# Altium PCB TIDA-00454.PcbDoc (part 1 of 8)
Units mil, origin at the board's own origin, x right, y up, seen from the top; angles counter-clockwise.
Board outline 6159 x 2859 mil, 2 copper layers (Top Layer, Bottom Layer), stack 62 mil thick; 328 components, 224 nets, 884 pads, 184 vias.

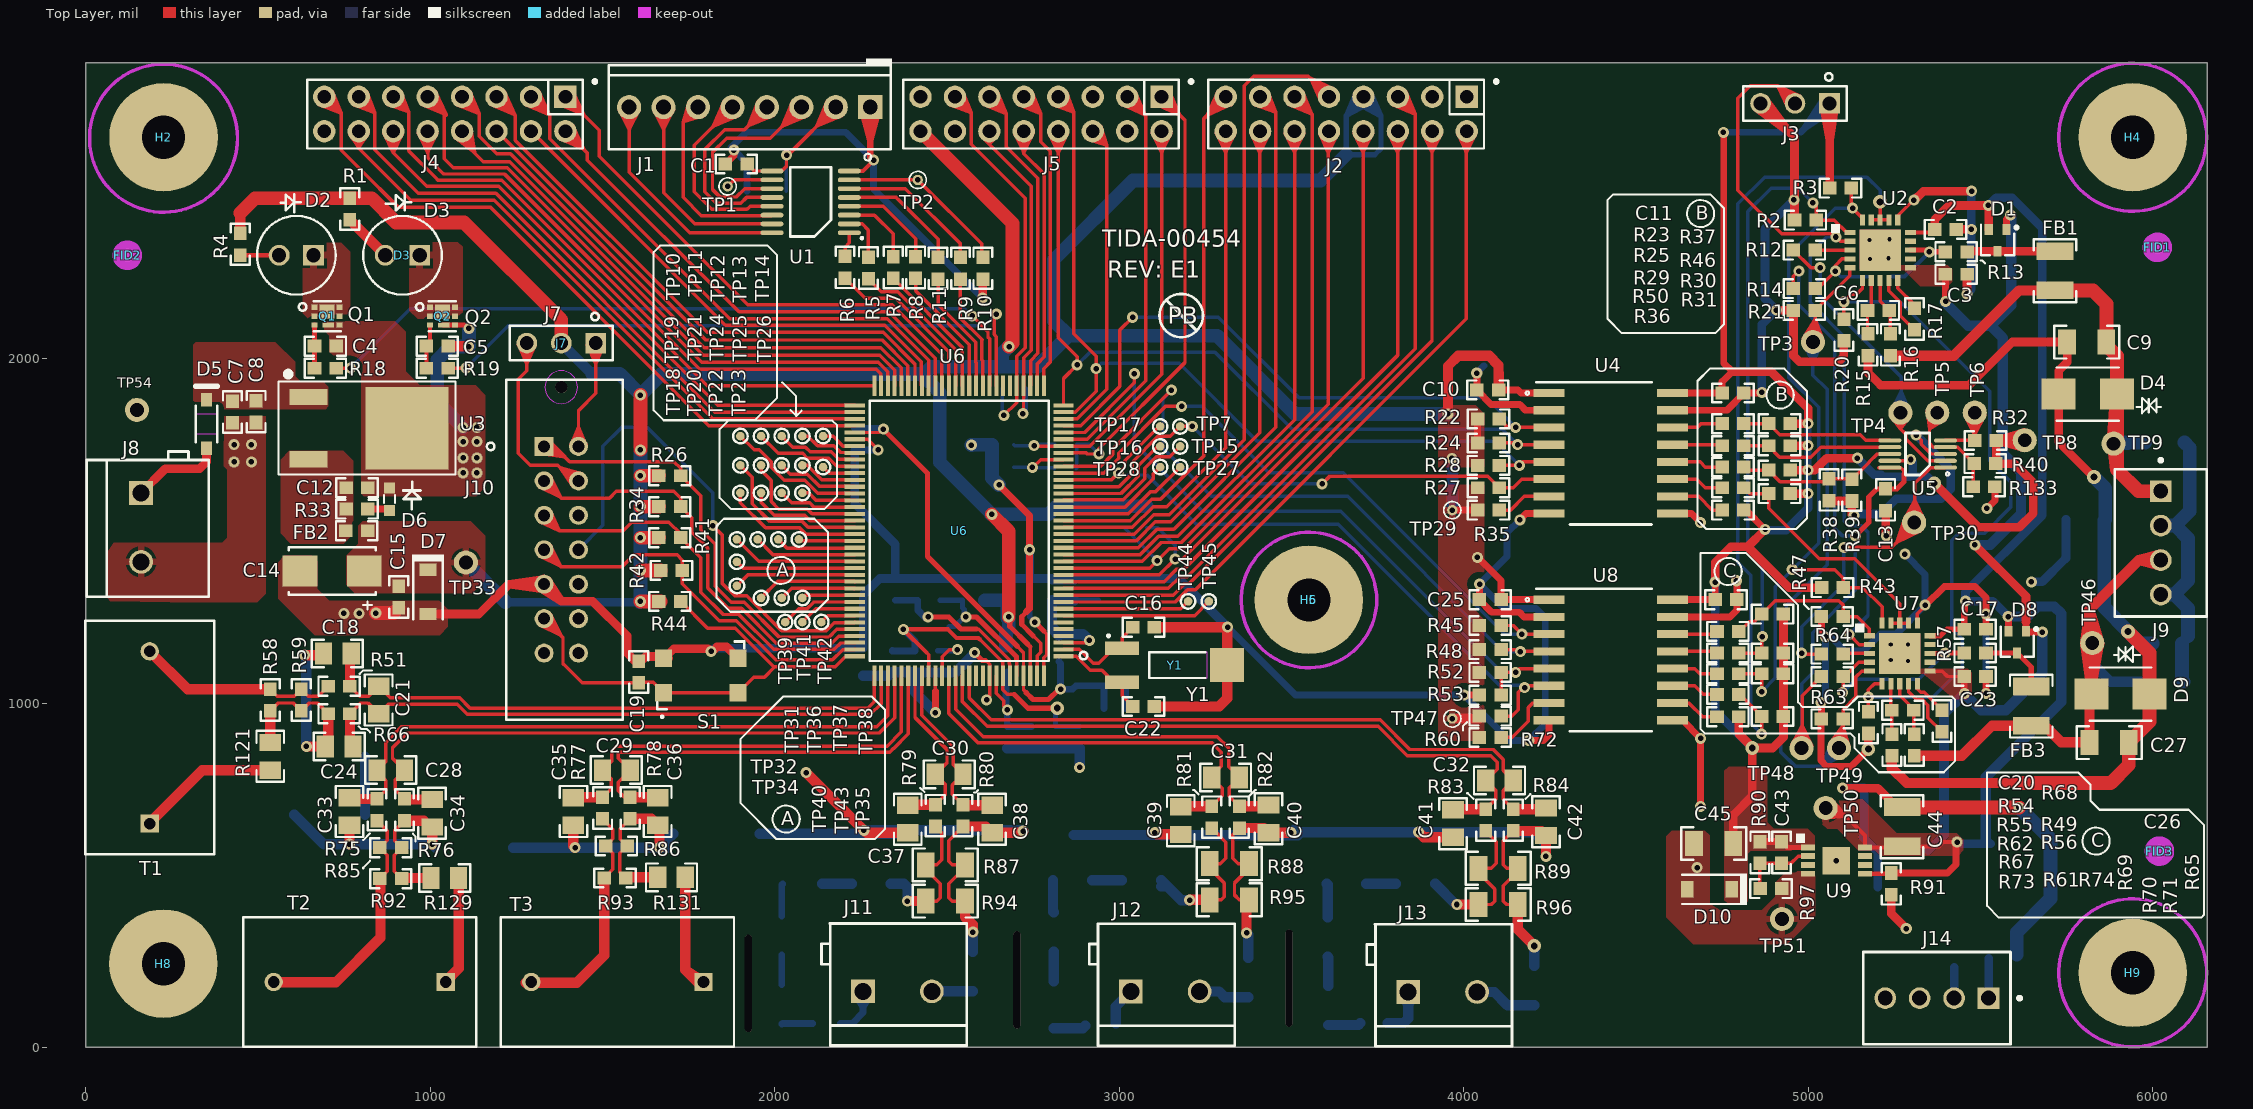
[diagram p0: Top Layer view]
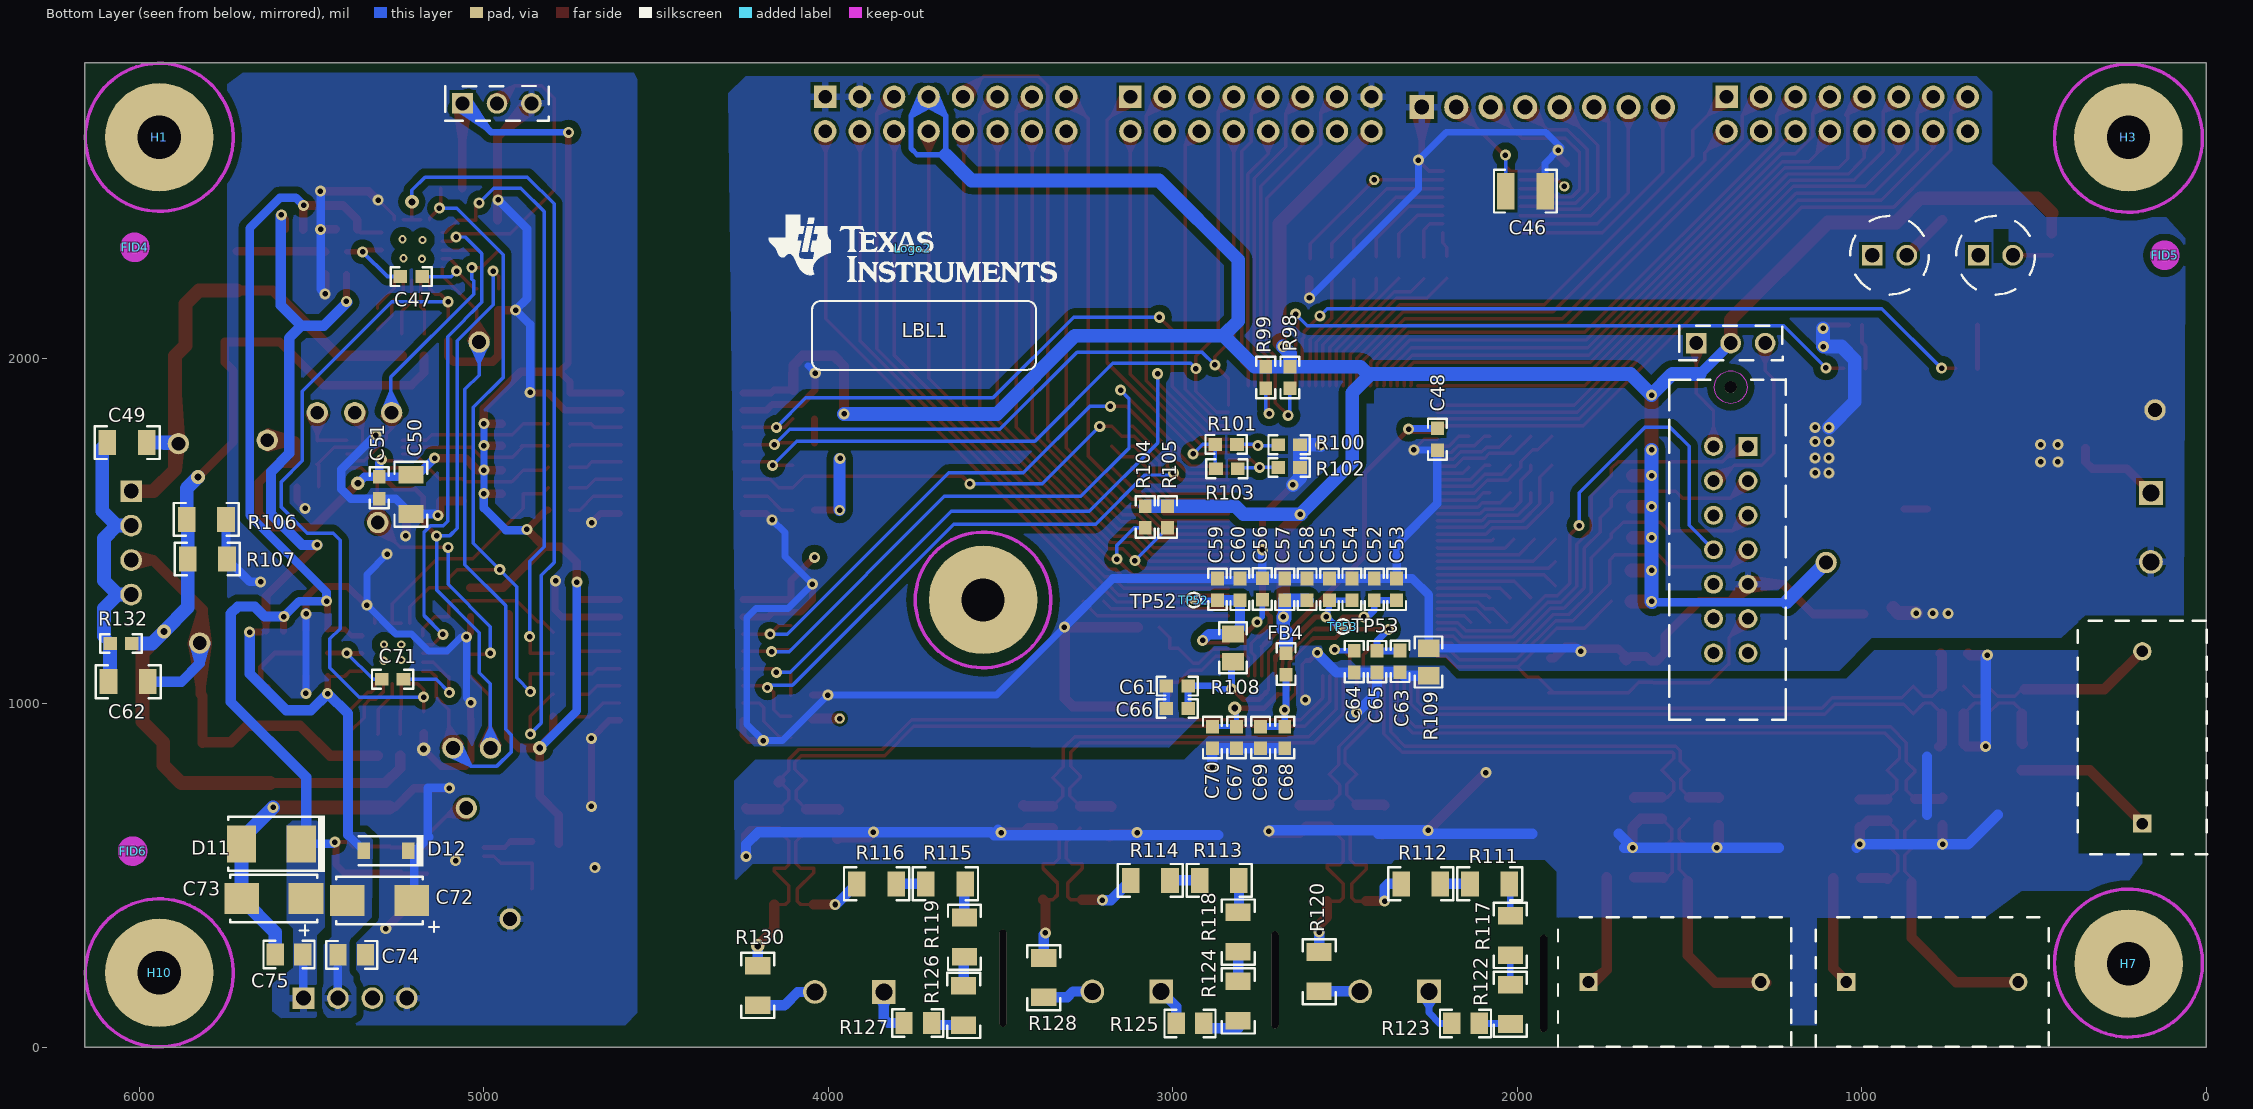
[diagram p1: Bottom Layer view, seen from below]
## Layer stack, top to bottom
Top Solder: solder mask 0.4, Solder Resist, Dk 3.5
Top Layer: signal copper 1.4
Dielectric1: core 59.2, FR-4, Dk 4.8
Bottom Layer: signal copper 1.4
Bottom Solder: solder mask 0.4, Solder Resist, Dk 3.5

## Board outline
0,0 0,2859 6159,2859 6159,0

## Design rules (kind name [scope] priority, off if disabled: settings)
AcuteAngle [All] p1: minimum=4.50000000000000E+0001 checktracksonly=FALSE
AssemblyTestPointUsage [All] p1: valid=2
Clearance Clearance_u4 [(InPadClass('All Pads'))] p1: gap=7.8
Clearance Clearance_1 [IsVia vs IsPad] p2: gap=5
Clearance "Clearance_VIA TO VIA" [IsVia vs IsVia] p3: gap=8
Clearance "Clearance_Via to SMD" [IsVia vs IsPad] p4: gap=8
Clearance Clearance_BoardEdge_MountingHoles [OnCopper and InComponentClass('Mounting Holes') vs IsKeepOut] p5: gap=33
Clearance Clearance_Poly [InPolygon] p6: gap=20
Clearance [All] p7: gap=8
Clearance "Clearance_Poly to Poly" [InPolygon vs InPolygon] p8: gap=20
ComponentClearance ComponentClearance_Logo [InComponentClass('Logo')] p1: gap=50 collisioncheckmode=3 verticalgap=10 showdistances=FALSE
ComponentClearance ComponentClearance_ScrewToNut [(HasFootprint('NY PMS 440 0025 PH')) vs (HasFootprint('Keystone_1902C'))] p2: gap=5 collisioncheckmode=3 verticalgap=10 showdistances=FALSE
ComponentClearance ComponentClearance_MountingHoles [InComponentClass('Mounting Holes')] p3: gap=250 collisioncheckmode=3 verticalgap=100000 showdistances=FALSE
ComponentClearance ComponentClearance_SmallPassives [HasFootprint('0201*') or HasFootprint('0402*') or HasFootprint('0508') or HasFootprint('0603*') or HasFootprint('0612') or HasFootprint('0805*') or HasFootprint('0815*') or HasFootprint('0830*') or HasFootprint('1206*') or HasFootprint('1210*') or HasFootprint('1808*') or HasFootprint('1812*') or HasFootprint('1825*') or HasFootprint('2010*') or HasFootprint('2220*') or HasFootprint('2225*') or HasFootprint('2512*') or HasFootprint('2728*') or HasFootprint('3518*') vs HasFootprint('0201*') or HasFootprint('0402*') or HasFootprint('0508') or HasFootprint('0603*') or HasFootprint('0612') or HasFootprint('0805*') or HasFootprint('0815*') or HasFootprint('0830*') or HasFootprint('1206*') or HasFootprint('1210*') or HasFootprint('1808*') or HasFootprint('1812*') or HasFootprint('1825*') or HasFootprint('2010*') or HasFootprint('2220*') or HasFootprint('2225*') or HasFootprint('2512*') or HasFootprint('2728*') or HasFootprint('3518*')] p4: gap=20 collisioncheckmode=3 verticalgap=10 showdistances=FALSE
ComponentClearance ComponentClearance_THtoSMT [IsThruComponent vs IsSMTComponent] p5: gap=100 collisioncheckmode=3 verticalgap=30 showdistances=FALSE
ComponentClearance ComponentClearance_THtoTH [IsThruComponent vs IsThruComponent] p6: gap=118.11 collisioncheckmode=3 verticalgap=30 showdistances=FALSE
ComponentClearance [All] p7: gap=40 collisioncheckmode=3 verticalgap=10 showdistances=FALSE
DiffPairsRouting [All] p1: maxlimit=100 minlimit=10 mostfreqgap=10 toplayer_minwidth=15 toplayer_maxwidth=15 toplayer_prefwidth=15 bottomlayer_minwidth=15 bottomlayer_maxwidth=15 bottomlayer_prefwidth=15 maxuncoupledlength=1000
FabricationTestPointUsage TestPointUsage [All] p1: valid=2 allowmultiple=FALSE
FabricationTestpoint Testpoint [All] p1: side=3 testpointundercomponent=TRUE minsize=40 maxsize=100 preferedsize=60 minholesize=0 maxholesize=40 preferedholesize=32 testpointgrid=1 allowsidetop=TRUE allowsidebottom=TRUE usegrid=TRUE gridtolerance=0.01
FanoutControl Fanout_LCC [IsLCC] p1: bgadir=Out bgaviamode=Centered fanoutstyle=Auto fanoutdirection=Alternating viagrid=1 // Fanout_LCC (Default Rule)
FanoutControl Fanout_BGA [IsBGA] p2: bgadir=Out bgaviamode=Centered fanoutstyle=Auto fanoutdirection=Alternating viagrid=1 // Fanout_BGA (Default Rule)
FanoutControl Fanout_Default [All] p4: bgadir=Out bgaviamode=Centered fanoutstyle=Auto fanoutdirection=Alternating viagrid=1 // Fanout_Default (Default Rule)
FanoutControl Fanout_Small [(CompPinCount < 5)] p5: bgadir=Out bgaviamode=Centered fanoutstyle=Auto fanoutdirection=OutThenIn viagrid=1 // Fanout_Small (Default Rule)
HoleSize [All] p1: absolutevalues=TRUE maxlimit=300 minlimit=7.8 maxpercent=80.000 minpercent=20.000
MatchedLengths [InNetClass('length')] p1: tolerance=50 checknetsindiffpair=TRUE checkdiffpairvsdiffpair=TRUE checkothers=TRUE
MinimumAnnularRing MinimumAnnularRing_ThermalPadVias [IsVia and InAnyComponent] p1: minimumring=5
MinimumAnnularRing [All] p2: minimumring=5
MinimumSolderMaskSliver MinimumSolderMaskSliver_Logo [InComponentClass('Logo') vs InComponentClass('Logo')] p1: minsoldermaskwidth=0.7
MinimumSolderMaskSliver [All] p2: minsoldermaskwidth=3.94
PlaneClearance [All] p1: clearance=16
PlaneConnect [All] p1: planeconnectstyle=Direct reliefexpansion=10 reliefentries=4 reliefconductorwidth=10 reliefairgap=10
PolygonConnect PolygonConnect_TH_PAD [IsThruPin] p1: connectstyle=Relief reliefconductorwidth=20 reliefentries=4 polygonreliefangle="90 Angle" airgapwidth=10
PolygonConnect PolygonConnect_isVia [IsVia] p2: connectstyle=Direct reliefconductorwidth=10 reliefentries=4 polygonreliefangle="90 Angle" airgapwidth=10
PolygonConnect PolygonConnect_SMTPAD [IsSMTPin] p3: connectstyle=Direct reliefconductorwidth=20 reliefentries=4 polygonreliefangle="90 Angle" airgapwidth=10
RoutingVias RoutingVias_PWR [InNetClass('PWR')] p1: holewidth=16 width=30 viastyle="Through Hole" minholewidth=16 minwidth=30 maxholewidth=20 maxwidth=40
RoutingVias [All] p2: holewidth=12 width=24 viastyle="Through Hole" minholewidth=12 minwidth=24 maxholewidth=20 maxwidth=40
RoutingVias ThermalPadVias [InNet('GND_SIGNAL')] p3: holewidth=7.87 width=19.68 viastyle="Through Hole" minholewidth=7.87 minwidth=19.68 maxholewidth=12.99 maxwidth=23.62
SMDToCorner [All] p1: distance=30000
SilkToSilkClearance [All] p1: silktosilkclearance=5
SilkToSolderMaskClearance SilkscreenOverComponentPads [IsPad] p1: minsilkscreentomaskgap=5 clearancetoexposedcopper=TRUE
SolderMaskExpansion [All] p1: expansion=2.5
UnpouredPolygon [All] p1: allowunpoured=FALSE
ViasUnderSMD [InComponent('U1')] p1: allowed=TRUE
Width Width_PWR [InNetClass('PWR')] p1: maxlimit=100 minlimit=8 preferedwidth=20 minimp=50.000000 maximp=50.000000 favimp=50.000000
Width [All] p2: maxlimit=100 minlimit=10 preferedwidth=10 checkconnectedcopper=TRUE
14 further rules are at their usual default settings.

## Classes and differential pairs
component class "Pg7.Digital Isolators": C10 C11 C20 C25 R22 R23 R24 R25 R27 R28 R29 R30 R31 R35 R36 R37 R38 R45 R46 R48 R49 R50 R52 R53 R54 R55 R56 R60 R61 R62 R67 R68 R72 R73 TP29 TP47 U4 U8
component class Pg3.MSP430F67791A+LED: C4 C5 C16 C22 C66 D2 D3 Q1 Q2 R1 R4 R18 R19 R98 R99 R100 R101 R102 R103 R104 R105 R108 TP7 TP10 TP11 TP12 TP13 TP14 TP15 TP16 TP17 TP18 TP19 TP20 TP21 TP22 TP23 TP24 TP25 TP26 TP27 TP28 TP31 TP32 TP34 TP35 TP36 TP37 TP38 TP39 TP40 TP41 TP42 TP43 TP44 TP45 U6 Y1
component class "Pg6.Isolated and Non Isolated Power Supply": C7 C8 C12 C14 C15 C43 C44 C45 C72 C73 C74 C75 D5 D6 D7 D10 D11 D12 D19 FB2 J8 J14 R33 R90 R91 R97 R106 R107 TP8 TP33 TP50 TP51 TP54 U3 U9
component class "Pg10.HARDWARE - MISCELLANEOUS.": !PCB1 FID1 FID2 FID3 FID4 FID5 FID6 H1 H2 H3 H4 H5 H6 H7 H8 H9 H10 ZZ1 ZZ2 ZZ3 ZZ4
component class "Mounting Holes": H2 H4 H6 H8 H9
component class FiducialMark: FID1 FID2 FID3 FID4 FID5 FID6
component class AssemblyNote: ZZ1 ZZ2 ZZ3 ZZ4
component class "Pg5.Analog Front End - Current and Voltage": C18 C21 C24 C28 C29 C30 C31 C32 C33 C34 C35 C36 C37 C38 C39 C40 C41 C42 J11 J12 J13 R51 R58 R59 R66 R75 R76 R77 R78 R79 R80 R81 R82 R83 R84 R85 R86 R87 R88 R89 R92 R93 R94 R95 R96 R111 R112 R113 R114 R115 R116 R117 R118 R119 R120 R121 R122 R123 R124 R125 R126 R127 R128 R129 R130 R131 T1 T2 T3
component class "Pg4. Relay Drivers+JTAG Interface +Decoupling Capacitors": C1 C19 C46 C48 C52 C53 C54 C55 C56 C57 C58 C59 C60 C61 C63 C64 C65 C67 C68 C69 C70 FB4 J1 J7 J10 R5 R6 R7 R8 R9 R10 R11 R26 R34 R41 R42 R44 R109 S1 TP1 TP2 TP52 TP53 U1
component class "Pg8. Analog Outputs": C2 C3 C6 C9 C13 C17 C23 C26 C27 C47 C49 C50 C51 C62 C71 D1 D4 D8 D9 FB1 FB3 J3 J9 R2 R3 R12 R13 R14 R15 R16 R17 R20 R21 R32 R39 R40 R43 R47 R57 R63 R64 R65 R69 R70 R71 R74 R132 R133 TP3 TP4 TP5 TP6 TP9 TP30 TP46 TP48 TP49 U2 U5 U7
component class "Pg9 Expansion Interface": J2 J4 J5

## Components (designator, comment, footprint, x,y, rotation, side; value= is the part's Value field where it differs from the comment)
C1 "06035C104KAT2A" 0603 1888,2565 r180 top (schematic designator C67)
C2 "GRM188R71H104KA93D" 0603 5399,2375 r0 top (schematic designator C79)
C3 "GRM188R71H104KA93D" 0603 5430,2245 r0 top (schematic designator C80)
C4 "06033C104JAT2A" 0603 695,2036 r0 top (schematic designator C35)
C5 "06033C104JAT2A" 0603 1020,2036 r0 top (schematic designator C37)
C6 "C0603C103J5RACTU" 0603 5204,2140 r180 top (schematic designator C81)
C7 "C1608X7R1C105K" 0603 425,1845 r270 top (schematic designator C28)
C8 "C0603C104K5RACTU" 0603 493.89,1846 r270 top (schematic designator C29)
C9 "202R18W102KV4E" 1206 5809,2048 r180 top (schematic designator C87)
C10 "C0603C104K5RACTU" 0603 4070,1909 r0 top (schematic designator C68)
C11 "C0603C104K5RACTU" 0603 4782,1900 r0 top (schematic designator C69)
C12 "C1608X7R1C105K" 0603 787,1625 r0 top (schematic designator C30)
C13 "C0603C223K4RACTU" 0603 5225,1590 r270 top (schematic designator C78)
C14 "293D475X9035C2TE3" 6032-28 715,1383 r180 top (schematic designator C31)
C15 "C0603C104K5RACTU" 0603 908,1308 r270 top (schematic designator C32)
C16 "06035A120JAT2A" 0603 3070.51,1220 r0 top (schematic designator C53)
C17 "GRM188R71H104KA93D" 0603 5485,1214 r0 top (schematic designator C71)
C18 "GRM21A5C2E470JW01D" 0805_HV 730,1143.8 r180 top (schematic designator C1)
C19 "06033C104JAT2A" 0603 1605,1090 r270 top (schematic designator C34)
C20 "C0603C104K5RACTU" 0603 4762,1300 r0 top (schematic designator C22)
C21 "08055C153KAT2A" 0805_HV 850,1008.8 r270 top (schematic designator C2)
C22 "06035A120JAT2A" 0603 3070.51,990 r0 top (schematic designator C52)
C23 "GRM188R71H104KA93D" 0603 5485,1077 r0 top (schematic designator C72)
C24 "GRM21A5C2E470JW01D" 0805_HV 735,873.8 r0 top (schematic designator C3)
C25 "C0603C104K5RACTU" 0603 4077,1300 r0 top (schematic designator C24)
C26 "C0603C103J5RACTU" 0603 5275,979 r180 top (schematic designator C73)
C27 "202R18W102KV4E" 1206 5874,885 r0 top (schematic designator C76)
C28 "08055C153KAT2A" 0805_HV 885,805 r0 top (schematic designator C8)
C29 "08055C153KAT2A" 0805_HV 1540,805 r0 top (schematic designator C14)
C30 "08055C153KAT2A" 0805_HV 2506,793 r0 top (schematic designator C5)
C31 "08055C153KAT2A" 0805_HV 3308.62,783.5 r0 top (schematic designator C11)
C32 "08055C153KAT2A" 0805_HV 4104,775 r0 top (schematic designator C17)
C33 "GRM21A5C2E470JW01D" 0805_HV 765,685 r270 top (schematic designator C7)
C34 "GRM21A5C2E470JW01D" 0805_HV 1005,680 r90 top (schematic designator C9)
C35 "GRM21A5C2E470JW01D" 0805_HV 1415,685 r270 top (schematic designator C13)
C36 "GRM21A5C2E470JW01D" 0805_HV 1660,685 r90 top (schematic designator C15)
C37 "GRM21A5C2E470JW01D" 0805_HV 2386,663 r270 top (schematic designator C4)
C38 "GRM21A5C2E470JW01D" 0805_HV 2631,663 r90 top (schematic designator C6)
C39 "GRM21A5C2E470JW01D" 0805_HV 3178.62,658.5 r270 top (schematic designator C10)
C40 "GRM21A5C2E470JW01D" 0805_HV 3433.62,663.5 r90 top (schematic designator C12)
C41 "GRM21A5C2E470JW01D" 0805_HV 3969,650 r270 top (schematic designator C16)
C42 "GRM21A5C2E470JW01D" 0805_HV 4239,655 r90 top (schematic designator C18)
C43 "C0603C103J5RACTU" 0603 4923,566 r90 top (schematic designator C59)
C44 "GRM32ER71H106KA12L" 1210 5273,641 r90 top (schematic designator C58)
C45 "GRM31CR71C106KAC7L" 1206 4726,592 r0 top (schematic designator C70)
C46 "GRM32ER71H106KA12L" 1210 1976,2486 r180 bottom (schematic designator C21)
C47 "C1608X7R1H473K" 0603 5211,2238 r180 bottom (schematic designator C77)
C48 "06033C104JAT2A" 0603 2231.85,1765.75 r270 bottom
C49 "202R18W102KV4E" 1206 6036,1756 r0 bottom (schematic designator C62)
C50 "C3216X7R1C475K" 1206 5212,1606 r270 bottom (schematic designator C74)
C51 "GRM188R71H104KA93D" 0603 5304,1625 r270 bottom (schematic designator C75)
C52 "06033C104JAT2A" 0603 2415,1330 r90 bottom (schematic designator C46)
C53 "CRCW06030000Z0EA" 0603 2350,1330 r90 bottom (schematic designator C45)
C54 "CRCW06030000Z0EA" 0603 2480,1330 r90 bottom (schematic designator C43)
C55 "06033C104JAT2A" 0603 2545,1330 r90 bottom (schematic designator C44)
C56 "GRM188R71E474KA12J" 0603 2740,1331 r90 bottom (schematic designator C60)
C57 "06033C104JAT2A" 0603 2675,1330 r90 bottom (schematic designator C50)
C58 "0603ZD475KAT2A" 0603 2610,1330 r90 bottom (schematic designator C49)
C59 "06033C104JAT2A" 0603 2870,1330 r90 bottom (schematic designator C42)
C60 "GRM188R71E474KA12J" 0603 2805,1330 r90 bottom (schematic designator C41)
C61 "0603ZD475KAT2A" 0603 2987,1049 r0 bottom (schematic designator C47)
C62 "202R18W102KV4E" 1206 6033,1062 r0 bottom (schematic designator C63)
C63 "0603ZD475KAT2A" 0603 2340,1121 r270 bottom (schematic designator C38)
C64 "06033C104JAT2A" 0603 2473,1120 r270 bottom (schematic designator C40)
C65 "06033C104JAT2A" 0603 2407,1120 r270 bottom (schematic designator C39)
C66 "06033C104JAT2A" 0603 2987,984 r180 bottom (schematic designator C56)
C67 "06033C104JAT2A" 0603 2815,900 r270 bottom (schematic designator C61)
C68 "06033C104JAT2A" 0603 2675,900 r270 bottom (schematic designator C37)
C69 "0603ZD475KAT2A" 0603 2745,900 r270 bottom (schematic designator C36)
C70 "0603ZD475KAT2A" 0603 2885,900 r270 bottom (schematic designator C54)
C71 "C1608X7R1H473K" 0603 5265,1068.9 r180 bottom (schematic designator C26)
C72 "293D106X9025C2TE3" 6032-28 5303,427 r0 bottom (schematic designator C64)
C73 "TPSC106K025R0300" 6032-28 5610,432 r0 bottom (schematic designator C65)
C74 "GRM21BR61C226ME44" 0805_HV 5384,269 r0 bottom (schematic designator C55)
C75 "GRM21BR61C226ME44" 0805_HV 5566,270 r0 bottom (schematic designator C20)
D1 "DESD1P0RFW-7" SOT-323 5550,2343 r270 top (schematic designator D13)
D2 "TLHR6405" LED_5MM 611,2300 r0 top (schematic designator D7)
D3 "TLHR6405" LED_5MM 919,2300 r0 top (schematic designator D4)
D4 "SMBJ18CA" DIO_SMB_BIAAAA 5812,1897 r180 top (schematic designator D15)
D5 "B0520LW-7-F" DIO_SOD-123 350,1810 r270 top (schematic designator D1)
D6 "LED_LG L29K-G2J1-24-Z" LED0603AA 881,1592 r270 top (schematic designator D2)
D7 "MMSZ5228B-7-F" sod-123 993,1323 r270 top (schematic designator D3)
D8 "DESD1P0RFW-7" SOT-323 5607,1177 r270 top (schematic designator D14)
D9 "SMBJ18CA" DIO_SMB_BIAAAA 5907,1026 r0 top (schematic designator D16)
D10 "MMSZ4690-V" SOD-123 4714,459 r180 top (schematic designator D8)
D11 "SMBJ5929BE3/TR13" SMB 5617,591 r0 bottom (schematic designator D19)
D12 "MMSZ4702" SOD-123 5284,571 r0 bottom (schematic designator D18)
FB1 "MH3261-501Y" 1210 5717,2255 r270 top (schematic designator FB7)
FB2 "1000 OHM" 0603 786,1500 r0 top (schematic designator FB9)
FB3 "MH3261-501Y" 1210 5648,991 r270 top (schematic designator FB8)
FB4 "1000 OHM" 0603 2671,1113 r270 bottom
FID1 "Fiducial" Fiducial10-20#1 6014,2323 r90 top (schematic designator FID3)
FID2 "Fiducial" Fiducial10-20#1 120,2300 r90 top (schematic designator FID1)
FID3 "Fiducial" Fiducial10-20#1 6020,570 r90 top (schematic designator FID2)
FID4 "Fiducial" Fiducial10-20#2 6014,2323 r90 bottom
FID5 "Fiducial" Fiducial10-20#2 120,2300 r90 bottom (schematic designator FID1)
FID6 "Fiducial" Fiducial10-20#2 6020,570 r90 bottom
H1 "1902C" Keystone_1902C#1 5942.48,2642.48 r180 bottom (schematic designator H6)
H2 "NY PMS 440 0025 PH" "NY PMS 440 0025 PH"#1 225,2634.41 r0 top locked (schematic designator H3)
H3 "1902C" Keystone_1902C#1 225.15,2642.48 r180 bottom (schematic designator H5)
H4 "NY PMS 440 0025 PH" "NY PMS 440 0025 PH"#2 6039.83,2673.41 r0 top locked
H5 "1902C" Keystone_1902C#2 3550.83,1299.21 r0 top (schematic designator H10)
H6 "NY PMS 440 0025 PH" "NY PMS 440 0025 PH"#3 3550,1306 r0 top (schematic designator H10)
H7 "1902C" Keystone_1902C#1 225,243.54 r180 bottom (schematic designator H8)
H8 "NY PMS 440 0025 PH" "NY PMS 440 0025 PH"#4 225,243.54 r0 top (schematic designator H1)
H9 "NY PMS 440 0025 PH" "NY PMS 440 0025 PH"#5 5998.83,243.54 r0 top locked (schematic designator H2)
H10 "1902C" Keystone_1902C#1 5942.48,216.54 r180 bottom (schematic designator H7)
J1 "1725711" CONN_1725711 1927,2730 r180 top (schematic designator J7)
J2 "67997-416HLF" TSW-108-07-G-D 3659,2710 r180 top (schematic designator J14)
J3 "68001-403HLF" HDR1X3 4962,2741 r270 top (schematic designator J18)
J4 "67997-416HLF" TSW-108-07-G-D 1042,2710 r180 top (schematic designator J16)
J5 "67997-416HLF" TSW-108-07-G-D 2773,2710 r180 top (schematic designator J9)
J7 "68001-403HLF" HDR1X3 1380,2045 r270 top (schematic designator J11)
J8 "ED120/2DS" CONN_ED120-2DS 160,1510 r180 top (schematic designator J10)
J9 "282834-4" TEC_282834-4 6024,1465 r270 top (schematic designator J17)
J10 "N2514-6002-RB" 3M_N2514-6002-RB 1380,1445 r270 top locked (schematic designator J8)
J11 "ED120/2DS" CONN_ED120-2DS 2356,163 r270 top locked (schematic designator J2)
J12 "ED120/2DS" CONN_ED120-2DS 3133.62,162.48 r270 top (schematic designator J4)
J13 "ED120/2DS" CONN_ED120-2DS 3939,161 r270 top (schematic designator J5)
J14 "282834-4" TEC_282834-4 5374,143 r180 top (schematic designator J13)
LBL1 "Size: 0.65\" x 0.20 \"" Label_650x200 3722,2067.48 r180 bottom
Logo2 "Texas Instruments" TI_Stacked_Overlay_Small 3755,2320 r180 bottom
Q1 "CSD17571Q2" SON_CSD17571Q2 700,2123 r270 top (schematic designator Q2)
Q2 "CSD17571Q2" SON_CSD17571Q2 1035,2123 r270 top (schematic designator Q1)
R1 "CRCW0603330RJNEA" 0603 766,2434 r90 top (schematic designator R64)
R2 "CRCW0603100KFKEA" 0603 4992,2402 r180 top (schematic designator R123)
R3 "CRCW0603100KFKEA" 0603 5094,2495 r180 top (schematic designator R120)
R4 "CRCW0603330RJNEA" 0603 448,2332 r90 top (schematic designator R71)
R5 "CRCW06031K00FKEA" 0603 2271.76,2263.19 r90 top (schematic designator R80)
R6 "CRCW06031K00FKEA" 0603 2204,2265 r90 top (schematic designator R48)
R7 "CRCW06031K00FKEA" 0603 2343.76,2264.19 r90 top (schematic designator R81)
R8 "CRCW06031K00FKEA" 0603 2408.76,2264.19 r90 top (schematic designator R58)
R9 "CRCW06031K00FKEA" 0603 2539.02,2262.18 r90 top (schematic designator R57)
R10 "CRCW06031K00FKEA" 0603 2604.02,2262.18 r90 top (schematic designator R56)
R11 "CRCW06031K00FKEA" 0603 2474.02,2262.18 r90 top (schematic designator R49)
R12 "RT0603BRD071K02L" 0603 4989,2315 r0 top (schematic designator R125)
R13 "CRCW060315R0FKEA" 0603 5430,2310 r0 top (schematic designator R126)
R14 "RT0603BRD071K02L" 0603 4989,2203 r0 top (schematic designator R127)
R15 "CRCW06032K00FKEA" 0603 5174,2040 r90 top (schematic designator R131)
R16 "CRCW06032K00FKEA" 0603 5239,2040 r90 top (schematic designator R132)
R17 "RG1608P-8251-B-T5" 0603 5309,2115 r90 top (schematic designator R129)
R18 "CRCW0603300RJNEA" 0603 695,1972 r180 top (schematic designator R12)
R19 "CRCW0603300RJNEA" 0603 1020,1972 r180 top (schematic designator R70)
R20 "CRCW0603750RFKEA" 0603 5104,2083 r270 top (schematic designator R130)
R21 "CRCW0603750RFKEA" 0603 4989,2140 r0 top (schematic designator R128)
R22 "CRCW060310K0FKEA" 0603 4072,1825 r180 top (schematic designator R54)
R23 "RC0603JR-070RL" 0603 4782,1811 r0 top (schematic designator R43)
R24 "CRCW060310K0FKEA" 0603 4072,1755 r180 top (schematic designator R62)
R25 "RC0603JR-070RL" 0603 4782,1747 r0 top (schematic designator R39)
R26 "CRCW060310K0JNEA" 0603 1695,1660 r0 top (schematic designator R67)
R27 "CRCW060310K0FKEA" 0603 4072,1625 r180 top (schematic designator R53)
R28 "CRCW060310K0FKEA" 0603 4072,1690 r180 top (schematic designator R51)
R29 "RC0603JR-070RL" 0603 4782,1685 r0 top (schematic designator R40)
R30 "CRCW060310K0FKEA" 0603 4917,1676 r0 top (schematic designator R60)
R31 "CRCW060310K0FKEA" 0603 4917,1608 r0 top (schematic designator R59)
R32 "CRCW060310K0FKEA" 0603 5515,1762 r0 top (schematic designator R116)
R33 "CRCW0603300RJNEA" 0603 787,1563 r180 top (schematic designator R63)
R34 "CRCW060310K0JNEA" 0603 1695,1570 r0 top (schematic designator R66)
R35 "RC0603JR-070RL" 0603 4072,1560 r0 top (schematic designator R91)
R36 "RC0603JR-070RL" 0603 4782,1560 r0 top (schematic designator R92)
R37 "CRCW060310K0FKEA" 0603 4917,1811 r0 top (schematic designator R42)
R38 "CRCW060310K0FKEA" 0603 5061,1619 r90 top (schematic designator R41)
R39 "CRCW0603100KFKEA" 0603 5127,1618 r90 top (schematic designator R121)
R40 "CRCW060310K0FKEA" 0603 5514,1695 r0 top (schematic designator R117)
R41 "CRCW060310K0JNEA" 0603 1695,1480 r0 top (schematic designator R68)
R42 "CRCW060310K0JNEA" 0603 1700,1385 r0 top (schematic designator R65)
R43 "CRCW0603100KFKEA" 0603 5071,1335 r180 top (schematic designator R104)
R44 "CRCW060347K0JNEA" 0603 1695,1295 r180 top (schematic designator R69)
R45 "CRCW060310K0FKEA" 0603 4077,1225 r180 top (schematic designator R96)
R46 "CRCW060310K0FKEA" 0603 4917,1747 r0 top (schematic designator R44)
R47 "CRCW0603100KFKEA" 0603 5070,1251 r180 top (schematic designator R109)
R48 "CRCW060310K0FKEA" 0603 4077,1155 r180 top (schematic designator R95)
R49 "CRCW060310K0FKEA" 0603 4897,1145 r0 top (schematic designator R50)
R50 "RC0603JR-070RL" 0603 4782,1625 r0 top (schematic designator R47)
R51 "CRCW06031K00JNEA" 0603 735,1048.8 r180 top (schematic designator R1)
R52 "CRCW060310K0FKEA" 0603 4077,1089 r180 top (schematic designator R94)
R53 "CRCW060310K0FKEA" 0603 4077,1023 r0 top (schematic designator R3)
R54 "RC0603JR-070RL" 0603 4767,1208 r0 top
R55 "RC0603JR-070RL" 0603 4767,1145 r0 top (schematic designator R98)
R56 "CRCW060310K0FKEA" 0603 4897,1085 r0 top (schematic designator R100)
R57 "CRCW060315R0FKEA" 0603 5485,1145 r0 top (schematic designator R111)
R58 "CRCW0603100RFKEA" 0603 535,1008.8 r90 top (schematic designator R2)
R59 "CRCW0603100RFKEA" 0603 625,1008.8 r90 top (schematic designator R3)
R60 "CRCW060310K0FKEA" 0603 4077,962 r180 top (schematic designator R93)
R61 "CRCW060310K0FKEA" 0603 4897,961 r0 top (schematic designator R37)
R62 "RC0603JR-070RL" 0603 4767,1085 r0 top (schematic designator R99)
R63 "RT0603BRD071K02L" 0603 5070,1077 r0 top (schematic designator R112)
R64 "RT0603BRD071K02L" 0603 5070,1142 r0 top (schematic designator R110)
R65 "RG1608P-8251-B-T5" 0603 5389,948 r90 top (schematic designator R114)
R66 "CRCW06031K00JNEA" 0603 735,968.8 r180 top (schematic designator R9)
R67 "RC0603JR-070RL" 0603 4767,1025 r0 top (schematic designator R100)
R68 "CRCW060310K0FKEA" 0603 4897,1258 r0 top (schematic designator R45)
R69 "CRCW0603750RFKEA" 0603 5175,943 r270 top (schematic designator R115)
R70 "CRCW06032K00FKEA" 0603 5243.3,878 r90 top (schematic designator R118)
R71 "CRCW06032K00FKEA" 0603 5308.3,878 r90 top (schematic designator R119)
R72 "RC0603JR-070RL" 0603 4077,900 r0 top (schematic designator R101)
R73 "RC0603JR-070RL" 0603 4767,960 r0 top (schematic designator R102)
R74 "CRCW0603750RFKEA" 0603 5070,954 r0 top (schematic designator R113)
R75 "CRCW06031K00JNEA" 0603 845,690 r270 top (schematic designator R13)
R76 "CRCW06031K00JNEA" 0603 925,690 r270 top (schematic designator R22)
R77 "CRCW06031K00JNEA" 0603 1500,695 r270 top (schematic designator R25)
R78 "CRCW06031K00JNEA" 0603 1580,695 r270 top (schematic designator R35)
R79 "CRCW06031K00JNEA" 0603 2466,673 r270 top (schematic designator R8)
R80 "CRCW06031K00JNEA" 0603 2546,673 r270 top (schematic designator R12)
R81 "CRCW06031K00JNEA" 0603 3268.62,668.5 r270 top (schematic designator R20)
R82 "CRCW06031K00JNEA" 0603 3348.62,668.5 r270 top (schematic designator R24)
R83 "CRCW06031K00JNEA" 0603 4064,660 r270 top (schematic designator R31)
R84 "CRCW06031K00JNEA" 0603 4144,660 r270 top (schematic designator R36)
R85 "CRCW0603100RFKEA" 0603 885,580 r180 top (schematic designator R15)
R86 "CRCW0603100RFKEA" 0603 1540,585 r180 top (schematic designator R32)
R87 "RC1206FR-072K4L" 1206 2495,530 r0 top (schematic designator R11)
R88 "RC1206FR-072K4L" 1206 3319.62,533.5 r0 top (schematic designator R23)
R89 "RC1206FR-072K4L" 1206 4100,520 r0 top (schematic designator R34)
R90 "CRCW060311K0FKEA" 0603 4860,566 r90 top (schematic designator R105)
R91 "CRCW0603100KFKEA" 0603 5241.5,475 r90 top (schematic designator R108)
R92 "CRCW0603100RFKEA" 0603 885,490 r180 top (schematic designator R14)
R93 "CRCW0603100RFKEA" 0603 1535.7,492 r180 top (schematic designator R26)
R94 "RC1206FR-072K4L" 1206 2495,425 r0 top (schematic designator R10)
R95 "RC1206FR-072K4L" 1206 3319.62,428.5 r0 top (schematic designator R21)
R96 "RC1206FR-072K4L" 1206 4100,415 r0 top (schematic designator R33)
R97 "RC0603FR-073KL" 0603 4892,461 r0 top (schematic designator R107)
R98 "CRCW06032K20JNEA" 0603 2660,1945 r90 bottom (schematic designator R78)
R99 "CRCW06032K20JNEA" 0603 2730,1945 r90 bottom (schematic designator R79)
R100 "CRCW0603560KFKEA" 0603 2662,1750 r180 bottom (schematic designator R83)
R101 "CRCW0603560KFKEA" 0603 2845,1751 r0 bottom (schematic designator R85)
R102 "CRCW06030000Z0EA" 0603 2662,1684 r0 bottom (schematic designator R84)
R103 "CRCW0603560KFKEA" 0603 2843,1680 r180 bottom (schematic designator R82)
R104 "CRCW06032K20JNEA" 0603 3080,1540 r90 bottom (schematic designator R77)
R105 "CRCW06032K20JNEA" 0603 3015,1540 r90 bottom (schematic designator R76)
R106 "RC1206JR-070RL" 1206 5806,1533 r180 bottom (schematic designator R41)
R107 "RC1206JR-070RL" 1206 5803,1418 r180 bottom (schematic designator R46)
R108 "CRCW08050000Z0EA" 0805_HV 2825,1160 r90 bottom (schematic designator R75)
R109 "CRCW08050000Z0EA" 0805_HV 2257,1119 r90 bottom (schematic designator R72)
R111 "ERJ-8ENF3323V" 1206 2080,475 r0 bottom (schematic designator R6)
R112 "ERJ-8ENF3323V" 1206 2280,475 r0 bottom (schematic designator R7)
R113 "ERJ-8ENF3323V" 1206 2865,485 r0 bottom (schematic designator R18)
R114 "ERJ-8ENF3323V" 1206 3065,485 r0 bottom (schematic designator R19)
R115 "ERJ-8ENF3323V" 1206 3660,475 r0 bottom (schematic designator R29)
R116 "ERJ-8ENF3323V" 1206 3860,475 r0 bottom (schematic designator R30)
R117 "ERJ-8ENF3323V" 1206 2020,325 r90 bottom (schematic designator R5)
R118 "ERJ-8ENF3323V" 1206 2810,335 r90 bottom (schematic designator R17)
R119 "ERJ-8ENF3323V" 1206 3605,320 r90 bottom (schematic designator R28)
R120 "CRCW12060000Z0EA" 1206 2575,220 r90 bottom (schematic designator R87)
R121 "CRCW08050000Z0EA" 0805_HV 535,845 r90 top (schematic designator R91)
R122 "ERJ-8ENF3323V" 1206 2020,125 r90 bottom (schematic designator R4)
R123 "CRCW08050000Z0EA" 0805_HV 2150,70 r180 bottom (schematic designator R86)
R124 "ERJ-8ENF3323V" 1206 2810,135 r90 bottom (schematic designator R16)
R125 "CRCW08050000Z0EA" 0805_HV 2950,70 r180 bottom (schematic designator R88)
R126 "ERJ-8ENF3323V" 1206 3607,122 r90 bottom (schematic designator R27)
R127 "CRCW08050000Z0EA" 0805_HV 3740,71 r180 bottom (schematic designator R90)
R128 "CRCW12060000Z0EA" 1206 3374.62,202.48 r90 bottom (schematic designator R89)
R129 "CRCW08050000Z0EA" 0805_HV 1042,492 r180 top
R130 "CRCW12060000Z0EA" 1206 4205,180 r90 bottom
R131 "CRCW08050000Z0EA" 0805_HV 1700,494 r180 top
R132 "RC0603JR-070RL" 0603 6054,1173 r0 bottom
R133 "CRCW060310K0FKEA" 0603 5511,1628 r180 top
S1 "7914G-1-000E" SW_7914G-1-000E 1785,1080 r90 top
T1 "AP-2500" XFMR_AP-2500 185,900 r90 top
T2 "AP-2500" XFMR_AP-2500 795,190 r180 top
T3 "AP-2500" XFMR_AP-2500 1542.95,190 r180 top
TP1 "TP-038" TP1_PD40_D0.5_S50 1863,2500 r180 top (schematic designator TP21)
TP2 "TP-038" TP1_PD40_D0.5_S50 2415,2518.6 r180 top (schematic designator TP20)
TP3 "TP-040_RND" TP-040_RND 5014,2048 r90 top (schematic designator TP27)
TP4 "TP-040_RND" TP-040_RND 5268,1843 r90 top (schematic designator TP44)
TP5 "TP-040_RND" TP-040_RND 5375,1843 r90 top (schematic designator TP42)
TP6 "TP-040_RND" TP-040_RND 5484,1843 r90 top (schematic designator TP25)
TP7 "TP-040_RND" TP_25MIL-SMT 3177,1803 r0 top (schematic designator TP51)
TP8 "TP-040_RND" TP-040_RND 5629,1763 r180 top (schematic designator TP38)
TP9 "TP-040_RND" TP-040_RND 5887,1753 r90 top (schematic designator TP45)
TP10 "TP-040_RND" TP_25MIL-SMT 1900,1775 r0 top (schematic designator TP29)
TP11 "TP-040_RND" TP_25MIL-SMT 1960,1775 r0 top (schematic designator TP33)
TP12 "TP-040_RND" TP_25MIL-SMT 2020,1775 r0 top (schematic designator TP34)
TP13 "TP-040_RND" TP_25MIL-SMT 2080,1775 r0 top (schematic designator TP35)
TP14 "TP-040_RND" TP_25MIL-SMT 2140,1775 r0 top
TP15 "TP-040_RND" TP_25MIL-SMT 3177,1745 r0 top (schematic designator TP49)
TP16 "TP-040_RND" TP_25MIL-SMT 3119,1745 r0 top (schematic designator TP50)
TP17 "TP-040_RND" TP_25MIL-SMT 3119,1803 r0 top (schematic designator TP52)
TP18 "TP-040_RND" TP_25MIL-SMT 1900,1610 r0 top
TP19 "TP-040_RND" TP_25MIL-SMT 1900,1690 r0 top
TP20 "TP-040_RND" TP_25MIL-SMT 1960,1610 r0 top (schematic designator TP22)
TP21 "TP-040_RND" TP_25MIL-SMT 1960,1690 r0 top (schematic designator TP23)
TP22 "TP-040_RND" TP_25MIL-SMT 2020,1610 r0 top (schematic designator TP24)
TP23 "TP-040_RND" TP_25MIL-SMT 2080,1610 r0 top (schematic designator TP28)
TP24 "TP-040_RND" TP_25MIL-SMT 2020,1690 r0 top (schematic designator TP30)
TP25 "TP-040_RND" TP_25MIL-SMT 2080,1690 r0 top (schematic designator TP31)
TP26 "TP-040_RND" TP_25MIL-SMT 2140,1685 r0 top (schematic designator TP32)
TP27 "TP-040_RND" TP_25MIL-SMT 3177,1685 r0 top (schematic designator TP47)
TP28 "TP-040_RND" TP_25MIL-SMT 3119,1685 r0 top (schematic designator TP48)
TP29 "TP1_PD40_D0.5_S50" TP1_PD40_D0.5_S50 3967,1560 r90 top (schematic designator TP16)
TP30 "TP-040_RND" TP-040_RND 5308,1524 r90 top (schematic designator TP43)
TP31 "TP-040_RND" TP_25MIL-SMT 1890,1475 r0 top
TP32 "TP-040_RND" TP_25MIL-SMT 1890,1410 r0 top
TP33 "TP-040_RND" TP-040_RND 1103,1408 r90 top (schematic designator TP4)
TP34 "TP-040_RND" TP_25MIL-SMT 1890,1340 r0 top
TP35 "TP-040_RND" TP_25MIL-SMT 2080,1305 r0 top
TP36 "TP-040_RND" TP_25MIL-SMT 1950,1475 r0 top (schematic designator TP3)
TP37 "TP-040_RND" TP_25MIL-SMT 2010,1475 r0 top (schematic designator TP4)
TP38 "TP-040_RND" TP_25MIL-SMT 2070,1475 r0 top (schematic designator TP17)
TP39 "TP-040_RND" TP_25MIL-SMT 2030,1235 r0 top
TP40 "TP-040_RND" TP_25MIL-SMT 1960,1305 r0 top (schematic designator TP6)
TP41 "TP-040_RND" TP_25MIL-SMT 2080,1235 r0 top
TP42 "TP-040_RND" TP_25MIL-SMT 2135,1235 r0 top
TP43 "TP-040_RND" TP_25MIL-SMT 2020,1305 r0 top
TP44 "TP-040_RND" TP_25MIL-SMT 3200,1295 r0 top (schematic designator TP46)
TP45 "TP-040_RND" TP_25MIL-SMT 3260,1295 r0 top (schematic designator TP36)
TP46 "TP-040_RND" TP-040_RND 5825,1174 r90 top (schematic designator TP40)
TP47 "TP1_PD40_D0.5_S50" TP1_PD40_D0.5_S50 3967,955 r0 top (schematic designator TP2)
TP48 "TP-040_RND" TP-040_RND 4981,869 r0 top (schematic designator TP41)
TP49 "TP-040_RND" TP-040_RND 5090,869 r90 top (schematic designator TP26)
TP50 "TP-040_RND" TP-040_RND 5051,695 r90 top (schematic designator TP37)
TP51 "TP-040_RND" TP-040_RND 4924,373 r90 top (schematic designator TP39)
TP52 "TP-040_RND" TP_25MIL-SMT 2939,1299 r90 bottom (schematic designator TP20)
TP53 "TP-040_RND" TP_25MIL-SMT 2506,1222 r90 bottom (schematic designator TP21)
TP54 "TP-040_RND" TP-040_RND 148,1851 r90 top
U1 "TPL7407LPW" PW0016A_N 2104,2455 r180 top (schematic designator U9)
U2 "XTR300AIRGWR" RGW20 5209.15,2314.95 r0 top (schematic designator U10)
U3 "TPS7A6533QKVURQ1" KVU_1 789,1798 r270 top
U4 "ISO7341FCDWR" DW0016B_N 4427.01,1725 r0 top (schematic designator U6)
U5 "DAC8563DGS" DGS0010A_N 5318,1723 r180 top (schematic designator U8)
U6 "MSP430F67661A" QFP50P1600X2200X160-128N 2535,1500 r180 top (schematic designator U4)
U7 "XTR300AIRGWR" RGW20 5266,1144 r0 top
U8 "ISO7341FCDWR" DW0016B_N 4427,1125 r0 top (schematic designator U1)
U9 "TPS7A4201DGN" DGN_8P 5082,541 r0 top (schematic designator U5)
Y1 "CMR200T-32.768KDZBT" XTAL_CMR200T 3205,1110 r0 top
ZZ1 "This Assembly Note is for PCB labels only" AssemblyNoteLabel 378,3870 r0 top
ZZ2 "These assemblies are ESD sensitive, ESD precautions shall be observed." AssemblyNote 383,3755 r0 top
ZZ3 "These assemblies must be clean and free from flux and all contaminants. Use of no clean flux is not acceptable." AssemblyNote 385,3656 r0 top
ZZ4 "These assemblies must comply with workmanship standards IPC-A-610 Class 2, unless otherwise specified." AssemblyNote 386,3544 r0 top

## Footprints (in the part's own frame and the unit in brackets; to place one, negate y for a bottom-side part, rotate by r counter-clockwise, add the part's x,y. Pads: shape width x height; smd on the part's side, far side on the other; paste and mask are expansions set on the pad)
3M_N2514-6002-RB [mm] "CONN, HEADER, 14 POS, STRGHT GOLD"
  rect 1.4x1.4 / inner round 1.4 / far side rect 1.4x1.4 hole 0.889 mask+0.064: 1(-7.62,-1.27)
  round 1.4 hole 0.889 mask+0.064: 2(-7.62,1.27) 3(-5.08,-1.27) 4(-5.08,1.27) 5(-2.54,-1.27) 6(-2.54,1.27) 7(0,-1.27) 8(0,1.27) 9(2.54,-1.27) 10(2.54,1.27) 11(5.08,-1.27) 12(5.08,1.27) 13(7.62,-1.27) 14(7.62,1.27)
  round 0.889 hole 0.889 unplated mask+0.127: ""(-11.99,0)
  Multi-Layer keep-out circle w0.025: c-11.99,0 r1.206
  silkscreen extent -12.55,-5.49 12.55,4.52, body extent -12.55,-4.07 12.55,4.52, height 9.91
0603 [mm] "0603 from SM-752 data"
  rect 1x0.95 smd mask+0.064: 1(-0.8,0) 2(0.8,0)
  silkscreen extent -1.52,-0.69 1.52,0.69, body extent -0.87,-0.47 0.87,0.47, height 0.85
0805_HV [mil] "0805 with 30mil clearance between pads"
  rect 50x63 smd mask+2.5: 1(-40,0) 2(40,0)
  silkscreen extent -74,-40 74,40, body extent -43,-29 43,29, height 43
1206 [mm] "1206 from SM-752 data"
  rect 1.3x1.85 smd mask+0.064: 1(-1.45,0) 2(1.45,0)
  silkscreen extent -2.4,-1.21 2.4,1.21, body extent -1.7,-0.9 1.7,0.9, height 1.35
1210 [mm] "1210 from SM-752 data"
  rect 1.3x2.7 smd mask+0.064: 1(-1.45,0) 2(1.45,0)
  silkscreen extent -2.32,-1.57 2.32,1.57, body extent -1.7,-1.35 1.7,1.35, height 1.35
6032-28 [mm] "Medium Density IPC based on Vishay Sprague 293D datasheet."
  rect 2.55x2.3 smd mask+0.064: 1(-2.375,0) 2(2.375,0)
  silkscreen extent -3.2,-1.75 3.2,1.75, body extent -3.15,-1.75 3.15,1.75, height 2.8
AssemblyNote [mil] "Assembly Note"
AssemblyNoteLabel [mil] "Assembly Note for PCB Labels"
CONN_1725711 [mm] "Phoenix Contact"
  rect 1.78x1.78 hole 1.1 mask+0.064: 1(-8.89,0)
  round 1.78 hole 1.1 mask+0.064: 2(-6.35,0) 3(-3.81,0) 4(-1.27,0) 5(1.27,0) 6(3.81,0) 7(6.35,0) 8(8.89,0)
  silkscreen extent -10.49,-3.6 10.4,3.94, body extent -10.39,-3.1 10.39,3.1, height 8.52
CONN_ED120-2DS [mm] "ONSHORE"
  rect 1.75x1.75 hole 1.25 mask+0.064: 1(0,-2.54)
  round 1.75 hole 1.25 mask+0.064: 2(0,2.54)
  silkscreen extent -5,-5.6 4,5.12, body extent -5,-5.6 4.15,5.12, height 13.1
DGN_8P [mil]
  rect 40x17 smd mask+2.5: 1(-82.1,40) 2(-82.1,14.4) 3(-82.1,-11.2) 4(-82.1,-36.8) 5(82.9,-36.9) 6(82.9,-11.3) 7(82.9,14.3) 8(82.9,40)
  rect 80x80 smd mask+2.5: 9(0.2,1.4)
  silkscreen extent -117,54 -92,79
DGS0010A_N [mm] "TSSOP, 10-Leads, Body 3x3mm, Pitch 0.5mm, IPC Medium Density"
  oval 1.7x0.3 smd mask+0.064: 1(-2.05,1) 2(-2.05,0.5) 3(-2.05,0) 4(-2.05,-0.5) 5(-2.05,-1) 6(2.05,-1) 7(2.05,-0.5) 8(2.05,0) 9(2.05,0.5) 10(2.05,1)
  silkscreen extent -0.9,-1.55 0.9,1.55, body extent -2.45,-1.5 2.45,1.5, height 0.94
DIO_SMB_BIAAAA [mm]
  rect 2.5x2.3 smd mask+0.064: 1(-2.15,0) 2(2.15,0)
  silkscreen extent -5.41,-1.97 2.29,1.97
DIO_SOD-123 [mm] "DIODE, SCHOTTKY, SOD-123"
  rect 1x0.8 smd mask+0.064: 1(-1.8,0) 2(1.8,0)
  Top Layer keep-out region: -0.762,0.8 0.762,0.8 0.762,-0.8 -0.762,-0.8
  silkscreen extent -2.79,-0.8 1.35,0.8, body extent -1.35,-0.8 1.35,0.8, height 1.35
DW0016B_N [mm] "SOP, 16-Leads, Body 10.5x7.6mm (max), Pitch 1.27mm, IPC Medium Density"
  rect 2.3x0.6 smd mask+0.064: 1(-4.55,4.445) 2(-4.55,3.175) 3(-4.55,1.905) 4(-4.55,0.635) 5(-4.55,-0.635) 6(-4.55,-1.905) 7(-4.55,-3.175) 8(-4.55,-4.445) 9(4.55,-4.445) 10(4.55,-3.175) 11(4.55,-1.905) 12(4.55,-0.635) 13(4.55,0.635) 14(4.55,1.905) 15(4.55,3.175) 16(4.55,4.445)
  silkscreen extent -5.5,-5.25 3,5.25, body extent -3.8,-5.25 3.8,5.25, height 2.66
Fiducial10-20#1 [mm]
  round 1 smd paste+0 mask+0.5: 1(0,0)
  Top Layer keep-out circle w1.178: c0,0 r0.5
Fiducial10-20#2 [mm]
  round 1 smd mask+0.5: 1(0,0)
  Top Layer keep-out circle w1.178: c0,0 r0.5
HDR1X3 [mil] "HDR1X3"
  rect 60x60 / inner round 60 / far side rect 60x60 hole 40 mask+2.5: 1(0,100)
  round 60 hole 40 mask+2.5: 2(0,0) 3(0,-100)
  silkscreen extent -88,-150 50,150, body extent -50,-150 50,150, height 1
Keystone_1902C#1 [mil] "Hex Standoff, 4-40 threaded, nylon"
  round 1 on Mech4 mask+2.5: 0(0,0)
  body extent -145,-126 146,126, height 501
Keystone_1902C#2 [mil] "Hex Standoff, 4-40 threaded, nylon"
  round 1 on Mech3 mask+2.5: 0(0,0)
  body extent -145,-126 146,126, height 501
KVU_1 [mm]
  rect 1.2x2.8 smd mask+0.064: 1(-2.29,-3.635) 3(2.29,-3.635)
  rect 6.096x6.096 smd mask+0.064: 2(0,3.635)
  silkscreen extent -4.19,-5.84 3.43,7.22
Label_650x200 [mil] "Thermal Transfer Label"
  round 1 on Mech14 mask+2.5: 0(0,0)
  silkscreen extent -325,-100 325,100, body extent -326,-101 326,101, height 1
LED0603AA [mil]
  rect 32x32 smd mask+2.5: 1(-32.48,0) 2(32.48,0)
  silkscreen extent -50,-16 29,91
LED_5MM [mm] "LED, 5MM, RED, TH"
  rect 1.54x1.54 / inner round 1.54 / far side rect 1.54x1.54 hole 1.04 mask+0.064: 1(1.27,0)
  round 1.54 hole 1.04 mask+0.064: 2(-1.27,0)
  silkscreen extent -2.9,-2.9 2.9,4.5, body extent -2.9,-2.9 2.9,2.9, height 9
"NY PMS 440 0025 PH"#1 [mm] "4-40 nylon screw and mounting hole"
  round 8 hole 3.2 mask+0.064: 1(0.004,0.205)
  body extent -2.8,-2.8 3.8,3.8, height 2.69
"NY PMS 440 0025 PH"#2 [mm] "4-40 nylon screw and mounting hole"
  round 8 hole 3.2 mask+0.064: 1(-2.473,-0.786)
  body extent -5.7,-3.9 0.89,2.71, height 2.69
"NY PMS 440 0025 PH"#3 [mm] "4-40 nylon screw and mounting hole"
  round 8 hole 3.2 mask+0.064: 1(0.021,-0.172)
  body extent -3.3,-3.3 3.3,3.3, height 2.69
"NY PMS 440 0025 PH"#4 [mm] "4-40 nylon screw and mounting hole"
  round 8 hole 3.2 mask+0.064: 1(0,0)
  body extent -2.8,-2.8 3.8,3.8, height 2.69
"NY PMS 440 0025 PH"#5 [mm] "4-40 nylon screw and mounting hole"
  round 8 hole 3.2 mask+0.064: 1(-1.431,-0.686)
  body extent -4.79,-4.03 1.81,2.58, height 2.69
PW0016A_N [mm] "TSOP, 16-Leads, Body 5x4.4mm, Pitch 0.65mm, IPC Medium Density"
  oval 1.7x0.35 smd mask+0.064: 1(-2.85,2.275) 2(-2.85,1.625) 3(-2.85,0.975) 4(-2.85,0.325) 5(-2.85,-0.325) 6(-2.85,-0.975) 7(-2.85,-1.625) 8(-2.85,-2.275) 9(2.85,-2.275) 10(2.85,-1.625) 11(2.85,-0.975) 12(2.85,-0.325) 13(2.85,0.325) 14(2.85,0.975) 15(2.85,1.625) 16(2.85,2.275)
  silkscreen extent -3.88,-2.55 1.5,2.77, body extent -3.21,-2.5 3.21,2.5, height 0.98
QFP50P1600X2200X160-128N [mm] "IC, 0.5MM PITCH, QFP-128P"
  rect 1.5x0.3 smd mask+0.058: 1(-7.7,9.25) 2(-7.7,8.75) 3(-7.7,8.25) 4(-7.7,7.75) 5(-7.7,7.25) 6(-7.7,6.75) 7(-7.7,6.25) 8(-7.7,5.75) 9(-7.7,5.25) 10(-7.7,4.75) 11(-7.7,4.25) 12(-7.7,3.75) 13(-7.7,3.25) 14(-7.7,2.75) 15(-7.7,2.25) 16(-7.7,1.75) 17(-7.7,1.25) 18(-7.7,0.75) 19(-7.7,0.25) 20(-7.7,-0.25) 21(-7.7,-0.75) 22(-7.7,-1.25) 23(-7.7,-1.75) 24(-7.7,-2.25) 25(-7.7,-2.75) 26(-7.7,-3.25) 27(-7.7,-3.75) 28(-7.7,-4.25) 29(-7.7,-4.75) 30(-7.7,-5.25) 31(-7.7,-5.75) 32(-7.7,-6.25) 33(-7.7,-6.75) 34(-7.7,-7.25) 35(-7.7,-7.75) 36(-7.7,-8.25) 37(-7.7,-8.75) 38(-7.7,-9.25) 65(7.7,-9.25) 66(7.7,-8.75) 67(7.7,-8.25) 68(7.7,-7.75) 69(7.7,-7.25) 70(7.7,-6.75) 71(7.7,-6.25) 72(7.7,-5.75) 73(7.7,-5.25) 74(7.7,-4.75) 75(7.7,-4.25) 76(7.7,-3.75) 77(7.7,-3.25) 78(7.7,-2.75) 79(7.7,-2.25) 80(7.7,-1.75) 81(7.7,-1.25) 82(7.7,-0.75) 83(7.7,-0.25) 84(7.7,0.25) 85(7.7,0.75) 86(7.7,1.25) 87(7.7,1.75) 88(7.7,2.25) 89(7.7,2.75) 90(7.7,3.25) 91(7.7,3.75) 92(7.7,4.25) 93(7.7,4.75) 94(7.7,5.25) 95(7.7,5.75) 96(7.7,6.25) 97(7.7,6.75) 98(7.7,7.25) 99(7.7,7.75) 100(7.7,8.25) 101(7.7,8.75) 102(7.7,9.25)
  rect 0.3x1.5 smd mask+0.058: 39(-6.25,-10.7) 40(-5.75,-10.7) 41(-5.25,-10.7) 42(-4.75,-10.7) 43(-4.25,-10.7) 44(-3.75,-10.7) 45(-3.25,-10.7) 46(-2.75,-10.7) 47(-2.25,-10.7) 48(-1.75,-10.7) 49(-1.25,-10.7) 50(-0.75,-10.7) 51(-0.25,-10.7) 52(0.25,-10.7) 53(0.75,-10.7) 54(1.25,-10.7) 55(1.75,-10.7) 56(2.25,-10.7) 57(2.75,-10.7) 58(3.25,-10.7) 59(3.75,-10.7) 60(4.25,-10.7) 61(4.75,-10.7) 62(5.25,-10.7) 63(5.75,-10.7) 64(6.25,-10.7) 103(6.25,10.7) 104(5.75,10.7) 105(5.25,10.7) 106(4.75,10.7) 107(4.25,10.7) 108(3.75,10.7) 109(3.25,10.7) 110(2.75,10.7) 111(2.25,10.7) 112(1.75,10.7) 113(1.25,10.7) 114(0.75,10.7) 115(0.25,10.7) 116(-0.25,10.7) 117(-0.75,10.7) 118(-1.25,10.7) 119(-1.75,10.7) 120(-2.25,10.7) 121(-2.75,10.7) 122(-3.25,10.7) 123(-3.75,10.7) 124(-4.25,10.7) 125(-4.75,10.7) 126(-5.25,10.7) 127(-5.75,10.7) 128(-6.25,10.7)
  silkscreen extent -9.46,-9.6 6.6,9.6, body extent -7,-10 7,10, height 1.6
RGW20 [mil]
  rect 32x15 smd mask+2.5: 1(-88,51.2) 2(-88,25.6) 3(-88,0) 4(-88,-25.6) 5(-88,-51.2) 11(88,-51.2) 12(88,-25.6) 13(88,0) 14(88,25.6) 15(88,51.2)
  rect 15x32 smd mask+2.5: 6(-51.2,-88.1) 7(-25.6,-88.1) 8(0,-88.1) 9(25.6,-88.1) 10(51.2,-88.1) 16(51.2,87.9) 17(25.6,87.9) 18(0,87.9) 19(-25.6,87.9) 20(-51.2,87.9)
  rect 120x120 smd mask+2.5: 21(0.15,-0.05)
  silkscreen extent -142,50 -117,75
SMB [mil] "Molded Diode, 2-Leads, Body 5.4x3.6mm, IPC Medium Density, based on OnSemi component dimensions"
  rect 85x107.99 smd mask+2.5: 1(-87.01,0) 2(87.01,0)
  silkscreen extent -155,-82 125,82, body extent -106,-71 106,71, height 91
sod-123 [mm] "On Semi recommended land pattern"
  rect 0.915x1.22 smd mask+0.064: 1(-1.637,0) 2(1.637,0)
  silkscreen extent -2.74,-1.17 2.03,1.17, body extent -1.93,-0.9 1.93,0.9, height 1.35
SOD-123 [mm] "On Semi recommended land pattern"
  rect 0.915x1.22 smd mask+0.064: 1(-1.637,0) 2(1.637,0)
  silkscreen extent -2.74,-1.17 2.03,1.17, body extent -1.93,-0.9 1.93,0.9, height 1.35
SON_CSD17571Q2 [mm] "SON, MOSFET, N-CH, 30V, 22A, SON 2X2 MM"
  rect 0.4x0.455 smd mask+0.032: 1(-0.65,-0.923) 2(0,-0.923) 5(0,0.923) 6(-0.65,0.923)
  rect 0.4x0.455 smd mask+0.064: 3(0.65,-0.923) 4(0.65,0.923)
  rect 0.4x0.85 smd mask+0.038: 7(0.65,0.096)
  rect 1.05x1.1 smd mask+0.032: 8(-0.325,0)
  silkscreen extent -1.1,-2.08 1.1,1, body extent -1,-1 1,0.97, height 0.85
SOT-323 [mm] "Zetex recommended land pattern.  March 2007"
  rect 0.8x0.6 smd mask+0.064: 1(-0.8,0.65) 2(-0.8,-0.65) 3(0.8,0)
  silkscreen extent -1.14,-1.22 1.09,1.49, body extent -1.13,-1.13 1.12,1.12, height 1.13
SW_7914G-1-000E [mm] "BOURNS"
  rect 1.27x1.27 smd mask+0.064: 1(-1.27,2.75) 2(-1.27,-2.75) 3(1.27,-2.75) 4(1.27,2.75)
  silkscreen extent -2.5,-3.2 2.5,3.2, body extent -2.25,-2.5 2.25,2.5, height 4.49
TEC_282834-4 [mm] "TEC"
  rect 1.6x1.6 hole 1.1 mask+0.064: 1(-3.81,0)
  round 1.6 hole 1.1 mask+0.064: 2(-1.27,0) 3(1.27,0) 4(3.81,0)
  silkscreen extent -6.2,-3.4 5.44,3.4, body extent -5.31,-3.25 5.31,3.25, height 10.02
TI_Stacked_Overlay_Small [mil]
  silkscreen extent -418,-98 418,98
TP1_PD40_D0.5_S50 [mil]
  round 30 hole 16 mask+2.5: 1(0,0)
  silkscreen extent -25,-25 25,25
TP-040_RND [mil]
  round 70 / inner round 62 / far side round 62 hole 40 mask+2.5: 1(0,0)
TP_25MIL-SMT [mil] "SMT, TESTPOINT"
  round 25 smd mask+2.5: 1(0,0)
  silkscreen extent -21,-21 21,21, body extent -16,-16 16,16, height 2
TSW-108-07-G-D [mm] "Samtec 100mil, 2x8, 230 mil above insulator"
  rect 1.65x1.65 hole 1.016 mask+0.064: 1(-8.89,-1.27)
  round 1.65 hole 1.016 mask+0.064: 2(-8.89,1.27) 3(-6.35,-1.27) 4(-6.35,1.27) 5(-3.81,-1.27) 6(-3.81,1.27) 7(-1.27,-1.27) 8(-1.27,1.27) 9(1.27,-1.27) 10(1.27,1.27) 11(3.81,-1.27) 12(3.81,1.27) 13(6.35,-1.27) 14(6.35,1.27) 15(8.89,-1.27) 16(8.89,1.27)
  silkscreen extent -11.19,-2.54 10.16,2.54, body extent -10.16,-2.54 10.16,2.54, height 8.38
XFMR_AP-2500 [mil] "TRANSFORMER, TH"
  rect 53.31x53.31 / inner round 53.31 / far side rect 53.31x53.31 hole 33.62 mask+2.5: 1(-250,0)
  round 53.31 hole 33.62 mask+2.5: 3(250,0)
  silkscreen extent -339,-188 339,188, body extent -339,-188 339,188, height 803
XTAL_CMR200T [mm] "XTAL, SMD, 3-PIN"
  rect 2.5x1 smd mask+0.064: 1(-5,1.25) 2(-5,-1.25)
  rect 2.5x2.5 smd mask+0.064: 3(2.75,0)
  Top Layer keep-out region: -3.048,-0.946 1.272,-0.946 1.272,0.954 -3.048,0.954
  silkscreen extent -3,-0.95 1.13,0.95, body extent -3,-0.95 3,0.95, height 2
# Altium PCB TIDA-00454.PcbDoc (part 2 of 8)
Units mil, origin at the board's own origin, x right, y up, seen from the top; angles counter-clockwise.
Board outline 6159 x 2859 mil, 2 copper layers (Top Layer, Bottom Layer), stack 62 mil thick; 328 components, 224 nets, 884 pads, 184 vias.

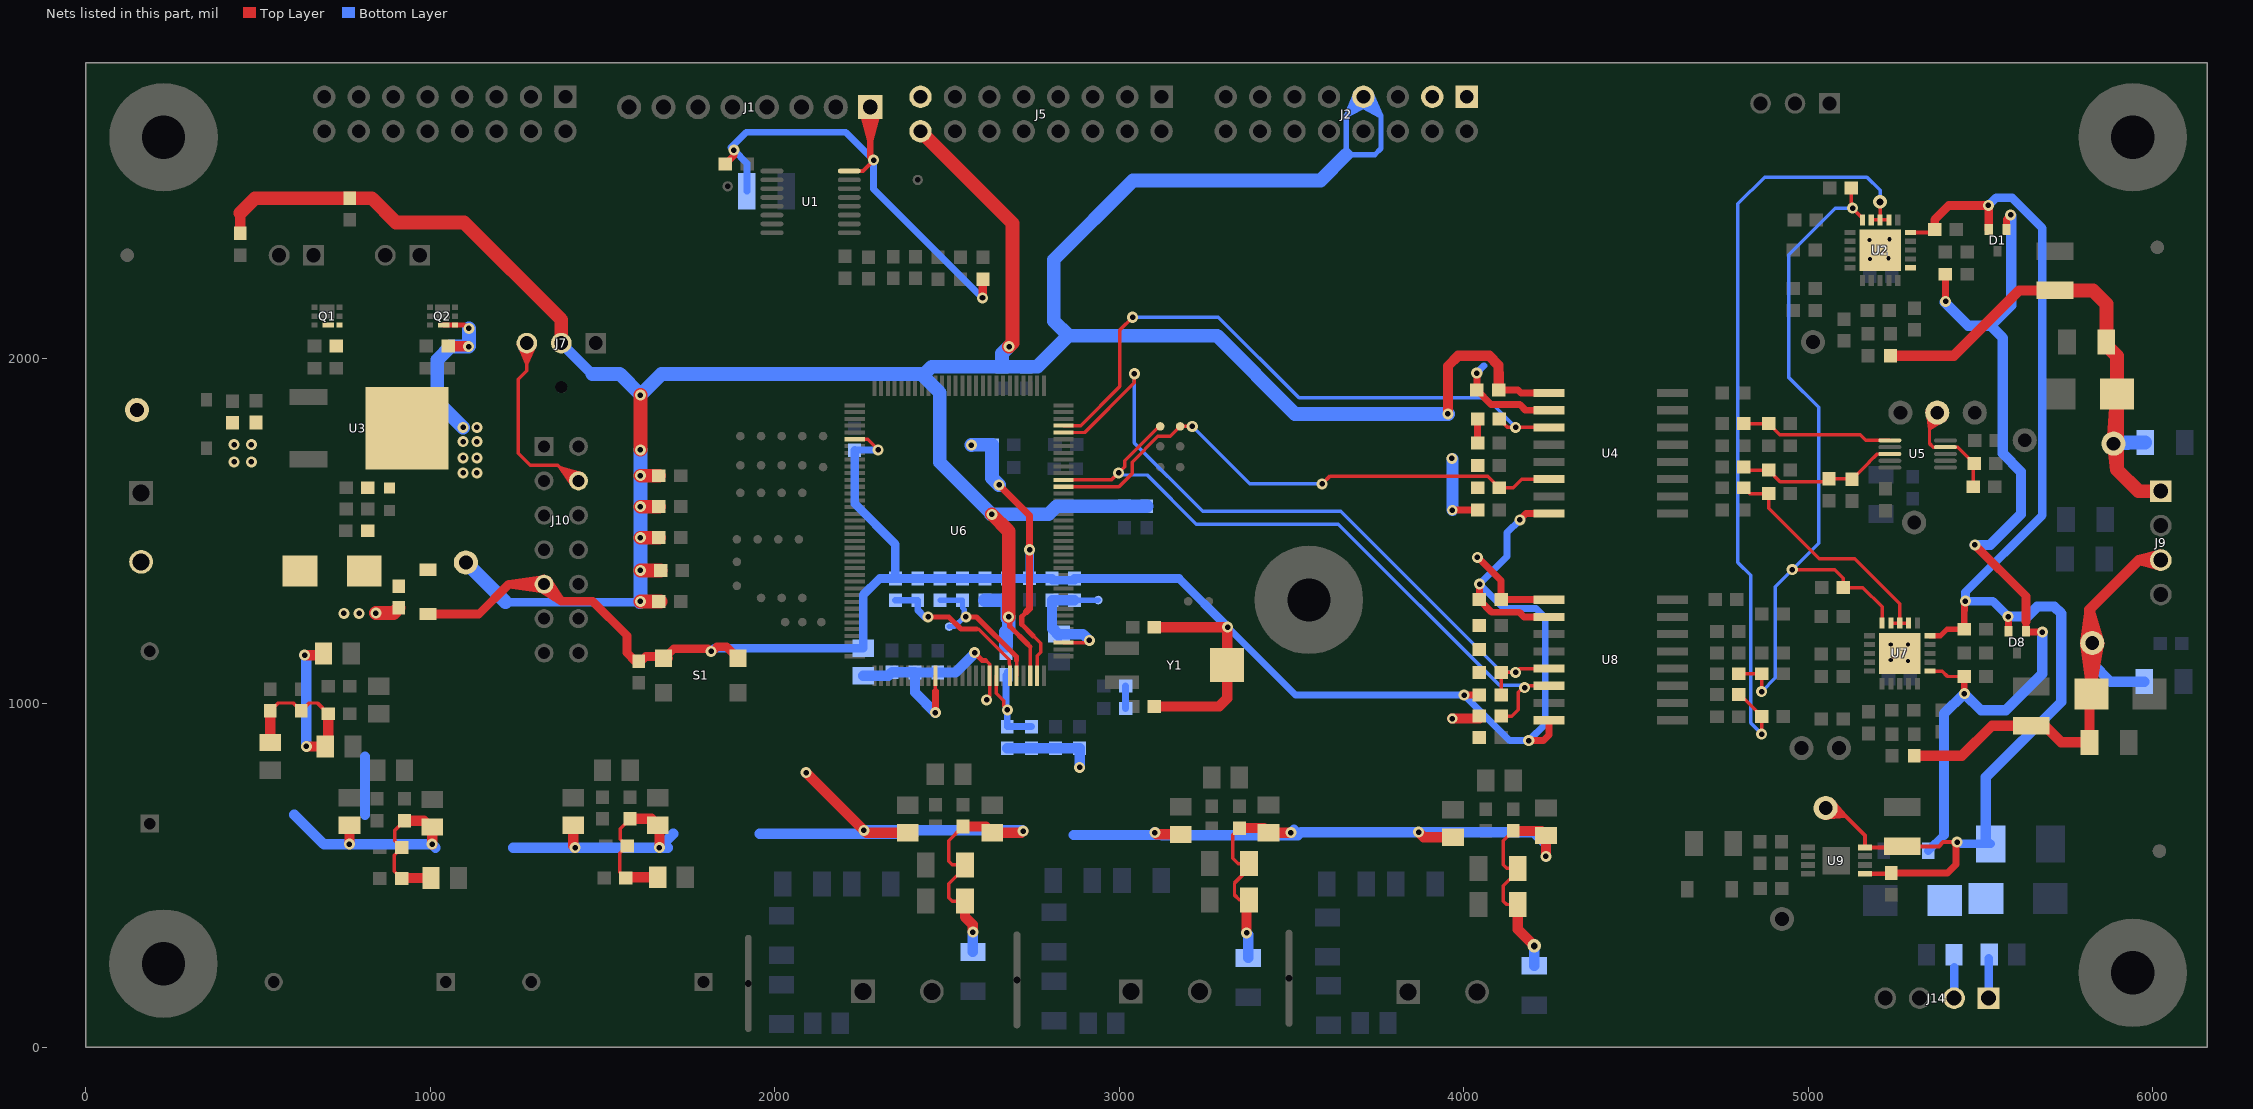
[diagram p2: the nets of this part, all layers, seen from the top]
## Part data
C1 C2 C3 C8 C10 C11 C15 C17 C20 C23 C25 C51: "CAP, CERM, 0.1uF, 50V, +/-10%, X7R, 0603"
C4 C5 C19 C48 C52 C55 C57 C59 C64 C65 C66 C67 C68: "CAP, CERM, 0.1uF, 25V, +/-5%, X7R, 0603"
C6 C26 C43: "CAP, CERM, 0.01uF, 50V, +/-5%, X7R, 0603"
C7 C12: "CAP, CERM, 1uF, 16V, +/-10%, X7R, 0603"
C9 C27 C49 C62: "CAP, CERM, 1000pF, 2KV 10% X7R 1206"
C13: "CAP, CERM, 0.022uF, 16V, +/-10%, X7R, 0603"
C14: "CAP, TA, 4.7uF, 35V, +/-10%, 1.9 ohm, SMD"
C16 C22: "CAP, CERM, 12pF, 50V, +/-5%, C0G/NP0, 0603"
C18 C24 C33 C34 C35 C36 C37 C38 C39 C40 C41 C42: "CAP, CERM, 47pF, 500V, +/-5%, C0G/NP0, 0805"
C21 C28 C29 C30 C31 C32: "CAP, CERM, 0.015uF, 50V, +/-10%, X7R, 0805"
C44 C46: "CAP, CERM, 10uF, 50V, +/-10%, X7R, 1210"
C45: "CAP, CERM, 10uF, 16V, +/-10%, X7R, 1206"
C47 C71: "CAP, CERM, 0.047uF, 50V, +/-10%, X7R, 0603"
C50: "CAP, CERM, 4.7uF, 16V, +/-10%, X7R, 1206"
C53 C54: library part 0603ZD475KAT2A, "RES 0.0 OHM 1/10W JUMP 0603 SMD"
C56 C60: library part GRM188R71E474KA12D, "CAP, CERM, 0.47uF, 25V, +/-10%, X7R, 0603"
C58 C61 C63 C69 C70: "CAP, CERM, 4.7uF, 10V, +/-10%, X5R, 0603"
C72: "CAP, TA, 10uF, 25V, +/-10%, 1.5 ohm, SMD"
C73: "CAP, TA, 10uF, 25V, +/-10%, 0.3 ohm, SMD"
C74 C75: "CAP, CERM, 22uF, 16V, +/-20%, X5R, 0805"
D1 D8: library part BAV99WT1G, "Diode, P-N, 70V, 0.2A, SOT-323"
D2 D3: "LED, 5MM, RED, TH"
D4 D9: "TVS 18 VOLT 600 WATT BI-DIR SMB"
D5: "DIODE, SCHOTTKY, 20V, 500 mA, SOD123, SMT"
D6: "LED SmartLED Green 570NM"
D7: library part 1SMB5915BT3G, "DIODE ZENER 3.9V 500MW SOD123"
D10: "Diode, Zener, 5.6 V, 500 mW, SOD-123"
D11: library part SL43-E3/57T, "DIODE ZENER 15V 2W D0214AA"
D12: library part SL43-E3/57T, "DIODE ZENER 15V 500MW SOD123"
FB1 FB3: library part Ferrite_Bead, "BEAD FERRITE 500 OHM 3.0A 3216"
FB2 FB4: library part MMZ1608B102C, "FERRITE CHIP 1000 OHM 300MA 0603"
FID1 FID2 FID3 FID4 FID5 FID6: "Fiducial mark.  There is nothing to buy or mount."
H1 H3 H5 H7 H10: "Standoff, Hex, 0.5\"L #4-40 Nylon"
H2 H4 H6 H8 H9: "Machine Screw, Round, #4-40 x 1/4, Nylon, Philips panhead"
J1: "Terminal Block, 8x1, 2.54 mm, TH"
J2 J4 J5: library part PBC08DBAN, "Header, 8x2, 100mil, TH"
J3 J7: library part 009155003301006, "3 pin berger"
J8 J11 J12 J13: "TERMINAL BLOCK 5.08MM VERT 2POS, TH"
J9 J14: "Receptacle, 100mil, 4X1 TH"
J10: library part 0015912140, "Header, 7x2, 100mil, SMT"
LBL1: library part THT-14-423-10, "Thermal Transfer Printable Labels, 0.650\" W x 0.200\" H - 10,000 per roll"
Logo2: library part TI_Logo, "Texas Instrument Corporate Signature"
Q1 Q2: "MOSFET, N-CH, 30V, 22A, SON 2X2 MM"
R1 R4: "RES, 330 ohm, 5%, 0.1W, 0603"
R2 R3 R39 R43 R47 R91: "RES, 100k ohm, 1%, 0.1W, 0603"
R5 R6 R7 R8 R9 R10 R11: "RES, 1.00k ohm, 1%, 0.1W, 0603"
R12 R14 R63 R64: "RES, 1.02k ohm, 0.1%, 0.1W, 0603"
R13 R57: library part CRCW080515R0FKEA, "RES, 15.0 ohm, 1%, 0.125W, 0805"
R15 R16 R70 R71: library part RC0603FR-075K1L, "RES, 5.10k ohm, 1%, 0.1W, 0603"
R17 R65: "RES, 8.25k ohm, 0.1%, 0.1W, 0603"
R18 R19 R33: "RES, 300 ohm, 5%, 0.1W, 0603"
R20 R21 R69 R74: "RES, 750 ohm, 1%, 0.1W, 0603"
R22 R24 R27 R28 R30 R31 R37 R38 R45 R46 R48 R49 R52 R53 R56 R60 R61 R68: library part RG1608P-103-B-T5, "RES, 10.0k ohm, 1%, 0.1W, 0603"
R23 R25 R29 R35 R36 R50 R54 R55 R62 R67 R72 R73 R132: library part RC0402JR-070RL, "RES, 0 ohm,5%, 0.1W, 0603"
R26 R34 R41 R42: library part RNCF0603TKY10K0, "RES 10K OHM 1/10W 5% 0603 SMD"
R32 R40 R133: "RES, 10.0k ohm, 1%, 0.1W, 0603"
R44: "RES, 47k ohm, 5%, 0.1W, 0603"
R51 R66 R75 R76 R77 R78 R79 R80 R81 R82 R83 R84: library part RC0603JR-071KL, "RES, 1.0k ohm, 5%, 0.1W, 0603"
R58 R59 R85 R86 R92 R93: "RES, 100 ohm, 1%, 0.1W, 0603"
R87 R88 R89 R94 R95 R96: "RES, 2.40 k, 1%, 0.25 W, 1206"
R90: "RES, 11.0k ohm, 1%, 0.1W, 0603"
R97: "RES, 3.00k ohm, 1%, 0.1W, 0603"
R98 R99 R104 R105: "RES, 2.2k ohm, 5%, 0.1W, 0603"
R100 R101 R103: library part CRCW06032K20JNEA, "RES 560K OHM 1/10W 1% 0603 SMD"
R102: library part CRCW08050000Z0EA, "RES 0.0 OHM 1/10W JUMP 0603 SMD"
R106 R107: library part RC0402JR-070RL, "RES, 0 ohm,5%, 0.25W, 1206"
R108 R109 R121 R123 R125 R127 R129 R131: library part CRCW0805330KJNEA, "RES, 0 ohm, 5%, 0.125W, 0805"
R111 R112 R113 R114 R115 R116 R117 R118 R119 R122 R124 R126: "RES, 332 k, 1%, 0.25 W, 1206"
R120 R128 R130: "RES, 0, 5%, 0.25 W, 1206"
S1: "Switch, Tactile, SPST-NO, 0.1A, 16V, SMT"
T1 T2 T3: "TRANSFORMER, PRECISE CURRENT, 15 A, 330 OHM, TH"
TP1 TP2: "Test Point 40mil pad 20mil drill"
TP3 TP4 TP5 TP6 TP8 TP9 TP30 TP31 TP32 TP33 TP34 TP39 TP40 TP41 TP42 TP43 TP46 TP48 TP49 TP50 TP51 TP52 TP53 TP54: "Test Point, O.040 Hole"
TP7 TP10 TP11 TP12 TP13 TP14 TP15 TP16 TP17 TP18 TP19 TP20 TP21 TP22 TP23 TP24 TP25 TP26 TP27 TP28 TP35 TP36 TP37 TP38 TP44 TP45: "Test Point, SMT 25mil"
TP29 TP47: library part TP-040_RND, "Test Point 40mil pad 20mil drill"
U1: "40V 7-Channel Low Side Driver, PW0016A"
U2 U7: "IC, Industrial Analog Current/Voltage Output Driver"
U3: "IC, 300-mA 40-V LOW-DROPOUT REGULATOR WITH 25-uA QUIESCENT CURRENT"
U4 U8: "Robust EMC, Low Power, Quad-Channel Digital Isolators, DW0016B"
U5: "DUAL 16-/14-/12-BIT, ULTRALOW-GLITCH, LOW-POWER, BUFFERED, VOLTAGE-OUTPUT DAC WITH 2.5-V, 4-PPM/°C INTERNAL REFERENCE IN SMALL 3-MM ?3-MM SON, DGS0010A"
U6: library part MSP430F6779IPEU, "IC, MCU 16BIT 512KB FLASH, LQFP-128"
U9: "IC, 28-V Input Voltage, 50-mA Voltage Regulator"
Y1: "CRYSTAL, 32.768KHz, 6PF, +/- 20PPM, SMD-3P"
ZZ1: library part AssemblyNoteLabel
ZZ2 ZZ3 ZZ4: library part AssemblyNote

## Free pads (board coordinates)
  oval 20x282 hole 20 slot 282 at 90 deg unplated mask+5: 3(1923,186) 3(2703,196) 3(3493,201)

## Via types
v1: diameter 32, hole 16, Top Layer to Bottom Layer, tented both sides, 168 vias
v2: diameter 40, hole 20, Top Layer to Bottom Layer, tented both sides, 8 vias
v3: diameter 24, hole 12, Top Layer to Bottom Layer, tented both sides, 8 vias

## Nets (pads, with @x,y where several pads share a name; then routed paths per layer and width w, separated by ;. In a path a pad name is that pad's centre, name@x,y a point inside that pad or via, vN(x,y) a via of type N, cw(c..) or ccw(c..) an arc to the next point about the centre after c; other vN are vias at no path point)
+15V: C2.1 C17.1 C44.1 C73.1 C75.1 D1.2 D8.2 D11.1 J14.1 R91.2 TP50.1 U2.15 U7.15 U9.5 U9.8 | length 4433.4
  Top Layer w12: TP50.1@5046.6,666.34 5108.5,671.5 ; TP50.1@5046.78,678.53 5108.5,671.5 ; TP50.1@5059.52,709.71 5108.5,671.5 ; TP50.1@5067.93,718.54 5108.5,671.5 ; U9.5@5164.9,504.1 R91.2@5241.4,504.1 ; R91.2@5241.5,504 R91.2@5241.4,504.1 ; R91.2@5248,510.7 5243.8,506.5 R91.2@5241.4,504.1 ; U2.15@5297.15,2366.15 5358.65,2366.15 C2.1@5367.5,2375 ; 5433,535 v1(5433,596) 5392,596 5379.91,583.91 C44.1@5273,583.91 5270.09,581 U9.8@5164.9,581 5164.9,615.1 5108.5,671.5 ; 5108.5,671.5 5074.5,671.5 TP50.1@5051,695 5108.5,671.5
  Top Layer w15: U7.15@5354,1195.2 5384.2,1195.2 5403,1214 C17.1@5453.5,1214
  Top Layer w20: R91.2@5241.5,506.5 5243.8,506.5 5404.5,506.5 5428.98,530.98 5428.98,539.02 v1@5428.98,591.98 ; C17.1@5454,1214.5 C17.1@5453.5,1214 5453.5,1268.5 5454,1269 5454,1293 v1(5457,1296) ; v1(5581,1251) 5581.41,1250.59 D8.2@5581.41,1208.5
  Top Layer w25: C2.1@5367.5,2375 5367.5,2403.5 5408.59,2444.59 v1(5523.41,2444.59) 5524.41,2444.59 D1.2@5524.41,2374.5 ; v1@5428.98,591.98 v1(5433,596)
  Bottom Layer w25: v1(5433,596) 5438,591 D11.1@5529.99,591 D11.1@5515.99,605 ; v1(5523.41,2444.59) 5545.82,2467 5592,2467 5680.3,2378.7 5680.3,1545.3 5457,1322 v1(5457,1296) 5536,1296 v1(5581,1251) ; J14.1@5524,143 C75.1@5524,259
  Bottom Layer w30: D11.1@5515.99,605 5515.99,783.99 5735,1003 5735,1260 5715,1280 5665,1280 5636,1251 v1(5581,1251)
-15V: C3.1 C23.1 C72.2 C74.2 D1.1 D8.1 D12.2 J14.2 U2.11 U2.21 U7.11 U7.21 | length 2916.4
  Top Layer w10: U7.11@5354,1092.8 5389,1092.8 5404.8,1077 C23.1@5453.5,1077 ; D8.1@5632.59,1218.41 5645,1206
  Top Layer w20: C3.1@5398.5,2245 5398.5,2166.5 v1(5399,2166) ; v1(5453.5,1027.5) C23.1@5453.5,1077 ; D1.1@5575.59,2374.5 5575.59,2404.59 v1(5588,2417) ; D8.1@5632.59,1208.5 5632.59,1218.41 5632.59,1236 ; 5645,1206 v1(5680,1206)
  Top Layer w25: v1(5484,1459) 5632.59,1310.41 5632.59,1236
  Bottom Layer w20: v1@5394,2166 v1(5399,2166)
  Bottom Layer w25: D12.2@5348.47,571 5394.47,617 ; 5394.47,674.47 5394.47,680 ; J14.2@5424,143 5424,232
  Bottom Layer w30: 5394.47,617 5394.47,674.47 ; 5394.47,680 5394.47,968.46 v1(5453.5,1027.5) 5502,979 5574,979 5680,1085 v1(5680,1206) ; v1@5396.5,2163.5 5465,2095 5530,2095 ; v1(5484,1459) 5529,1459 5618,1548 5618,1672 5565,1725 5565,2060 5530,2095 ; v1(5588,2417) 5590,2415 5590,2155 5530,2095
  other v3: 5290.5,1122.5 5240,1125 5240,1170 5290,1170 5179.5,2289.5 5233.5,2291.5 5178.5,2344.5 5236.5,2346.5
/CS0: R22.1 U4.3 U6.35 | length 1826.6
  Top Layer w10: U6.35@2838.15,1805.12 2888.12,1805.12 3002,1919 3002,2083 v1(3039,2120) ; R22.1@4103.5,1825 4128.5,1800 v1(4151,1800) U4.3@4247.87,1800
  Bottom Layer w10: v1(3039,2120) 3288,2120 3522,1886 4065,1886 v1(4151,1800)
/CS0_ISO: R23.2 R37.1 U5.6 | length 443.9
  Top Layer w10: R23.2@4813.5,1811 R37.1@4885.5,1811 4918,1778.5 5151.62,1778.5 5167.75,1762.37 U5.6@5237.29,1762.37
/OD_XTR: R52.1 R53.2 U6.34 U8.5 | length 2085.5
  Top Layer w10: U6.34@2838.15,1785.43 2899.43,1785.43 3044,1930 v1(3044,1956) ; R53.2@4108.5,1023 R52.1@4108.5,1089 v1(4151,1089) 4162,1100 U8.5@4247.87,1100
  Bottom Layer w10: v1(3044,1956) 3044,1755 3242.2,1556.8 3643.2,1556.8 4111,1089 v1(4151,1089)
/OD_XTR_ISO: R3.1 R43.1 R56.1 R62.2 U2.20 U7.20 | length 2208.7
  Top Layer w10: R62.2@4798.5,1085 R56.1@4865.5,1085 4865.5,1033.5 v1(4865,1033) ; v1(4954,1387) 5078,1387 5102.5,1362.5 R43.1@5102.5,1335 5159,1335 5214.8,1279.2 U7.20@5214.8,1231.9 ; R3.1@5125.5,2495 5125.5,2440.5 v1(5129,2437) 5157.95,2408.05 U2.20@5157.95,2402.85
  Bottom Layer w10: v1(4865,1033) 4905,1073 4905,1338 v1(4954,1387) 5030.59,1463.59 5030.59,1858.41 4944,1945 4944,2302 5079,2437 v1(5129,2437) v1@5129.5,2437.5
\LDAC: R40.1 R133.2 TP5.1 U5.4 | length 697.3
  Top Layer w10: TP5.1@5345.35,1847.6 5352.44,1795.44 ; TP5.1@5355.63,1847.98 5352.44,1795.44 ; TP5.1@5365.6,1846.41 5352.44,1795.44 ; TP5.1@5383.59,1837.88 5352.44,1795.44 ; TP5.1@5391.11,1831.15 5352.44,1795.44 ; TP5.1@5396,1839 TP5.1@5396,1843 ; TP5.1@5397.32,1822.95 5352.44,1795.44 ; R133.2@5479.5,1628 5479.5,1692 R40.1@5482.5,1695 ; R40.1@5485,1692.5 R40.1@5482.5,1695 ; 5352.44,1795.44 5352.44,1820.44 TP5.1@5375,1843 5352.44,1795.44 ; 5352.44,1795.44 5352.44,1753.56 5363.31,1742.68 U5.4@5398.71,1742.68 5434.82,1742.68 R40.1@5482.5,1695
AGND: C18.2 C24.1 C33.2 C34.1 C35.2 C36.1 C37.2 C38.1 C39.2 C40.1 C41.2 C42.1 C63.2 C64.2 C65.2 C67.2 C68.2 C69.2 C70.2 R58.1 R59.1 R66.2 R76.2 R78.2 R80.2 R82.2 R84.2 R85.1 R86.1 R87.2 R88.2 R89.2 R92.1 R93.1 R94.2 R95.2 R96.2 R109.1 R120.2 R121.2 R128.2 R129.2 R130.2 R131.2 U6.112 U6.120 | length 9078.6
  Top Layer w10: R58.1@535,977.3 557.7,1000 602.3,1000 R59.1@625,977.3 647.7,1000 672.3,1000 R66.2@703.5,968.8 ; R92.1@916.5,490 895,511.5 895,558.5 R85.1@916.5,580 896.46,600.04 896.46,629.96 R76.2@925,658.5 ; R93.1@1567.19,492 1550,509.19 1550,563.5 R86.1@1571.5,585 1551.46,605.04 1551.46,634.96 R78.2@1580,663.5 ; 2466.1,1034 U6.112@2466.1,1078.74 ; R80.2@2546,641.5 2505,600.5 2505,540 2515,530 R87.2@2552.09,530 2552.09,522.09 2505,475 2505,435 2515,425 R94.2@2552.09,425 ; 2611,1123.57 2613.5,1121.07 2615.11,1121.07 2623.58,1112.59 U6.120@2623.58,1078.74 2623.58,1019.25 2615,1010.67 v1(2615,1008.83) ; R82.2@3348.62,637.01 3329.62,618.01 3329.62,549.53 3345.65,533.5 R88.2@3376.71,533.5 3376.71,519.57 3334.62,477.48 3334.62,442.48 3348.6,428.5 R95.2@3376.71,428.5 ; R84.2@4144,628.5 4115,599.5 4115,530 4125,520 R89.2@4157.09,520 4157.09,511.65 4115,469.57 4115,425 4125,415 R96.2@4157.09,415
  Top Layer w15: v1(2580,1146) 2602.43,1123.57 2611,1123.57
  Top Layer w20: v1@2465,970.8 v1(2466.1,971.9) 2466.1,1034
  Top Layer w30: R121.2@532,882 R121.2@535,885 R58.1@535,968.8 ; v1(635,1138.8) 685,1138.8 C18.2@690,1143.8 ; v1(640,873.8) C24.1@695,873.8 703.5,882.3 R66.2@703.5,968.8 ; v1(765,590) C33.2@765,645 ; R92.1@925,490 927,492 R129.2@1002,492 ; R76.2@925,658.5 981.5,658.5 C34.1@1005,635 ; v1(1005,590) C34.1@1005,635 ; C34.1@1005,640 C34.1@1005,635 ; C35.2@1415,645 1415,585 v1(1420,580) ; R93.1@1575.7,492 1577.7,494 R131.2@1660,494 ; R78.2@1580,663.5 1641.5,663.5 C36.1@1660,645 1665,640 v1(1665,580) ; v1(2091,798) v1(2258.5,630.5) 2266,623 C37.2@2386,623 C37.2@2391,618 ; R80.2@2546,641.5 2612.5,641.5 C38.1@2631,623 2716,623 v1(2721,628) ; R94.2@2552.09,425 2552.09,379.33 2575,356.42 v1(2575,335) ; v1(3103.62,623.5) 3108.62,618.5 C39.2@3178.62,618.5 C39.2@3183.62,613.5 ; R82.2@3348.62,637.01 3420.12,637.01 C40.1@3433.62,623.5 ; v1(3369.62,332.48) 3369.62,421.42 R95.2@3376.71,428.5 ; C40.1@3438.62,618.5 C40.1@3433.62,623.5 ; v1(3498.62,623.5) C40.1@3433.62,623.5 ; v1(3869,625) 3884,610 C41.2@3969,610 C41.2@3974,605 ; R84.2@4144,628.5 4225.5,628.5 C42.1@4239,615 v1(4239,555) ; R96.2@4157.09,415 4157.09,342.91 v2(4205,295)
  Bottom Layer w30: 605,676 691,590 v1(765,590) v1(1005,590) v1@1015,580 ; v1(635,1138.8) 640,1133.8 v1(640,873.8) ; 810,676 810,843.8 ; 1240,580 1690,580 ; v1(1420,580) v1(1665,580) 1705.5,620.5 ; 1955.5,620.5 2403.5,620.5 ; v1@2256,628 v1(2258.5,630.5) 2718.5,630.5 v1(2721,628) v1@2722,627 ; R109.1@2257,1079 2329.5,1079 C63.2@2340,1089.5 2406,1089.5 C65.2@2407,1088.5 ; v1(2466.1,971.9) 2407,1031 C65.2@2407,1088.5 ; R120.2@2575,277.09 v1(2575,335) ; v1(2580,1146) 2580,1144.19 2524.32,1088.5 C64.2@2473,1088.5 C65.2@2407,1088.5 ; C68.2@2675,868.5 C69.2@2745,868.5 C67.2@2815,868.5 C70.2@2885,868.5 v1(2885,813) ; 2867,617 3123.02,617 ; v1@3102.65,624.48 v1(3103.62,623.5) ; 3124,616.02 3519,616.02 ; v1(3369.62,332.48) 3374.62,327.48 R128.2@3374.62,259.57 ; v1(3498.62,623.5) v1@3507.6,632.48 ; 3527.98,625 v1(3869,625) 4204,625 4239,590 v1(4239,555) ; R130.2@4205,237.09 v2(4205,295)
AOUT0: C27.1 C62.1 D9.1 FB3.2 J9.3 R71.1 TP46.1 | length 2366.2
  Top Layer w30: R71.1@5308.3,846.5 5446.5,846.5 5533.91,933.91 FB3.2@5648,933.91 5687.09,933.91 5735,886 5815.91,886 C27.1@5816.91,885 5816.91,1020.56 D9.1@5822.35,1026 5822.35,1156.56 5816.91,1162 5816.91,1270.09 ; TP46.1@5805,1174.4 5816.91,1270.09 ; TP46.1@5805.03,1172.82 D9.1@5822.35,1048.88 ; TP46.1@5844.65,1177.74 5816.91,1270.09 ; TP46.1@5844.9,1171.98 D9.1@5822.35,1048.88 ; J9.3@6021.87,1398.64 5960,1415 ; J9.3@6021.87,1431.36 5960,1415 ; J9.3@6024,1415 5960,1415 ; 5816.91,1270.09 5816,1271 5960,1415 ; 5816.91,1270.09 TP46.1@5825,1174 D9.1@5822.35,1048.88
  Bottom Layer w30: TP46.1@5809.15,1171.83 5825,1115 ; TP46.1@5825,1174 5825,1115 ; TP46.1@5840.85,1171.83 5825,1115 ; C62.1@5975.91,1062 5878,1062 5825,1115
AOUT1: C9.1 C49.1 D4.1 FB1.2 J9.1 R16.1 TP9.1 | length 1786.1
  Top Layer w30: R16.1@5239,2008.5 5423.5,2008.5 5612.91,2197.91 FB1.2@5717,2197.91
  Top Layer w40: FB1.2@5717,2197.91 5827.09,2197.91 5866.09,2158.91 C9.1@5866.09,2048 5866.09,2037.76 5896.65,2007.2 D4.1@5896.65,1897 ; TP9.1@5895,1761 TP9.1@5887,1753 ; J9.1@6024,1615 5958.98,1615 5896.65,1677.33 ; TP9.1@5887,1753 D4.1@5896.65,1897 ; TP9.1@5887,1753 5896.65,1677.33 ; 5896.65,1677.33 D4.1@5896.65,1897
  Bottom Layer w40: TP9.1@5887,1753 5890,1756 C49.1@5978.91,1756 TP9.1@5887,1753
AUXVCC1: C54.1 C55.1 TP53.1 U6.124 | length 421.8
  Top Layer w10: U6.124@2702.32,1078.74 2702.32,1118.64
  Top Layer w15: v1(2555,1250) 2585.86,1250 2701.51,1134.35 2701.51,1122.99
  Bottom Layer w15: C54.1@2480,1298.5 C55.1@2545,1298.5 2545,1276.75 2550,1271.75 v1@2550,1250 ; TP53.1@2506,1222 2522,1222 v1@2550,1250 ; v1(2555,1250) v1@2550,1250
AUXVCC2: C52.1 C53.1 U6.123 | length 467
  Top Layer w10: 2585.5,1214.5 2592.37,1214.5 2681.01,1125.86 2681.01,1114.5 2682.64,1112.87 U6.123@2682.64,1078.74
  Top Layer w15: v1(2445,1250) 2504.8,1250 2540.3,1214.5 2585.5,1214.5
  Bottom Layer w20: C53.1@2350,1298.5 C52.1@2415,1298.5 2415,1270 2435,1250 v1(2445,1250)
AUXVCC3: C59.1 C60.1 R108.2 TP52.1 U6.3 | length 494.1
  Top Layer w10: 2884.8,1175.2 U6.3@2838.15,1175.2 2906.2,1175.2 v1(2913,1182)
  Bottom Layer w15: C59.1@2870,1298.5 2938.5,1298.5 TP52.1@2939,1299
  Bottom Layer w30: R108.2@2825,1195 2805,1215 R108.2@2805,1220 ; C59.1@2870,1298.5 C60.1@2805,1298.5 R108.2@2805,1220 ; v1(2913,1182) 2895,1200 R108.2@2825,1200 R108.2@2805,1220
AVCC: C68.1 C69.1 FB4.2 U6.121 | length 327.9
  Top Layer w10: U6.121@2643.27,1078.74 2643.27,1028.73 2665,1007 v1@2665,990
  Bottom Layer w20: FB4.2@2671,1081.5 2671,984 v1(2675,980) C68.1@2675,931.5 C69.1@2745,931.5 ; FB4.2@2675,1081.5 FB4.2@2675,1090
DGND: C1.2 C4.2 C5.2 C7.2 C8.2 C10.1 C12.2 C14.2 C15.2 C16.2 C19.1 C22.2 C25.1 C46.2 C48.2 C52.2 C53.2 C54.2 C55.2 C56.2 C57.2 C58.2 C59.2 C60.2 C61.2 C66.1 D6.1 D7.2 J1.1 J2.1 J2.3 J5.15 J8.2 J10.9 Q1.4 Q1.7 Q2.4 Q2.7 R10.1 R53.1 R100.2 R102.1 R109.2 S1.3 S1.4 TP54.1 U1.8 U3.2 U4.2 U4.8 U6.70 U6.127 U8.2 U8.8 Y1.3 | length 19192.8
  Top Layer w10: 1097.59,2097.41 1103,2097.41 1112,2088.41 v1(1112,2088) ; U6.70@2231.85,1765.75 2269.25,1765.75 v1(2300,1735) ; v1@2287,2575.57 v1(2287,2576) ; v1(2603,2176) v1@2604.02,2177.02 ; 2750,1195.45 2772,1173.45 2772,1147.46 2761.38,1136.83 U6.127@2761.38,1078.74
  Top Layer w12: U1.8@2216.2,2544.57 2256,2544.57 v1@2287,2575.57
  Top Layer w15: Q2.7@1038.78,2097.41 Q2.4@1071.32,2097.41 1097.59,2097.41 ; 2731.26,1265 2717,1250.74 2717,1228.45 2750,1195.45
  Top Layer w20: C1.2@1856.5,2565 1881,2589.5 v1(1881,2605) ; J1.1@2252.18,2726.7 2277,2634.96 J1.1@2301.82,2726.7 ; J1.1@2277,2730 2277,2585.57 v1@2287,2575.57 ; v1(2651,1633) 2740,1544 v1(2740,1445) 2740,1273.74 2731.26,1265 ; v1@3311.54,1220 3313.27,1218.27 v1(3315,1220) ; v1(4001,1023) R53.1@4045.5,1023 ; v1(4038,1958) 4038.5,1957.5 C10.1@4038.5,1909 4038.5,1908.43 4079.94,1867 4163,1867 4180,1850 U4.2@4247.87,1850 ; v1(4046,1345) 4045.5,1344.5 C25.1@4045.5,1300 4045.5,1299.43 4081.44,1263.5 4161.5,1263.5 4175,1250 U8.2@4247.87,1250 ; v1(4163,1532) 4181,1550 U4.8@4247.87,1550 ; v1(4189,891) 4232,891 4247.87,906.87 U8.8@4247.87,950
  Top Layer w25: D7.2@993,1258.53 1140.97,1258.53 1227.44,1345 ; S1.4@1676.73,1130 1679,1130 1707,1158 1807,1158 v1(1815,1150) 1819,1150 1832,1163 1860.27,1163 S1.3@1893.27,1130 S1.3@1903.5,1130 ; S1.4@1691.73,1130 1683.23,1121.5 1669.72,1135 1625,1135 1611.5,1121.5 C19.1@1605,1121.5 1595,1121.5 1570.75,1145.75 1570.75,1195.75 1471.5,1295 1380,1295 ; v1@2604.02,2177.02 R10.1@2604.02,2230.69 ; 1227.44,1345 J10.9@1330,1345 ; 1227.44,1345 J10.9@1328.89,1360.02 ; 1227.44,1345 J10.9@1328.89,1329.98 ; 1227.44,1345 J10.9@1330,1345 ; 1227.44,1345 J10.9@1328.89,1360.02 ; 1227.44,1345 J10.9@1328.89,1329.98 ; 1227.44,1345 J10.9@1330,1345 ; 1227.44,1345 J10.9@1328.89,1360.02 ; 1227.44,1345 J10.9@1328.89,1329.98 ; 1227.44,1345 J10.9@1330,1345 ; 1227.44,1345 J10.9@1328.89,1360.02 ; 1227.44,1345 J10.9@1328.89,1329.98 ; 1227.44,1345 J10.9@1330,1345 ; 1227.44,1345 J10.9@1328.89,1360.02 ; 1227.44,1345 J10.9@1328.89,1329.98 ; 1227.44,1345 J10.9@1330,1345 ; 1227.44,1345 J10.9@1328.89,1360.02 ; 1227.44,1345 J10.9@1328.89,1329.98 ; 1227.44,1345 J10.9@1330,1345 ; 1227.44,1345 J10.9@1328.89,1360.02 ; 1227.44,1345 J10.9@1328.89,1329.98 ; 1227.44,1345 J10.9@1330,1345 ; 1227.44,1345 J10.9@1328.89,1360.02 ; 1227.44,1345 J10.9@1328.89,1329.98 ; 1227.44,1345 J10.9@1330,1345 ; 1227.44,1345 J10.9@1328.89,1360.02 ; 1227.44,1345 J10.9@1328.89,1329.98 ; 1227.44,1345 J10.9@1330,1345 ; 1227.44,1345 J10.9@1328.89,1360.02 ; 1227.44,1345 J10.9@1328.89,1329.98 ; 1227.44,1345 J10.9@1330,1345 ; 1227.44,1345 J10.9@1328.89,1360.02 ; 1227.44,1345 J10.9@1328.89,1329.98 ; 1227.44,1345 J10.9@1330,1345 ; 1227.44,1345 J10.9@1328.89,1360.02 ; 1227.44,1345 J10.9@1328.89,1329.98 ; 1227.44,1345 J10.9@1330,1345 ; 1227.44,1345 J10.9@1328.89,1360.02 ; 1227.44,1345 J10.9@1328.89,1329.98 ; 1227.44,1345 J10.9@1330,1345 ; 1227.44,1345 J10.9@1328.89,1360.02 ; 1227.44,1345 J10.9@1328.89,1329.98 ; 1227.44,1345 J10.9@1330,1345 ; 1227.44,1345 J10.9@1328.89,1360.02 ; 1227.44,1345 J10.9@1328.89,1329.98 ; 1227.44,1345 J10.9@1330,1345 ; 1227.44,1345 J10.9@1328.89,1360.02 ; 1227.44,1345 J10.9@1328.89,1329.98 ; 1227.44,1345 J10.9@1330,1345 ; 1227.44,1345 J10.9@1328.89,1360.02 ; 1227.44,1345 J10.9@1328.89,1329.98 ; 1227.44,1345 J10.9@1330,1345 ; 1227.44,1345 J10.9@1328.89,1360.02 ; 1227.44,1345 J10.9@1328.89,1329.98 ; 1227.44,1345 J10.9@1330,1345 ; 1227.44,1345 J10.9@1328.89,1360.02 ; 1227.44,1345 J10.9@1328.89,1329.98 ; 1227.44,1345 J10.9@1330,1345 ; 1227.44,1345 J10.9@1328.89,1360.02 ; 1227.44,1345 J10.9@1328.89,1329.98 ; 1227.44,1345 J10.9@1330,1345 ; 1227.44,1345 J10.9@1328.89,1360.02 ; 1227.44,1345 J10.9@1328.89,1329.98 ; J10.9@1320.55,1333.28 1380,1295 ; J10.9@1320.55,1333.28 1380,1295 ; J10.9@1320.55,1333.28 1380,1295 ; J10.9@1320.55,1333.28 1380,1295 ; J10.9@1320.55,1333.28 1380,1295 ; J10.9@1320.55,1333.28 1380,1295 ; J10.9@1320.55,1333.28 1380,1295 ; J10.9@1320.55,1333.28 1380,1295 ; J10.9@1320.55,1333.28 1380,1295 ; J10.9@1320.55,1333.28 1380,1295 ; J10.9@1320.55,1333.28 1380,1295 ; J10.9@1320.55,1333.28 1380,1295 ; J10.9@1320.55,1333.28 1380,1295 ; J10.9@1320.55,1333.28 1380,1295 ; J10.9@1320.55,1333.28 1380,1295 ; J10.9@1330,1345 1380,1295 ; J10.9@1330,1345 1380,1295 ; J10.9@1330,1345 1380,1295 ; J10.9@1330,1345 1380,1295 ; J10.9@1330,1345 1380,1295 ; J10.9@1330,1345 1380,1295 ; J10.9@1330,1345 1380,1295 ; J10.9@1330,1345 1380,1295 ; J10.9@1330,1345 1380,1295 ; J10.9@1330,1345 1380,1295 ; J10.9@1330,1345 1380,1295 ; J10.9@1341.72,1354.45 1380,1295 ; J10.9@1341.72,1354.45 1380,1295 ; J10.9@1341.72,1354.45 1380,1295 ; J10.9@1341.72,1354.45 1380,1295 ; J10.9@1341.72,1354.45 1380,1295 ; J10.9@1341.72,1354.45 1380,1295 ; J10.9@1341.72,1354.45 1380,1295 ; J10.9@1341.72,1354.45 1380,1295 ; J10.9@1341.72,1354.45 1380,1295 ; J10.9@1341.72,1354.45 1380,1295 ; J10.9@1341.72,1354.45 1380,1295 ; J10.9@1341.72,1354.45 1380,1295 ; J10.9@1341.72,1354.45 1380,1295 ; J10.9@1341.72,1354.45 1380,1295 ; J10.9@1341.72,1354.45 1380,1295
  Top Layer w30: C5.2@1051.5,2036 1110,2036 v1(1111,2035) ; C22.2@3102.01,990 3290,990 3313.27,1013.27 Y1.3@3313.27,1110 v1@3313.27,1218.27 ; C16.2@3102.01,1220 v1@3311.54,1220
  Top Layer w40: v1(842,1261) 892.5,1261 C15.2@908,1276.5
  Bottom Layer w10: v1(1111,2035) v1@1112,2036 ; v1(1112,2088) v1@1112,2088.41
  Bottom Layer w20: C46.2@1918.91,2486 1918.91,2567.09 v1(1881,2605) 1873,2613 1917,2657 2206,2657 v1(2287,2576) 2287,2492 v1(2603,2176) ; C48.2@2231.85,1734.25 2231.1,1735 v1(2300,1735) ; C56.2@2740,1356.5 C56.2@2740.85,1356.5 ; C66.1@3018.5,984 C61.2@3018.5,1049 ; v1(3315,1220) 3512,1023 v1(4001,1023) 4133,891 v1(4189,891) 4237,939 4237,1247 4210,1274 4117,1274 v1(4046,1345) 4126,1425 4126,1495 v1(4163,1532) ; v1(4038,1958) 4059.28,1979.28
  Bottom Layer w25: v1(1815,1150) 1824,1159 R109.2@2257,1159 2257,1314 2304.5,1361.5 C53.2@2350,1361.5 ; C48.2@2231.85,1734.25 2231.85,1579.15 2350,1461 C53.2@2350,1361.5 ; C56.2@2740,1356.5 2745,1361.5 C60.2@2805,1361.5 ; v1(2740,1445) C56.2@2740,1362.5 2740,1361.5 C57.2@2675,1361.5 C58.2@2610,1361.5 C55.2@2545,1361.5 C54.2@2480,1361.5 C52.2@2415,1361.5 C53.2@2350,1361.5 ; C60.2@2805,1356.5 C59.2@2870,1356.5 ; C59.2@2870,1361.5 3173.5,1361.5 v1(3315,1220)
  Bottom Layer w40: v1(1095,1800) 1020,1875 1020,1996.41 1058.59,2035 v1(1111,2035) ; v1@1112,2036 v1(1112,2088) ; v1(2571,1749) 2572,1750 R100.2@2630.5,1750 R102.1@2630.5,1684 2630.5,1653.5 v1(2651,1633)
  other v1: 749,1260 793,1260 1095,1668 1135,1668 430,1700 480,1700 1095,1712 1135,1712 430,1750 480,1750 1095,1759 1135,1759 1135,1800
DIN_ISO: R29.2 R30.1 R38.2 R39.2 U5.8 | length 475.8
  Top Layer w10: R29.2@4813.5,1685 4822.5,1676 R30.1@4885.5,1676 4918.5,1643 5053.5,1643 R38.2@5061,1650.5 5126,1650.5 R39.2@5127,1649.5 5128.16,1649.5 5178,1699.33 5178,1700.5 5200.5,1723 U5.8@5237.29,1723
DVCC: C10.2 C14.1 C15.1 C25.2 C57.1 C58.1 D7.1 FB2.2 FB4.1 J2.7 J5.16 J7.2 R1.2 R4.2 R22.2 R24.2 R26.1 R27.2 R28.2 R34.1 R35.1 R41.1 R42.1 R44.2 R45.2 R48.2 R52.2 R60.2 R72.1 R98.2 R99.2 R104.2 R105.2 TP29.1 TP33.1 TP47.1 U4.1 U6.126 U8.1 | length 11566.7
  Top Layer w10: U6.126@2741.69,1078.74 2741.69,1163.31
  Top Layer w12: 2735,1170 2741.69,1163.31
  Top Layer w15: v1@2682,1253 2682,1223 2735,1170
  Top Layer w20: TP29.1@3967,1560 R35.1@4040.5,1560 ; R24.2@4040.5,1755 R22.2@4040.5,1825 ; v1@4047.67,1417 4108.5,1356.17 C25.2@4108.5,1300 U8.1@4247.87,1300 ; 4101,1958 4101.5,1957.5 ; C10.2@4101.5,1909 4158,1909 4167,1900 U4.1@4247.87,1900
  Top Layer w30: R4.2@448,2363.5 448,2423 ; v1(3954.5,1839.5) 3954.5,1978.5 3984,2008 4074,2008 4101,1981 4101,1958 ; TP47.1@3967,955 R60.2@4045.5,955 ; C10.2@4101.5,1909 4101.5,1957.5
  Top Layer w40: 448,2423 490.5,2465.5 R1.2@766,2465.5 830,2465.5 900.5,2395 1098,2395 1380,2113 1380,2095 ; J7.2@1380,2045 1380,2095 ; 1380,2081 1380,2095 ; v1(1610,1295) R44.2@1663.5,1295 R44.2@1668.5,1295 ; v1(1610,1385) R42.1@1668.5,1385 ; v1(1610,1480) R41.1@1663.5,1480 ; v1(1610,1570) R34.1@1663.5,1570 ; v1(1610,1660) R26.1@1663.5,1660 ; v1(1610,1735) v1(1610,1894) ; J5.16@2423,2660 2690,2393 2690,2045 v1(2680,2035) ; v1(2630,1548) 2679,1499 v1(2679,1250)
  Bottom Layer w15: J2.7@3687.96,2773.46 3659,2705 ; J2.7@3693.56,2740.36 3760,2704 ; J2.7@3701.18,2766.2 3659,2705 ; J2.7@3702.08,2752.81 3760,2704 ; J2.7@3715.92,2752.81 3659,2705 ; J2.7@3716.81,2766.22 3760,2704 ; J2.7@3724.4,2740.33 3659,2705 ; J2.7@3729.99,2773.54 3760,2704 ; 3659,2705 3709,2755 3760,2704 ; 3659,2705 J2.7@3709,2760 3760,2704 ; 3659,2705 3659,2592 3742,2592 3760,2610 3760,2704
  Bottom Layer w20: v1(3966,1710) v1@3967,1709
  Bottom Layer w25: 1218.14,1292.86 v1@1607.86,1292.86
  Bottom Layer w30: J7.2@1380,2045 1470,1955
  Bottom Layer w35: TP29.1@3967,1560 v1@3967,1709
  Bottom Layer w40: TP33.1@1103,1408 1218.14,1292.86 ; 1470,1955 1550,1955 1610,1895 v1(1610,1894) 1671,1955 2425,1955 ; v1@1607.86,1292.86 v1(1610,1295) v1(1610,1385) v1(1610,1480) v1(1610,1570) v1(1610,1660) v1(1610,1735) ; C58.1@2610,1298.5 C57.1@2675,1298.5 v1@2675,1246 ; v1@2627,1548 v1(2630,1548) ; 2671,1167.18 2671,1206 2679,1214 v1(2679,1250) ; v1(2680,2035) 2660,2015 R98.2@2660,1976.5 ; R104.2@3080,1571.5 R105.2@3015,1571.5 2818.5,1571.5 2795,1548 v1(2630,1548) ; 3659,2592 3584,2517 3040,2517 2810,2287 2810,2109 2852.5,2066.5 ; J2.7@3709,2755 J2.7@3709,2760 ; v1(3954.5,1839.5) 3510.5,1839.5 3283.5,2066.5 2852.5,2066.5 ; 2425,1955 2434,1955 2455.5,1976.5 R98.2@2660,1976.5 ; 2425,1955 2479,1901 2479,1699 v1(2630,1548) ; R98.2@2660,1976.5 R99.2@2730,1976.5 2762.5,1976.5 2852.5,2066.5
  other v1: 4040,1423
EFLAG1: R27.1 TP7.1 U4.6 U6.26 | length 1604.8
  Top Layer w10: U6.26@2838.15,1627.95 2999.31,1627.95 3037.7,1666.34 3037.7,1699.48 3112.22,1774 3148,1774 TP7.1@3177,1803 v1(3212,1803) ; v1(3589,1636) 3612,1659 4015.02,1659 4015.52,1658.5 4070,1658.5 R27.1@4103.5,1625 4144,1625 4169,1650 U4.6@4247.87,1650
  Bottom Layer w10: v1(3212,1803) 3379,1636 v1(3589,1636)
EFLAG1_ISO: R31.1 R50.2 U7.17 U7.18 U7.19 | length 724.3
  Top Layer w10: R50.2@4813.5,1625 4830.5,1608 R31.1@4885.5,1608 4885.5,1565.5 5032,1419 5135,1419 5266,1288 5266,1263 U7.18@5266,1231.9 ; U7.19@5240.4,1231.9 U7.18@5266,1231.9 ; U7.17@5291.6,1231.9 U7.18@5266,1231.9
EFLAG2: R60.1 TP17.1 U6.27 U8.6 | length 1986.1
  Top Layer w10: U6.27@2838.15,1647.64 2945,1647.64 2977.64,1647.64 v1(2998,1668) 3016.54,1686.54 3016.54,1703.78 3115.76,1803 TP17.1@3119,1803 ; R60.1@4108.5,962 4140,962 4158,980 4158,1031 4177,1050 U8.6@4247.87,1050
  Bottom Layer w10: v1@2998,1662 3081,1662 3224,1519 3636,1519 4104,1051 v1@4170,1051
  other v1: 4177,1045
EFLAG2_ISO: R61.1 R67.2 U2.17 U2.18 U2.19 | length 2310.7
  Top Layer w10: R67.2@4798.5,1025 4801.5,1025 R61.1@4865.5,961 4865.5,910.5 v1(4865,910) ; U2.19@5183.55,2402.85 U2.18@5209.15,2402.85 ; v2(5209.15,2455.15) U2.18@5209.15,2402.85 ; U2.17@5234.75,2402.85 U2.18@5209.15,2402.85
  Bottom Layer w10: v1(4865,910) 4833,942 4833,1371 4796,1408 4796,2449 4874,2527 5135,2527 5170.95,2527 5209.15,2488.8 v2(5209.15,2455.15)
EXT: J7.3 J10.4 | length 92196.5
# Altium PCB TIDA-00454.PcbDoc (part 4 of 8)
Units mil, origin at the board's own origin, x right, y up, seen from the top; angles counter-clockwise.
Board outline 6159 x 2859 mil, 2 copper layers (Top Layer, Bottom Layer), stack 62 mil thick; 328 components, 224 nets, 884 pads, 184 vias.

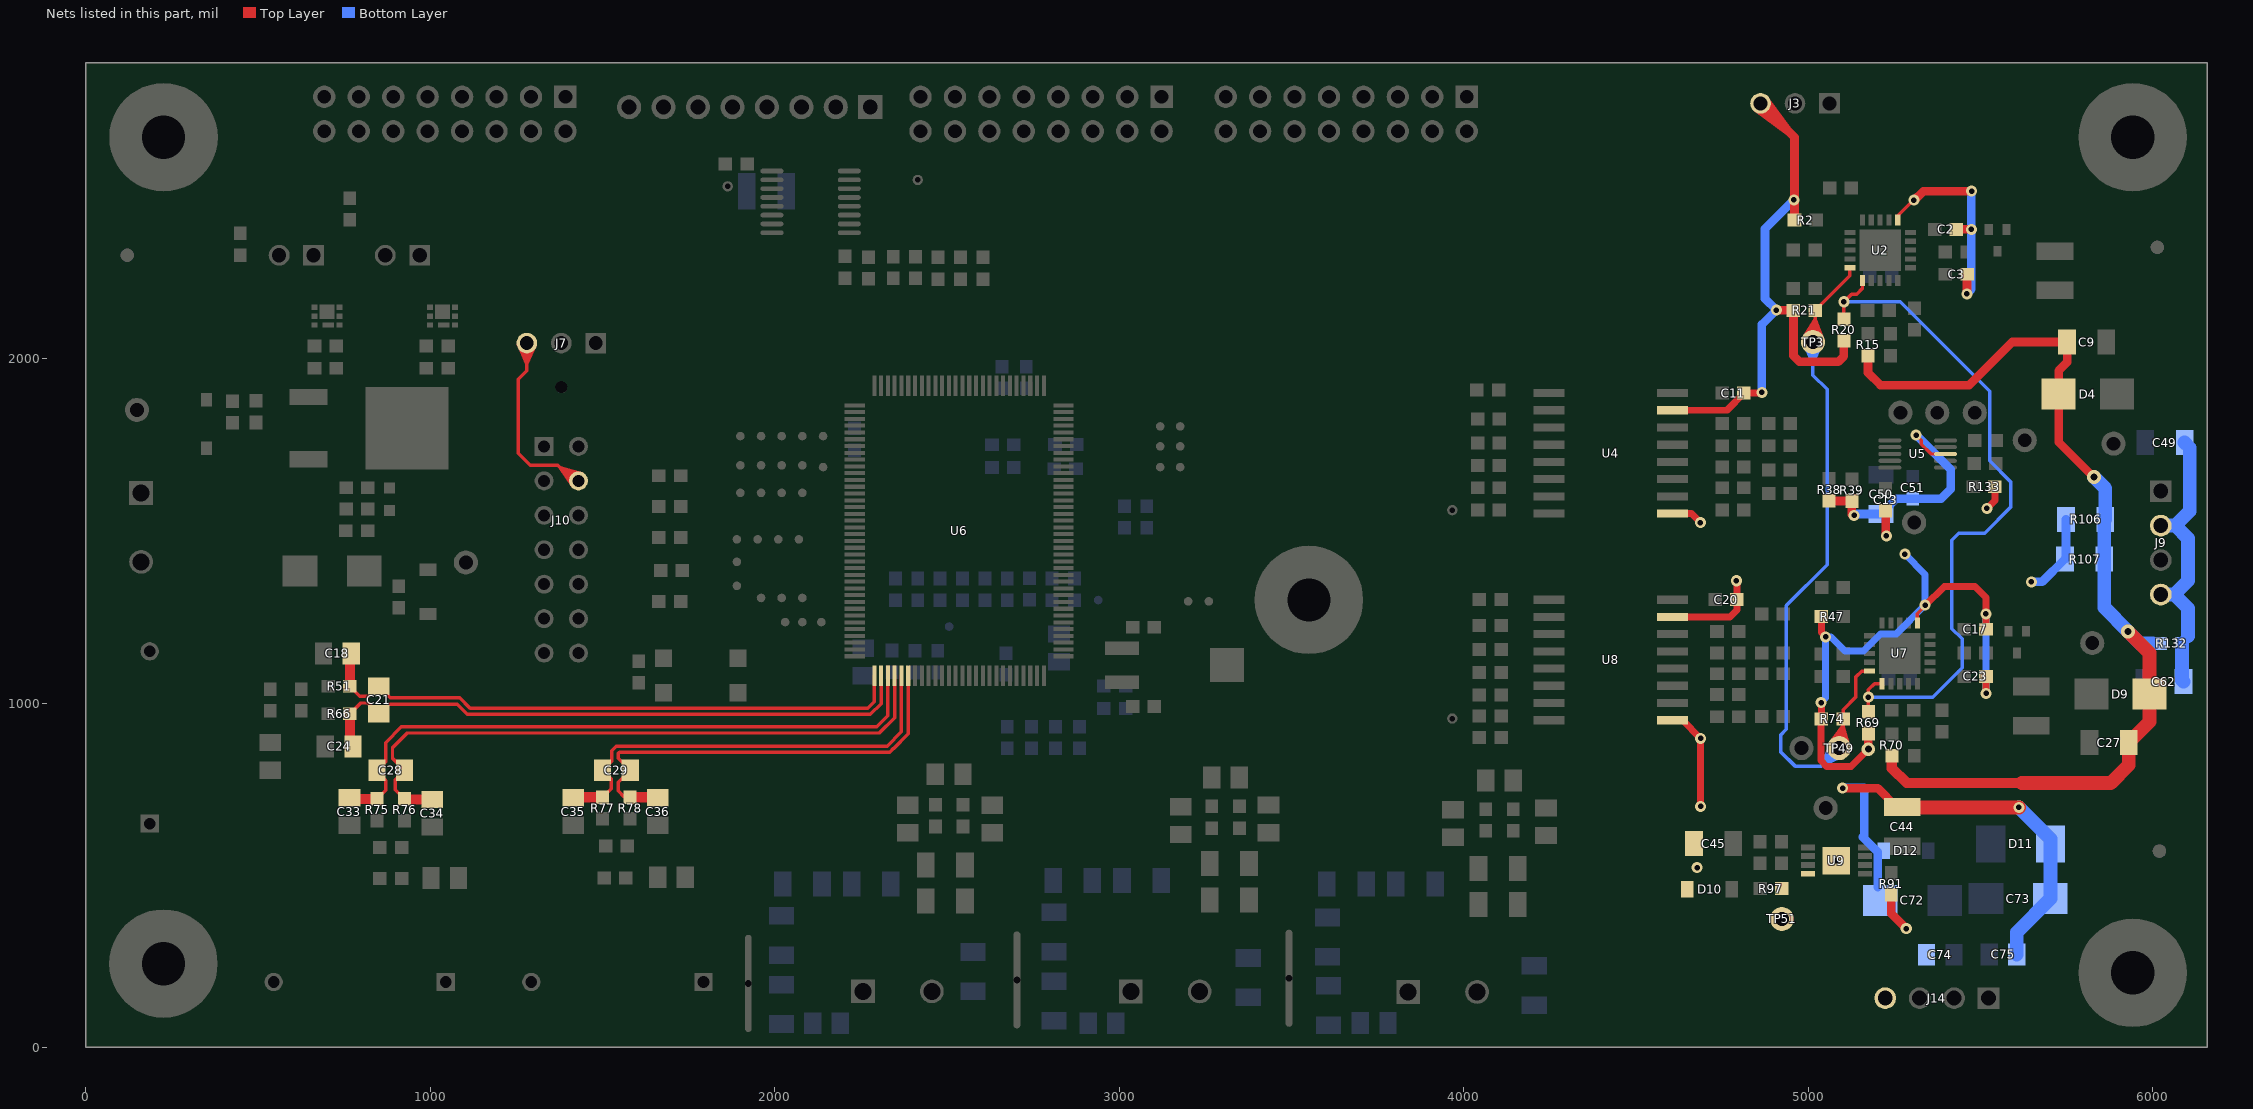
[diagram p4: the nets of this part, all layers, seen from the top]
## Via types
v1: diameter 32, hole 16, Top Layer to Bottom Layer, tented both sides, 168 vias
v2: diameter 40, hole 20, Top Layer to Bottom Layer, tented both sides, 8 vias
v3: diameter 24, hole 12, Top Layer to Bottom Layer, tented both sides, 8 vias

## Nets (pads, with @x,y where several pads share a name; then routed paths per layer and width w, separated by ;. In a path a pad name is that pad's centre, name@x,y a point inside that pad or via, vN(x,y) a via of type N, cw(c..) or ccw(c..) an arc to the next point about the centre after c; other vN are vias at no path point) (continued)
EXT: (continued)
  Top Layer w10: 1378.08,1682.31 J10.4@1421.7,1635.57 ; 1378.08,1682.31 J10.4@1439.73,1665.35 ; 1378.08,1682.31 J10.4@1413.81,1629.29 ; 1378.08,1682.31 J10.4@1430,1645 ; 1378.08,1682.31 J10.4@1436.29,1655.87 ; 1378.08,1682.31 J10.4@1421.7,1635.57 ; 1378.08,1682.31 J10.4@1439.73,1665.35 ; 1378.08,1682.31 J10.4@1413.81,1629.29 ; 1378.08,1682.31 J10.4@1430,1645 ; 1378.08,1682.31 J10.4@1436.29,1655.87 ; 1378.08,1682.31 J10.4@1421.7,1635.57 ; 1378.08,1682.31 J10.4@1439.73,1665.35 ; 1378.08,1682.31 J10.4@1413.81,1629.29 ; 1378.08,1682.31 J10.4@1430,1645 ; 1378.08,1682.31 J10.4@1436.29,1655.87 ; 1378.08,1682.31 J10.4@1421.7,1635.57 ; 1378.08,1682.31 J10.4@1439.73,1665.35 ; 1378.08,1682.31 J10.4@1413.81,1629.29 ; 1378.08,1682.31 J10.4@1430,1645 ; 1378.08,1682.31 J10.4@1436.29,1655.87 ; 1378.08,1682.31 J10.4@1421.7,1635.57 ; 1378.08,1682.31 J10.4@1439.73,1665.35 ; 1378.08,1682.31 J10.4@1413.81,1629.29 ; 1378.08,1682.31 J10.4@1430,1645 ; 1378.08,1682.31 J10.4@1436.29,1655.87 ; 1378.08,1682.31 J10.4@1421.7,1635.57 ; 1378.08,1682.31 J10.4@1439.73,1665.35 ; 1378.08,1682.31 J10.4@1413.81,1629.29 ; 1378.08,1682.31 J10.4@1430,1645 ; 1378.08,1682.31 J10.4@1436.29,1655.87 ; 1378.08,1682.31 J10.4@1421.7,1635.57 ; 1378.08,1682.31 J10.4@1439.73,1665.35 ; 1378.08,1682.31 J10.4@1413.81,1629.29 ; 1378.08,1682.31 J10.4@1430,1645 ; 1378.08,1682.31 J10.4@1436.29,1655.87 ; 1378.08,1682.31 J10.4@1421.7,1635.57 ; 1378.08,1682.31 J10.4@1439.73,1665.35 ; 1378.08,1682.31 J10.4@1413.81,1629.29 ; 1378.11,1682.43 J10.4@1430,1645 ; 1378.11,1682.43 J10.4@1436.31,1655.86 ; 1378.11,1682.43 J10.4@1439.77,1665.34 ; 1378.11,1682.43 J10.4@1413.78,1629.32
GND_EARTH: C49.2 C62.2 J9.2 J9.4 R132.2 | length 817.2
  Bottom Layer w40: J9.4@6024,1315 J9.4@6053,1315 ; J9.2@6024,1515 6066,1515 ; R132.2@6085.5,1173 6085.5,1066.59 C62.2@6090.09,1062 ; C49.2@6093.09,1756 6108,1741.09 6108,1557 6066,1515 ; 6103,1194.7 6103,1275 6063,1315 6103,1355 6103,1478 6066,1515
GND_ISO: C2.2 C3.2 C11.2 C13.2 C17.2 C20.2 C23.2 C44.2 C45.1 C50.2 C51.2 C72.1 C73.2 C74.1 C75.2 D10.2 D11.2 D12.1 J3.3 J14.4 R2.2 R20.2 R21.1 R38.1 R39.1 R47.2 R69.2 R74.1 R91.1 R97.2 R106.2 R107.2 R133.1 TP51.1 U2.16 U4.9 U4.15 U5.3 U7.16 U8.9 U8.15 U9.4 U9.9 | length 7720.9
  Top Layer w10: v1(4908,2141) v1@4909,2140 ; U2.16@5260.35,2402.85 5260.35,2414.68 5298.67,2453 5312,2453 5307,2458 v1(5307,2460) ; v1(5314,1778) 5329.06,1762.94 5329.06,1751.48 5357.54,1723 U5.3@5398.71,1723 ; U7.16@5317.2,1231.9 5317.2,1259.74 5340,1282.54 v1(5340,1284)
  Top Layer w20: U4.15@4601.13,1850 U4.15@4606.14,1850 4764.06,1850 4813.5,1899.43 C11.2@4813.5,1900 4864,1900 v1(4866,1902) ; U8.9@4606.13,950 4635,950 v1(4688,897) v1(4688,700) ; U8.15@4606.13,1250 4773.2,1250 4793.5,1270.3 C20.2@4793.5,1300 v1@4793.5,1353.5 ; U4.9@4606.14,1550 4661,1550 v1(4687,1524) ; v1(5038,1001) 5038.5,1000.5 R74.1@5038.5,954 5037.2,952.7 5037.2,832.8 5053.8,816.2 5125.2,816.2 v2(5175,866) ; R47.2@5038.5,1251 5038.5,1204.5 v1(5051,1192) ; v1@5340,1282.54 5395.46,1338 5485,1338 5516.5,1306.5 v1(5516.5,1259) C17.2@5516.5,1214 ; C23.2@5516.5,1077 5516.5,1028.5 v1(5517,1028) ; v1(5519,1565) 5542.5,1588.5 R133.1@5542.5,1628
  Top Layer w25: J3.3@4850.58,2727.74 4945.03,2657.97 J3.3@4875.26,2752.42 ; J3.3@4862,2741 4960.5,2642.5 R2.2@4960.5,2402 ; v1@4909,2140 R21.1@4957.5,2140 4957.5,2008.5 4975,1991 5088,1991 5104,2007 R20.2@5104,2051.5 ; R38.1@5061,1587.5 5062,1586.5 R39.1@5127,1586.5 v1@5127,1547 ; v1(5100,753) 5202,753 5256.91,698.09 C44.2@5273,698.09 C44.2@5274.09,697 ; v2(5175,866) R69.2@5175,911.5 ; C13.2@5225,1558.5 5225,1487 v1(5227,1485) ; R91.1@5241.5,443.5 5241.5,388.5 v1(5285,345) ; v1@5307,2458 5335,2486 v1(5475,2486) ; C2.2@5430.5,2375 v1(5474,2375) ; v1(5461,2188) 5461.5,2188.5 C3.2@5461.5,2245
  Top Layer w40: C44.2@5274.09,697 v1(5612,697)
  Bottom Layer w20: v1(5038,1001) 5051,1014 v1(5051,1192) 5066,1192 5107,1151 5161,1151 5210,1200 5256,1200 v1(5340,1284) 5340,1373 v1(5281,1432) ; v1@5516.5,1265.5 v1(5516.5,1259) 5516.5,1028.5 v1(5517,1028)
  Bottom Layer w25: v1(4866,1902) 4866,2099 v1(4908,2141) 4875,2174 4875,2377 v1(4959,2461) ; v1(5100,753) 5101,754 5162.53,754 5162.53,615.04 5158.5,611 5202,567.5 C72.1@5202,465 ; v1@5142.91,1548.91 C50.2@5212,1548.91 5256.59,1593.5 C51.2@5304,1593.5 5386.5,1593.5 5414,1621 5414,1678 v1(5314,1778) ; v1(5461,2188) 5474,2201 v1(5474,2375) 5474,2485 v1(5475,2486) ; v1(5648,1352) 5679.91,1352 R107.2@5745.91,1418 5748.91,1421 R106.2@5748.91,1533
  Bottom Layer w40: C75.2@5606,270 5606,334.5 C73.2@5703.5,432 5703.5,590.5 D11.2@5704.01,591 5704.01,604.99 v1(5612,697)
  other v1: 4678,522 5082.2,542.4 4791.99,1355 5134,1545
GND_ISO1: C9.2 C27.2 D4.2 D9.2 R15.1 R70.1 R106.1 R107.1 R132.1 | length 2918.1
  Top Layer w25: R15.1@5174,2008.5 5174,1959 5210,1923 5468,1923 5593,2048 C9.2@5751.91,2048 5751.91,1989.56 5727.35,1965 D4.2@5727.35,1897 5727.35,1757.65 5829,1656 v2(5830,1656)
  Top Layer w30: R70.1@5243.3,846.5 5243.3,810.7 5286.09,767.91 5621,767.91
  Top Layer w40: 5621,767.91 5879,767.91 5931.09,820 C27.2@5931.09,885 5991.65,945.56 D9.2@5991.65,1026 5991.65,1145.35 v2(5929,1208)
  Bottom Layer w40: v2(5830,1656) 5863.09,1622.91 R106.1@5863.09,1533 5860.09,1530 R107.1@5860.09,1418 5860.09,1276.91 v2(5929,1208) 5964,1173 5999.82,1173
I1+: C18.1 C21.1 R51.1 U6.103 | length 1751.8
  Top Layer w10: R51.1@766.5,1048.8 795.3,1020 821.2,1020 C21.1@850,1048.8 883.8,1015 1085,1015 1115,985 2270,985 2288.94,1003.94 U6.103@2288.94,1078.74
  Top Layer w30: R51.1@766.5,1048.8 766.5,1140.3 C18.1@770,1143.8
I1-: C21.2 C24.2 R66.1 U6.104 | length 1784.1
  Top Layer w10: R66.1@766.5,968.8 797.7,1000 818.8,1000 C21.2@850,968.8 878.2,997 1077.54,997 1107.54,967 2277.46,967 2308.62,998.17 U6.104@2308.62,1078.74
  Top Layer w30: R66.1@766.5,968.8 766.5,882.3 C24.2@775,873.8
I2+: C28.1 C33.1 R75.1 U6.105 | length 1882.2
  Top Layer w10: R75.1@845,721.5 870,746.5 870,775 845,800 C28.1@845,805 870,830 870,885 916,931 2296,931 2328.31,963.31 U6.105@2328.31,1078.74
  Top Layer w30: C33.1@765,725 768.5,721.5 R75.1@845,721.5
I2-: C28.2 C34.2 R76.1 U6.106 | length 1881.6
  Top Layer w10: R76.1@925,721.5 897.8,748.7 897.8,777.8 C28.2@925,805 890,840 890,870 933,913 2303.46,913 2347.99,957.54 U6.106@2347.99,1078.74
  Top Layer w30: R76.1@925,721.5 926.5,720 C34.2@1005,720
I3+: C29.1 C35.1 R77.1 U6.107 | length 1278.4
  Top Layer w10: R77.1@1500,726.5 1525,751.5 1525,780 C29.1@1500,805 1526,831 1526,861 1540,875 2326,875 2367.68,916.68 U6.107@2367.68,1078.74
  Top Layer w30: C35.1@1415,725 1416.5,726.5 R77.1@1500,726.5
I3-: C29.2 C36.2 R78.1 U6.108 | length 1294.4
  Top Layer w10: R78.1@1580,726.5 1563.5,726.5 1545,745 1545,770 1577.5,802.5 C29.2@1580,805 1545.5,839.5 1545.5,853.5 1549,857 2333.46,857 2344.46,868 2345,868 2387.36,910.36 U6.108@2387.36,1078.74
  Top Layer w30: R78.1@1580,726.5 1658.5,726.5 C36.2@1660,725
IAOUT_FLAG2: R20.1 R69.1 U2.6 U7.6 | length 2053.2
  Top Layer w10: R20.1@5104,2114.5 v1(5104,2165) 5126,2187 5141,2187 5157.95,2203.95 U2.6@5157.95,2226.85 ; R69.1@5175,974.5 5175,1012 v1@5180,1017 ; v1(5175,1017) 5175,1038 5192.9,1055.9 U7.6@5214.8,1055.9
  Bottom Layer w10: v1@5102.5,2166.5 v1(5104,2165) 5268,2165 5527.8,1905.2 5527.8,1703 5589,1641.8 5589,1569 5513,1493 5438,1493 5417,1472 5417,1216 5447,1186 5447,1102 5362,1017 v1(5175,1017)
IMON_FLAG2: R21.2 R74.2 TP3.1 TP49.1 U2.5 U7.5 | length 3800.7
  Top Layer w10: TP3.1@4985.62,2057.72 5020.5,2113.28 ; TP3.1@4994.63,2052.99 5020.5,2113.28 ; TP3.1@5004.15,2049.75 5020.5,2113.28 ; TP3.1@5024,2047.77 5020.5,2113.28 ; TP3.1@5033.97,2049.08 5020.5,2113.28 ; TP3.1@5043.74,2051.93 5020.5,2113.28 ; TP49.1@5062.35,880.64 5101.5,934.95 ; TP49.1@5071.03,875.34 5101.5,934.95 ; TP49.1@5080.3,871.45 5101.5,934.95 ; TP49.1@5099.95,868.02 5101.5,934.95 ; TP49.1@5109.99,868.55 5101.5,934.95 ; TP49.1@5119.96,870.6 5101.5,934.95 ; U2.5@5121.15,2263.75 5121.15,2240.65 R21.2@5020.5,2140 5020.5,2054.5 TP3.1@5014,2048 5020.5,2113.28 ; U7.5@5178,1092.8 5155.8,1092.8 5139,1076 5139,1018 5101.5,980.5 R74.2@5101.5,954 5101.5,880.5 TP49.1@5090,869 5101.5,934.95
  Bottom Layer w10: TP3.1@4988.6,2042.46 5014,1987 ; TP3.1@4998.14,2045.9 5014,1987 ; TP3.1@5008.01,2047.7 5014,1987 ; TP3.1@5019.99,2047.7 5014,1987 ; TP3.1@5029.86,2045.9 5014,1987 ; TP3.1@5039.4,2042.46 5014,1987 ; TP49.1@5068.65,883.85 5038,817 ; TP49.1@5077.52,879.02 5038,817 ; TP49.1@5085.59,873.07 5038,817 ; TP49.1@5090,869 5038,817 ; TP49.1@5094.07,864.59 5038,817 ; TP49.1@5100.02,856.52 5038,817 ; TP49.1@5104.85,847.65 5038,817 ; 5014,1987 TP3.1@5014,2048 5014,1952 5055.44,1910.56 5055.44,1401.44 4937,1283 4937,924 4920,907 4920,859 4962,817 5038,817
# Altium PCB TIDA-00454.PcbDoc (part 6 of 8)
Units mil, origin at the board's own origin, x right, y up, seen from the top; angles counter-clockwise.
Board outline 6159 x 2859 mil, 2 copper layers (Top Layer, Bottom Layer), stack 62 mil thick; 328 components, 224 nets, 884 pads, 184 vias.

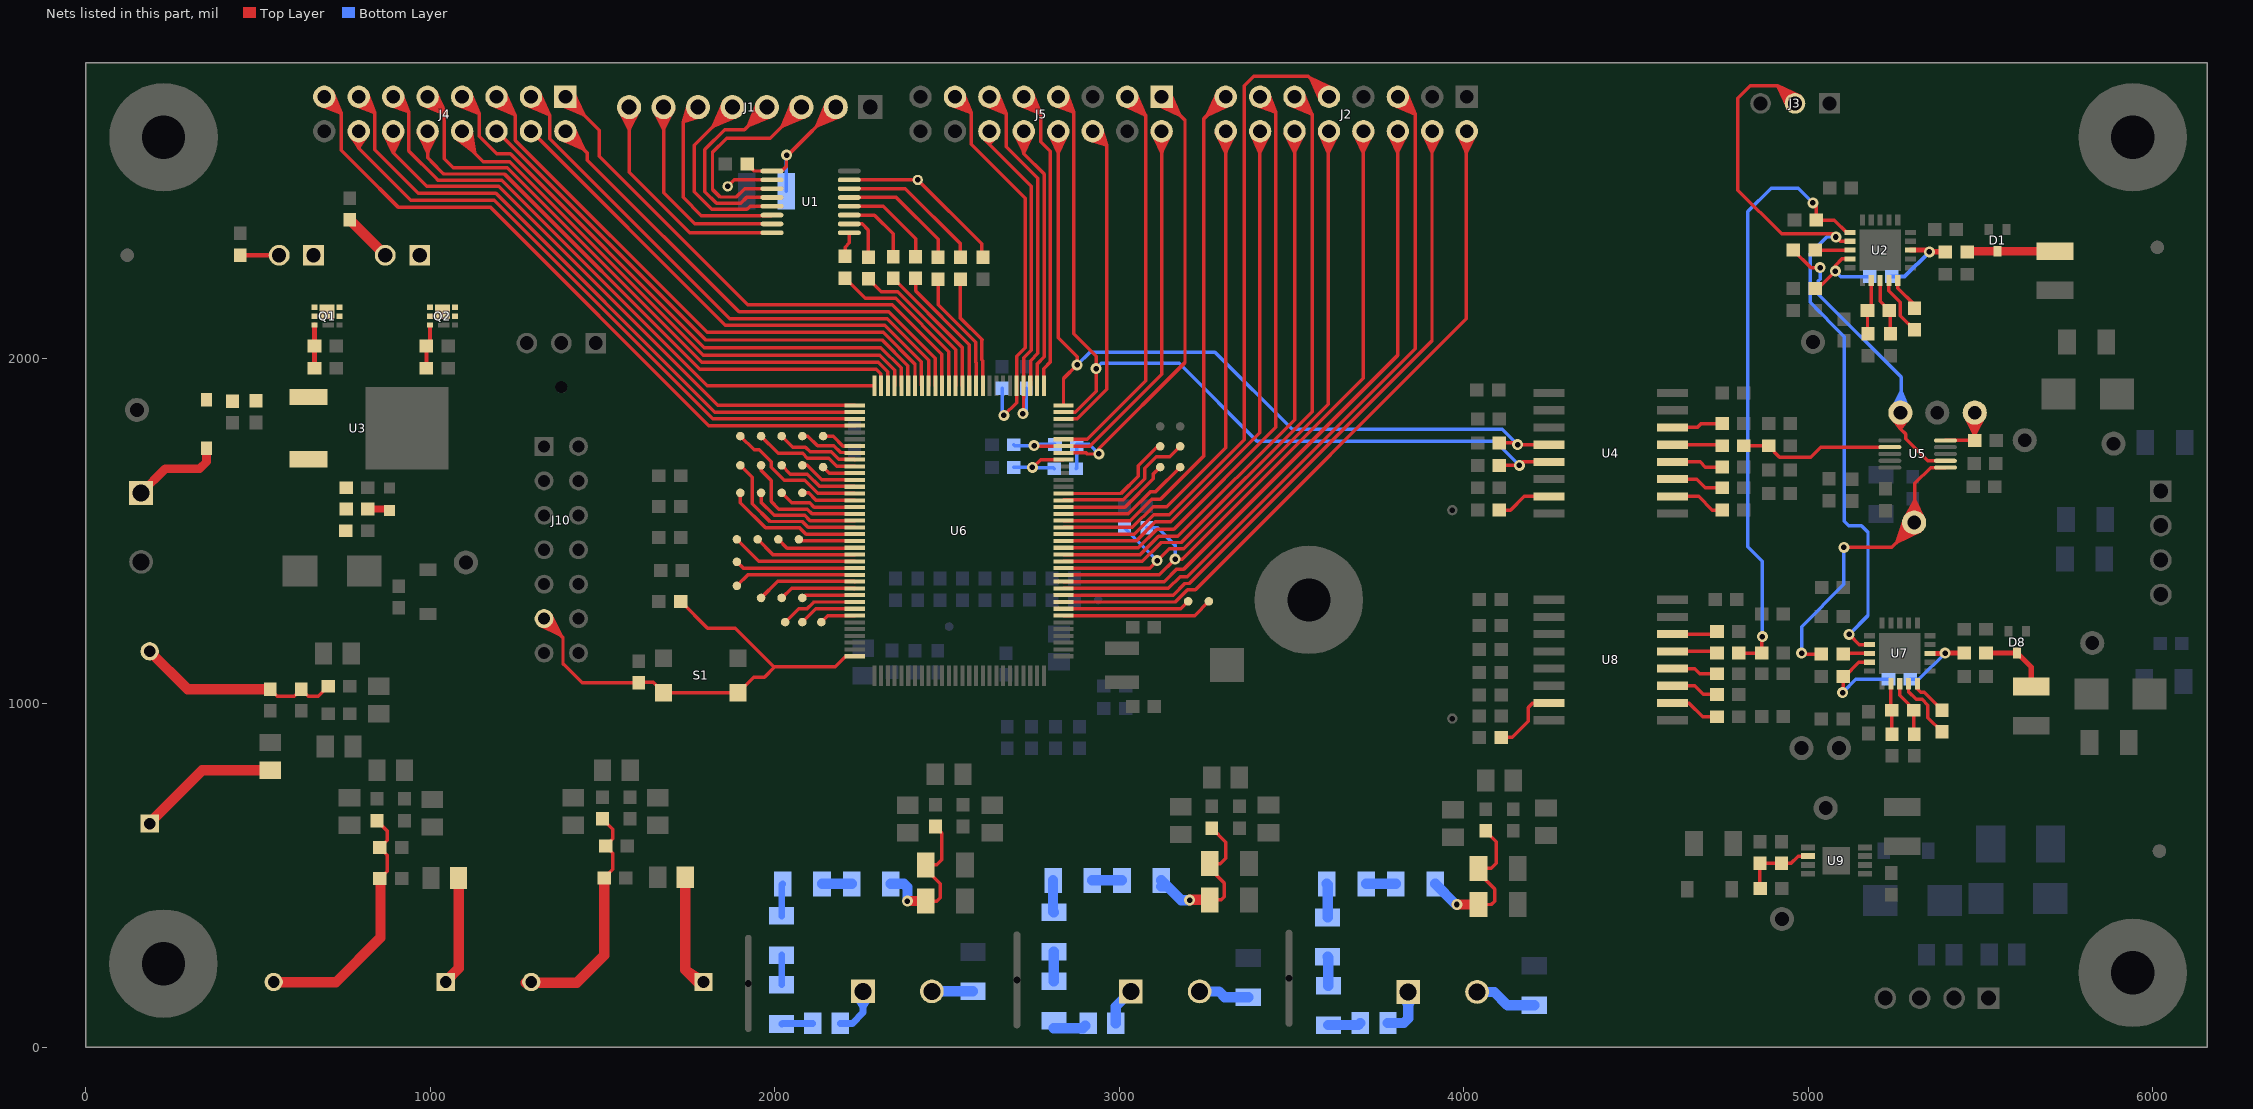
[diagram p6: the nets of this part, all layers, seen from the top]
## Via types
v1: diameter 32, hole 16, Top Layer to Bottom Layer, tented both sides, 168 vias
v2: diameter 40, hole 20, Top Layer to Bottom Layer, tented both sides, 8 vias
v3: diameter 24, hole 12, Top Layer to Bottom Layer, tented both sides, 8 vias

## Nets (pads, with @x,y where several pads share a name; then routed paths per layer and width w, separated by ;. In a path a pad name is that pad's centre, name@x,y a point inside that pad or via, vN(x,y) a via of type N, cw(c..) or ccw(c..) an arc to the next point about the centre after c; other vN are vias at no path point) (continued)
M2_XTR2_ISO: R2.1 R49.1 R55.2 U2.1 | length 1768.4
  Top Layer w10: R55.2@4798.5,1145 R49.1@4865.5,1145 v1@4865.5,1191.5 ; v1(5014,2452) 5023.5,2442.5 R2.1@5023.5,2402 5050,2402 5076.47,2402 5112.32,2366.15 U2.1@5121.15,2366.15
  Top Layer w20: v1@4865.5,1191.5 v1(4867,1193)
  Bottom Layer w10: v1(4867,1193) 4867,1412 4825,1454 4825,2427 4893,2495 4971,2495 v1(5014,2452)
NetC4_1: C4.1 Q1.3 R18.2 | length 125.2
  Top Layer w15: R18.2@663.5,1972 Q1.3@663.5,2097.23
NetC5_1: C5.1 Q2.3 R19.2 | length 129.6
  Top Layer w12: R19.2@988.5,1972 C5.1@988.5,2036 998.68,2046.18 Q2.3@998.68,2097.41
NetC6_1: C6.1 R16.2 U2.8 | length 167.7
  Top Layer w10: U2.8@5209.15,2226.85 5209.15,2166.35 C6.1@5235.5,2140 5239,2136.5 R16.2@5239,2071.5
NetC6_2: C6.2 R15.2 U2.7 | length 160.5
  Top Layer w10: R15.2@5174,2071.5 5172.5,2072.99 C6.2@5172.5,2140 5183.55,2151.05 U2.7@5183.55,2226.85
NetC7_1: C7.1 C8.1 D5.1 U3.1
NetC12_1: C12.1 FB2.1 R33.2 U3.3
NetC26_1: C26.1 R71.2 U7.8 | length 163.9
  Top Layer w10: U7.8@5266,1055.9 5266,1022.5 5306.5,982 C26.1@5306.5,979 5306.5,911.3 R71.2@5308.3,909.5
NetC26_2: C26.2 R70.2 U7.7 | length 147.8
  Top Layer w10: U7.7@5240.4,1055.9 5240.4,982.1 C26.2@5243.5,979 5243.5,909.7 R70.2@5243.3,909.5
NetC43_1: C43.1 R90.1 R97.1 U9.2 | length 222.3
  Top Layer w10: R97.1@4860.5,461 4860,461.5 R90.1@4860,534.5 C43.1@4923,534.5 4950.5,534.5 4971.4,555.4 U9.2@4999.9,555.4
NetC47_1: C47.1 R13.1 U2.13 | length 242.7
  Top Layer w12: v1@5347.05,2314.95 v1(5352,2310)
  Top Layer w15: U2.13@5297.15,2314.95 v1@5347.05,2314.95 ; v1(5352,2310) R13.1@5398.5,2310
  Bottom Layer w12: C47.1@5242.5,2238 5280,2238 v1(5352,2310)
NetC47_2: C47.2 R14.2 U2.4 | length 252.9
  Top Layer w10: R14.2@5020.5,2203 5028,2203 v1(5079,2254) 5079,2270 5098.35,2289.35 U2.4@5121.15,2289.35
  Bottom Layer w10: v1(5079,2254) 5095,2238 C47.2@5179.5,2238
NetC71_1: C71.1 R57.1 U7.13 | length 232.9
  Top Layer w10: v1@5397,1144 v1(5398,1145)
  Top Layer w15: U7.13@5354,1144 v1@5397,1144 ; v1(5398,1145) R57.1@5453.5,1145
  Bottom Layer w10: C71.1@5296.5,1068.9 5321.9,1068.9 v1(5398,1145)
NetC71_2: C71.2 R63.2 U7.4 | length 293.4
  Top Layer w10: v1(5100,1030) 5097,1033 5101.5,1037.5 R63.2@5101.5,1077 5105.98,1077 5147.38,1118.4 U7.4@5178,1118.4
  Bottom Layer w10: v1(5100,1030) 5138.9,1068.9 C71.2@5233.5,1068.9
NetD1_3: D1.3 FB1.1 R13.2 | length 260.6
  Top Layer w12: D1.3@5550,2311.5 D1.3@5553,2308.5
  Top Layer w25: R13.2@5461.5,2310 5463,2311.5 D1.3@5550,2311.5 5716.42,2311.5 FB1.1@5717,2312.09
NetD2_1: D2.1 Q1.1 Q1.2 Q1.5 Q1.6 Q1.8
NetD2_2: D2.2 R4.1 | length 113.2
  Top Layer w12: R4.1@448,2300.5 448.5,2300 D2.2@561,2300
NetD3_1: D3.1 Q2.1 Q2.2 Q2.5 Q2.6 Q2.8
NetD3_2: D3.2 R1.1 | length 145.5
  Top Layer w30: R1.1@766,2402.5 766.5,2402.5 D3.2@869,2300
NetD5_2: D5.2 J8.1 | length 266.4
  Top Layer w25: J8.1@160,1610 230,1680 330,1680 350,1700 D5.2@350,1739.13
NetD6_2: D6.2 R33.1 | length 69
  Top Layer w20: R33.1@808.5,1563 D6.2@877.52,1563
NetD8_3: D8.3 FB3.1 R57.2 | length 226
  Top Layer w12: D8.3@5606.5,1145 D8.3@5607,1145.5
  Top Layer w15: R57.2@5516.5,1145 D8.3@5606.5,1145 ; D8.3@5607,1145.5 5648,1104.5 FB3.1@5648,1048.09 FB3.1@5627.09,1048.09
NetJ3_2: J3.2 U2.2 U7.2 | length 2642
  Top Layer w10: J3.2@4941.53,2726.65 4911,2792 ; J3.2@4950.35,2731.55 4911,2792 ; J3.2@4971.45,2752.65 4911,2792 ; J3.2@4976.35,2761.47 4911,2792 ; v1(5119,1199.02) 5148.42,1169.6 U7.2@5178,1169.6 ; U2.2@5121.15,2340.55 5093.45,2340.55 v1(5081,2353) 5072,2362 4923,2362 4796,2489 4796,2756 4832,2792 4911,2792 ; 4911,2792 J3.2@4962,2741 4911,2792
  Bottom Layer w10: 5034,2135 5006,2163 ; v1(5081,2353) 5054,2353 5006,2305 5006,2163 ; v1(5119,1199.02) 5174,1254.02 5174,1496 5155,1515 5117.99,1515 5105,1527.99 5105,2064 5006,2163
NetJ11_1: J11.1 R123.1 | length 278.8
  Bottom Layer w20: R123.1@2190,70 2225,70 2256,101 J11.1@2256,163 2256,117 ; J11.1@2232.43,156.5 2256,117 ; J11.1@2279.57,156.5 2256,117
NetJ11_2: J11.2 R120.1 | length 119
  Bottom Layer w30: J11.2@2456,163 2574.91,163 R120.1@2575,162.91
NetJ12_1: J12.1 R125.1 | length 110.5
  Bottom Layer w30: R125.1@2990,70 2990,118.86 J12.1@3033.62,162.48
NetJ12_2: J12.2 R128.1 | length 148.1
  Bottom Layer w30: J12.2@3233.62,162.48 3289.62,162.48 3306.71,145.39 R128.1@3374.62,145.39
NetJ13_1: J13.1 R127.1 | length 215.1
  Bottom Layer w30: R127.1@3780,71 3826,71 3839,84 J13.1@3839,161 ; J13.1@3825.25,147.25 cw(c3792.05,114.05) 3839,114.05 cw(c3885.95,114.05) J13.1@3852.75,147.25
NetJ13_2: J13.2 R130.1 | length 181.8
  Bottom Layer w30: J13.2@4039,161 4089,161 4127.09,122.91 R130.1@4205,122.91
NetR10_2: R10.2 TP2.1 U1.7 | length 504.3
  Top Layer w10: U1.7@2216.2,2518.98 2414.62,2518.98 TP2.1@2415,2518.6 2600.3,2333.3 R10.2@2600.3,2289.96
NetR12_1: R12.1 TP4.1 U5.2 | length 1593.4
  Top Layer w10: R12.1@4957.5,2315 5008.5,2264 v1@5030,2264 ; TP4.1@5239.61,1833.3 5268,1796.63 ; TP4.1@5248.47,1838.69 5268,1796.63 ; TP4.1@5258.06,1841.92 5268,1796.63 ; TP4.1@5277.94,1841.92 5268,1796.63 ; TP4.1@5287.53,1838.69 5268,1796.63 ; TP4.1@5296.39,1833.3 5268,1796.63 ; U5.2@5398.71,1703.31 5347.67,1703.31 5283.56,1767.43 5283.56,1781.08 5268,1796.63 ; 5268,1796.63 TP4.1@5268,1843 5268,1796.63
  Bottom Layer w10: v1(5035,2264) 5035,2230.5 5030,2225.5 5030,2187 5270.5,1946.5 5270.5,1845.5 TP4.1@5268,1843 5270.5,1904.05 ; TP4.1@5242.84,1849.57 5270.5,1904.05 ; TP4.1@5252.24,1845.74 5270.5,1904.05 ; TP4.1@5262.02,1843.54 5270.5,1904.05 ; TP4.1@5274,1843.05 5270.5,1904.05 ; TP4.1@5283.93,1844.44 5270.5,1904.05 ; TP4.1@5293.61,1847.49 5270.5,1904.05
NetR12_2: R12.2 U2.3 | length 100.7
  Top Layer w10: R12.2@5020.5,2315 R12.2@5020.5,2315 U2.3@5121.15,2314.95
NetR17_1: R17.1 U2.9 | length 174.1
  Top Layer w10: U2.9@5234.75,2226.85 5234.75,2197.23 5267.98,2164 5267.98,2124.52 R17.1@5309,2083.5
NetR17_2: R17.2 U2.10 | length 100.5
  Top Layer w10: U2.10@5260.35,2226.85 5260.35,2204.65 5309,2156 R17.2@5309,2146.5
NetR23_1: R23.1 U4.14 | length 153.9
  Top Layer w10: U4.14@4601.13,1800 U4.14@4606.14,1800 4678,1800 4689,1811 R23.1@4750.5,1811
NetR25_1: R25.1 U4.13 | length 151.4
  Top Layer w10: U4.13@4601.13,1750 4745.5,1750 R25.1@4750.5,1745
NetR29_1: R29.1 U4.12 | length 155.6
  Top Layer w10: U4.12@4601.13,1700 4687,1700 4702,1685 R29.1@4750.5,1685
NetR32_1: R32.1 TP6.1 U5.5 | length 621.2
  Top Layer w10: U5.5@5398.71,1762.37 5483.13,1762.37 R32.1@5483.5,1762 5483.5,1842.5 TP6.1@5484,1843 R32.1@5483.5,1778 ; TP6.1@5454.76,1836.3 R32.1@5483.5,1778 ; TP6.1@5464.22,1840.07 R32.1@5483.5,1778 ; TP6.1@5474.02,1842.31 R32.1@5483.5,1778 ; TP6.1@5493.96,1842.15 R32.1@5483.5,1778 ; TP6.1@5503.74,1839.77 R32.1@5483.5,1778 ; TP6.1@5513.14,1835.85 R32.1@5483.5,1778
NetR35_2: R35.2 U4.7 | length 155.9
  Top Layer w10: R35.2@4103.5,1560 4136,1560 4176,1600 U4.7@4242.87,1600
NetR36_1: R36.1 U4.10 | length 165.9
  Top Layer w10: U4.10@4601.13,1600 4682,1600 4722,1560 R36.1@4750.5,1560
NetR50_1: R50.1 U4.11 | length 159.7
  Top Layer w10: U4.11@4601.13,1650 4677,1650 4702,1625 R50.1@4750.5,1625
NetR51_2: R51.2 R58.2 R59.2 T1.3 | length 593.8
  Top Layer w10: R58.2@535,1040.3 555.3,1020 604.7,1020 R59.2@625,1040.3 645.3,1020 674.7,1020 R51.2@703.5,1048.8
  Top Layer w30: T1.3@184,1151 295,1040 R58.2@526.2,1040
NetR54_1: R54.1 U8.14 | length 131.4
  Top Layer w10: U8.14@4606.13,1200 4730.5,1200 R54.1@4735.5,1205
NetR55_1: R55.1 U8.13 | length 131.4
  Top Layer w10: U8.13@4606.13,1150 4730.5,1150 R55.1@4735.5,1145
NetR62_1: R62.1 U8.12 | length 135.6
  Top Layer w10: U8.12@4606.13,1100 4671,1100 4686,1085 R62.1@4735.5,1085
NetR64_1: R64.1 TP30.1 U5.1 | length 1873.4
  Top Layer w10: v1(4981,1145) 4984,1142 R64.1@5038.5,1142 ; v1(5104,1452) 5243.32,1452 5304.5,1513.18 5304.5,1527.5 5310,1533 5310,1637.8 5355.83,1683.63 U5.1@5398.71,1683.63 ; TP30.1@5279.03,1531.81 5310,1589.04 ; TP30.1@5282.01,1538.98 5257.16,1465.84 ; TP30.1@5288.34,1527.68 5310,1589.04 ; TP30.1@5291.36,1535.1 5257.16,1465.84 ; TP30.1@5298.06,1525.07 5310,1589.04 ; TP30.1@5300.06,1530.08 5257.16,1465.84 ; TP30.1@5315.09,1516.95 5257.16,1465.84 ; TP30.1@5317.99,1524.46 5310,1589.04 ; TP30.1@5321.23,1509 5257.16,1465.84 ; TP30.1@5326.32,1500.25 5257.16,1465.84 ; TP30.1@5327.85,1526.46 5310,1589.04 ; TP30.1@5337.39,1530.02 5310,1589.04 ; 5257.16,1465.84 TP30.1@5308,1524 5310,1589.04
  Bottom Layer w10: v1(4981,1145) 4981,1221.99 5104,1344.99 v1(5104,1452)
NetR64_2: R64.2 U7.3 | length 74.5
  Top Layer w10: R64.2@5103.5,1144 U7.3@5178,1144
NetR65_1: R65.1 U7.9 | length 190.3
  Top Layer w10: U7.9@5291.6,1055.9 5291.6,1032.4 5313.5,1010.5 5331.48,1010.5 5348,993.98 5348,957.5 R65.1@5389,916.5
NetR65_2: R65.2 U7.10 | length 111.7
  Top Layer w10: U7.10@5317.2,1055.9 5317.2,1041.8 5327.5,1031.5 5337,1031.5 R65.2@5389,979.5
NetR67_1: R67.1 U8.11 | length 139.7
  Top Layer w10: U8.11@4606.13,1050 4671,1050 4696,1025 R67.1@4735.5,1025
NetR72_2: R72.2 U8.7 | length 204.2
  Top Layer w10: R72.2@4108.5,900 4141,900 4188,947 4188,987 4201,1000 U8.7@4247.87,1000
NetR73_1: R73.1 U8.10 | length 145.9
  Top Layer w10: U8.10@4606.13,1000 4654,1000 4694,960 R73.1@4735.5,960
NetR75_2: R75.2 R85.2 R92.2 T2.3 | length 853.7
  Top Layer w10: R75.2@845,658.5 875,628.5 875,601.5 R85.2@853.5,580 875,558.5 875,511.5 R92.2@853.5,490
  Top Layer w30: T2.3@541,189 726,189 855,318 R92.2@855,480 ; T2.3@545,190 661.67,189
NetR77_2: R77.2 R86.2 R93.2 T3.3 | length 805
  Top Layer w10: R77.2@1500,663.5 1530,633.5 1530,606.5 R86.2@1508.5,585 1530,563.5 1530,517.8 R93.2@1504.2,492
  Top Layer w30: T3.3@1277,188 1425,188 1505,268 R93.2@1505,482.7 ; T3.3@1292.95,190 1409.64,188
NetR79_2: R79.2 R87.1 R94.1 R112.2 | length 461.3
  Top Layer w10: R94.1@2437.91,425 2470,425 2480,435 2480,475 2437.91,517.09 R87.1@2437.91,530 2470,530 2485,545 2485,622.5 R79.2@2466,641.5
  Top Layer w30: v1(2385,425) R94.1@2437.91,425
  Bottom Layer w30: R112.2@2337.09,475 2375,475 2385,465 v1(2385,425)
NetR81_2: R81.2 R88.1 R95.1 R114.2 | length 500
  Top Layer w10: R95.1@3262.54,428.5 3295.65,428.5 3304.62,437.48 3304.62,477.48 3262.54,519.57 R88.1@3262.54,533.5 3293.6,533.5 3309.62,549.53 3309.62,596.01 R81.2@3268.62,637.01
  Top Layer w30: v1(3204.62,427.48) 3205.65,428.5 R95.1@3262.54,428.5
  Bottom Layer w30: R114.2@3121.71,467.48 R114.2@3139.61,467.48 ; R114.2@3122.09,485 R114.2@3139.61,467.48 ; v1(3204.62,427.48) 3179.61,427.48 R114.2@3139.61,467.48
NetR83_2: R83.2 R89.1 R96.1 R116.2 | length 481.1
  Top Layer w10: R96.1@4042.91,415 4080,415 4090,425 4090,460 4042.91,507.09 R89.1@4042.91,520 4080,520 4095,535 4095,597.5 R83.2@4064,628.5
  Top Layer w30: v1(3980,415) R96.1@4042.91,415
  Bottom Layer w30: R116.2@3917.09,475 3977.09,415 v1(3980,415)
NetR102_2: R102.2 R103.2 U6.30 | length 219.2
  Top Layer w10: v1(2748,1684) 2749,1684 2771.69,1706.69 U6.30@2838.15,1706.69
  Bottom Layer w10: R102.2@2693.5,1684 v1(2748,1684) 2749,1683 2808.5,1683 R103.2@2811.5,1680
NetR111_1: R111.1 R117.2 | length 94.1
  Bottom Layer w20: R117.2@2020,382.09 2020,472.09 R111.1@2022.91,475
NetR111_2: R111.2 R112.1 | length 85.8
  Bottom Layer w30: R111.2@2137.09,475 R112.1@2222.91,475
NetR113_1: R113.1 R118.2 | length 93.8
  Bottom Layer w30: R113.1@2807.91,485 2807.91,394.17 R118.2@2810,392.09
NetR113_2: R113.2 R114.1 | length 85.8
  Bottom Layer w30: R113.2@2922.09,485 R114.1@3007.91,485
NetR115_1: R115.1 R119.2 | length 98.8
  Bottom Layer w30: R115.1@3602.91,475 3605,472.91 R119.2@3605,377.09
NetR115_2: R115.2 R116.1 | length 85.8
  Bottom Layer w30: R115.2@3717.09,475 R116.1@3802.91,475
NetR117_1: R117.1 R122.2 | length 85.8
  Bottom Layer w20: R122.2@2020,182.09 R117.1@2020,267.91
NetR118_1: R118.1 R124.2 | length 85.8
  Bottom Layer w30: R124.2@2810,192.09 R118.1@2810,277.91
NetR119_1: R119.1 R126.2 | length 84.7
  Bottom Layer w30: R119.1@3605,262.91 3607,260.91 R126.2@3607,179.09
NetR121_1: R121.1 T1.1 | length 414.8
  Top Layer w30: T1.1@184,651 338,805 R121.1@535,805
NetR122_1: R122.1 R123.2 | length 90.9
  Bottom Layer w20: R122.1@2020,67.91 2022.09,70 R123.2@2110,70
NetR124_1: R124.1 R125.2 | length 95.3
  Bottom Layer w30: R124.1@2809.62,55.39 2894.02,55.39 R125.2@2901.69,63.07
NetR126_1: R126.1 R127.2 | length 95.5
  Bottom Layer w30: R126.1@3607,64.91 3693.91,64.91 R127.2@3700,71
NetR129_1: R129.1 T2.1 | length 374.5
  Top Layer w30: T2.1@1041,189 1082,230 ; T2.1@1045,190 1082,230 ; R129.1@1082,492 1082,230
NetR131_1: R131.1 T3.1 | length 384.8
  Top Layer w30: R131.1@1740,494 1740,225 ; T3.1@1777,188 1740,225 ; T3.1@1792.95,190 1740,225
NetTP1_1: TP1.1 U1.10 | length 136.7
  Top Layer w10: TP1.1@1863,2500 1881.98,2518.98 U1.10@1991.8,2518.98
NetTP10_1: TP10.1 U6.78 | length 410.2
  Top Layer w10: TP10.1@1900,1775 1940,1735 1955,1735 1990,1700 1990,1684.22 2027.52,1646.7 2086.81,1646.7 2124.27,1609.25 2230.87,1609.25 U6.78@2231.85,1608.27
NetTP11_1: TP11.1 U6.74 | length 308.3
  Top Layer w10: TP11.1@1960,1775 2010,1725 2080.78,1725 2094.78,1711 2156.7,1711 2179.71,1687.99 2230.87,1687.99 U6.74@2231.85,1687.01
NetTP12_1: TP12.1 U6.73 | length 240.1
  Top Layer w10: TP12.1@2020,1775 2052,1743 2089,1743 2103,1729 2164.15,1729 2185.48,1707.67 2230.87,1707.67 U6.73@2231.85,1706.69
NetTP13_1: TP13.1 U6.72 | length 172
  Top Layer w10: TP13.1@2080,1775 2096,1775 2124,1747 2171.61,1747 2191.25,1727.36 2230.87,1727.36 U6.72@2231.85,1726.38
NetTP14_1: TP14.1 U6.71 | length 103.8
  Top Layer w10: TP14.1@2140,1775 2169.06,1775 2198,1746.06 U6.71@2231.85,1746.06
NetTP15_1: TP15.1 U6.24 | length 421.4
  Top Layer w10: U6.24@2838.15,1588.58 2839.13,1589.56 3011.83,1589.56 3073.7,1651.43 3073.7,1681.7 3107,1715 3147,1715 TP15.1@3177,1745
NetTP16_1: TP16.1 U6.25 | length 355.2
  Top Layer w10: U6.25@2838.15,1608.27 3005.08,1608.27 3055.7,1658.89 3055.7,1689.16 3111.54,1745 TP16.1@3119,1745
NetTP18_1: TP18.1 U6.84 | length 397.9
  Top Layer w10: TP18.1@1900,1610 1900,1582 1973,1509 2071.78,1509 2090.62,1490.16 U6.84@2231.85,1490.16
NetTP19_1: TP19.1 U6.83 | length 451.6
  Top Layer w10: TP19.1@1900,1690 1934.7,1655.3 1934.7,1578.3 1986,1527 2079.24,1527 2096.39,1509.84 U6.83@2231.85,1509.84
NetTP20_1: TP20.1 U6.82 | length 321
  Top Layer w10: TP20.1@1960,1610 1960,1583 1998,1545 2086.69,1545 2102.16,1529.53 U6.82@2231.85,1529.53
NetTP21_1: TP21.1 U6.81 | length 374.1
  Top Layer w10: TP21.1@1960,1690 1960,1676 1990,1646 1990,1585 2012,1563 2094.15,1563 2107.93,1549.21 U6.81@2231.85,1549.21
NetTP22_1: TP22.1 U6.80 | length 228.9
  Top Layer w10: TP22.1@2020,1610 2049,1581 2101.6,1581 2113.71,1568.9 U6.80@2231.85,1568.9
NetTP23_1: TP23.1 U6.79 | length 160.7
  Top Layer w10: TP23.1@2080,1610 2098.06,1610 2119.48,1588.58 U6.79@2231.85,1588.58
NetTP24_1: TP24.1 U6.77 | length 237.6
  Top Layer w10: TP24.1@2020,1690 2045.3,1664.7 2094.27,1664.7 2130.27,1628.7 2231.1,1628.7 U6.77@2231.85,1627.95
NetTP25_1: TP25.1 U6.76 | length 169.4
  Top Layer w10: TP25.1@2080,1690 2094.43,1690 2135.81,1648.62 2230.87,1648.62 U6.76@2231.85,1647.64
NetTP26_1: TP26.1 U6.75 | length 99.2
  Top Layer w10: TP26.1@2140,1685 2157.68,1667.32 U6.75@2231.85,1667.32
NetTP27_1: TP27.1 U6.22 | length 395.1
  Top Layer w10: U6.22@2838.15,1549.21 3026.51,1549.21 3091.29,1614 3106,1614 TP27.1@3177,1685
NetTP28_1: TP28.1 U6.23 | length 337
  Top Layer w10: U6.23@2838.15,1568.9 3016.62,1568.9 3099,1651.28 3099,1665 TP28.1@3119,1685
NetTP31_1: TP31.1 U6.88 | length 368.2
  Top Layer w10: TP31.1@1890,1475 1953.58,1411.42 U6.88@2231.85,1411.42
NetTP32_1: TP32.1 U6.89 | length 350
  Top Layer w10: TP32.1@1890,1410 1909,1391 2231.12,1391 U6.89@2231.85,1391.73
NetTP34_1: TP34.1 U6.90 | length 355.1
  Top Layer w10: TP34.1@1890,1340 1922.05,1372.05 U6.90@2231.85,1372.05
NetTP35_1: TP35.1 U6.93 | length 155.2
  Top Layer w10: TP35.1@2080,1305 2087.99,1312.99 U6.93@2231.85,1312.99
NetTP36_1: TP36.1 U6.87 | length 300
  Top Layer w10: TP36.1@1950,1475 1993.9,1431.1 U6.87@2231.85,1431.1
NetTP37_1: TP37.1 U6.86 | length 232.8
  Top Layer w10: TP37.1@2010,1475 2035.3,1449.7 2196.91,1449.7 2197.02,1449.81 2230.87,1449.81 U6.86@2231.85,1450.79
NetTP38_1: TP38.1 U6.85 | length 163.7
  Top Layer w10: TP38.1@2070,1475 2074.53,1470.47 U6.85@2231.85,1470.47
NetTP39_1: TP39.1 U6.94 | length 242
  Top Layer w10: TP39.1@2030,1235 2069,1274 ; 2085,1274 2069,1274 ; U6.94@2231.85,1293.31 2113.31,1293.31 2111.62,1291.62 2111.17,1291.62 2093.54,1274 2069,1274
NetTP40_1: TP40.1 U6.91 | length 292.2
  Top Layer w10: TP40.1@1960,1305 2008.3,1353.3 2230.91,1353.3 U6.91@2231.85,1352.36
NetTP41_1: TP41.1 U6.95 | length 167.8
  Top Layer w10: TP41.1@2080,1235 2118.62,1273.62 U6.95@2231.85,1273.62
NetTP42_1: TP42.1 U6.96 | length 104.7
  Top Layer w10: TP42.1@2135,1235 2153.94,1253.94 2158.94,1253.94 2190,1253.94 U6.96@2231.85,1253.94
NetTP43_1: TP43.1 U6.92 | length 225.1
  Top Layer w10: TP43.1@2020,1305 2048.66,1333.66 2230.87,1333.66 U6.92@2231.85,1332.68 U6.92@2231.17,1332
NetTP44_1: TP44.1 U6.8 | length 370.7
  Top Layer w10: U6.8@2838.15,1273.62 3178.62,1273.62 TP44.1@3200,1295
NetTP45_1: TP45.1 U6.7 | length 438.9
  Top Layer w10: U6.7@2838.15,1253.94 3218.94,1253.94 TP45.1@3260,1295
OUT1: J1.8 U1.16 | length 1131.8
  Top Layer w10: J1.8@1547.77,2723.06 1577,2664.96 ; J1.8@1557.2,2726.91 1577,2664.96 ; J1.8@1566.99,2729.23 1577,2664.96 ; J1.8@1587.01,2729.23 1577,2664.96 ; J1.8@1596.8,2726.91 1577,2664.96 ; J1.8@1606.23,2723.06 1577,2664.96 ; U1.16@1991.8,2365.43 1752.57,2365.43 1577,2541 J1.8@1577,2730 1577,2664.96
OUT2: J1.7 U1.15 | length 1055.8
  Top Layer w10: J1.7@1647.77,2723.06 1677,2664.96 ; J1.7@1657.2,2726.91 1677,2664.96 ; J1.7@1666.99,2729.23 1677,2664.96 ; J1.7@1687.01,2729.23 1677,2664.96 ; J1.7@1696.8,2726.91 1677,2664.96 ; J1.7@1706.23,2723.06 1677,2664.96 ; U1.15@1991.8,2391.02 1768,2391 1677,2482 J1.7@1677,2730 1677,2664.96
OUT3: J1.6 U1.14 | length 988.2
  Top Layer w10: J1.6@1751.19,2745.37 1733.77,2686.77 ; J1.6@1760.7,2741.66 1733.77,2686.77 ; J1.6@1769.34,2736.49 1733.77,2686.77 ; J1.6@1783.49,2722.34 1733.77,2686.77 ; J1.6@1788.66,2713.7 1733.77,2686.77 ; J1.6@1792.37,2704.19 1733.77,2686.77 ; U1.14@1991.8,2416.61 1990.38,2415.2 1786.8,2415.2 1733.77,2468.23 1733.77,2686.77 ; 1733.77,2686.77 J1.6@1777,2730 1733.77,2686.77
OUT4: J1.5 U1.13 | length 1019.2
  Top Layer w10: J1.5@1852.13,2746.85 1820.75,2673.75 ; J1.5@1861.16,2742.27 1820.75,2673.75 ; J1.5@1869.47,2736.64 1820.75,2673.75 ; J1.5@1877,2730 1766.5,2619.5 1766.5,2484 1817.3,2433.2 1919.2,2433.2 1928.2,2442.2 U1.13@1991.8,2442.2 ; J1.5@1883.64,2722.47 1820.75,2673.75 ; J1.5@1889.27,2714.16 1820.75,2673.75 ; J1.5@1893.85,2705.13 1820.75,2673.75
OUT5: J1.4 U1.12 | length 1113.1
  Top Layer w10: J1.4@1952.06,2746.74 1922,2675 ; J1.4@1961.12,2742.23 1922,2675 ; J1.4@1969.46,2736.63 1922,2675 ; J1.4@1983.63,2722.46 1922,2675 ; J1.4@1989.23,2714.12 1922,2675 ; U1.12@1991.8,2467.8 1917.8,2467.8 1901.2,2451.2 1830.8,2451.2 1797,2485 1797,2607 1855,2665 1912,2665 J1.4@1977,2730 1922,2675 ; J1.4@1993.74,2705.06 1922,2675
OUT6: J1.3 U1.11 | length 1169
  Top Layer w10: U1.11@1991.8,2493.39 1912.39,2493.39 1888.2,2469.2 1840.8,2469.2 1819,2491 1819,2599 1860,2640 1987,2640 J1.3@2077,2730 2020.75,2673.75 ; J1.3@2052.13,2746.85 2020.75,2673.75 ; J1.3@2061.16,2742.27 2020.75,2673.75 ; J1.3@2069.47,2736.64 2020.75,2673.75 ; J1.3@2083.64,2722.47 2020.75,2673.75 ; J1.3@2089.27,2714.16 2020.75,2673.75 ; J1.3@2093.85,2705.13 2020.75,2673.75
P1.0: J2.5 U6.11 | length 2495.2
  Top Layer w10: U6.11@2838.15,1332.68 3142.68,1332.68 3177,1367 3198,1367 3860,2029 3860,2709 ; J2.5@3793.63,2737.22 3860,2709 ; J2.5@3798.23,2746.23 3860,2709 ; J2.5@3803.99,2754.44 3860,2709 ; J2.5@3809,2760 3860,2709 ; J2.5@3814.56,2765.01 3860,2709 ; J2.5@3822.77,2770.77 3860,2709 ; J2.5@3831.78,2775.37 3860,2709
P1.1: J2.4 U6.10 | length 2421.7
  Top Layer w10: U6.10@2838.15,1312.99 3156.76,1312.99 3190.76,1347 3203.46,1347 3908,2051.54 J2.4@3908,2660 ; J2.4@3882.1,2654.39 3908,2597.51 ; J2.4@3891.65,2657.83 3908,2597.51 ; J2.4@3901.53,2659.67 3908,2597.51 ; J2.4@3909,2660 3908,2597.51 ; J2.4@3916.46,2659.43 3908,2597.51 ; J2.4@3926.27,2657.28 3908,2597.51 ; J2.4@3935.71,2653.53 3908,2597.51
P1.2: J2.2 U6.9 | length 2505.8
  Top Layer w10: U6.9@2838.15,1293.31 3162.53,1293.31 3198.22,1329 3221.46,1329 4008,2115.54 4008,2672 J2.2@4009,2673 ; J2.2@3982.1,2654.39 4008,2597.51 ; J2.2@3991.65,2657.83 4008,2597.51 ; J2.2@4001.53,2659.67 4008,2597.51 ; J2.2@4009,2660 4008,2597.51 ; J2.2@4016.46,2659.43 4008,2597.51 ; J2.2@4026.27,2657.28 4008,2597.51 ; J2.2@4035.71,2653.53 4008,2597.51
P2.4: J2.6 U6.12 | length 2330.4
  Top Layer w10: U6.12@2838.15,1352.36 3130.87,1352.36 3167.5,1389 3188,1389 3808,2009 J2.6@3808,2660 ; J2.6@3782.1,2654.39 3808,2597.51 ; J2.6@3791.65,2657.83 3808,2597.51 ; J2.6@3801.53,2659.67 3808,2597.51 ; J2.6@3809,2660 3808,2597.51 ; J2.6@3816.46,2659.43 3808,2597.51 ; J2.6@3826.27,2657.28 3808,2597.51 ; J2.6@3835.71,2653.53 3808,2597.51
P2.7: J2.11 U6.15 | length 2270
  Top Layer w10: U6.15@2838.15,1411.42 2838.43,1411.7 3067.18,1411.7 3121.48,1466 3180.37,1466 3560,1845.63 3560,2709 ; J2.11@3493.63,2737.22 3560,2709 ; J2.11@3498.23,2746.23 3560,2709 ; J2.11@3503.99,2754.44 3560,2709 ; J2.11@3509,2760 3560,2709 ; J2.11@3514.56,2765.01 3560,2709 ; J2.11@3522.77,2770.77 3560,2709 ; J2.11@3531.78,2775.37 3560,2709
P3.2: J2.14 U6.18 | length 2012.9
  Top Layer w10: U6.18@2838.15,1470.47 3049.59,1470.47 3105.12,1526 3149.46,1526 3408,1784.54 J2.14@3408,2660 ; J2.14@3382.1,2654.39 3408,2597.51 ; J2.14@3391.65,2657.83 3408,2597.51 ; J2.14@3401.53,2659.67 3408,2597.51 ; J2.14@3409,2660 3408,2597.51 ; J2.14@3416.46,2659.43 3408,2597.51 ; J2.14@3426.27,2657.28 3408,2597.51 ; J2.14@3435.71,2653.53 3408,2597.51
P4.3: J5.11 U6.41 | length 1322.2
  Top Layer w10: J5.11@2607.81,2737.1 2672,2711 ; J5.11@2612.3,2746.18 2672,2711 ; J5.11@2618,2754.43 2672,2711 ; J5.11@2623,2760 2672,2711 ; J5.11@2628.57,2765 2672,2711 ; J5.11@2636.82,2770.7 2672,2711 ; J5.11@2645.9,2775.19 2672,2711 ; U6.41@2741.69,1921.26 2742.67,1922.24 2742.67,1993.67 2764,2015 2764,2523 2672,2615 2672,2711
P5.5: J5.2 R100.1 R101.1 U6.32 | length 1723.6
  Top Layer w10: v1(2753,1747) 2753.94,1746.06 U6.32@2838.15,1746.06 2914.06,1746.06 3123,1955 J5.2@3123,2660 3123,2597.52 ; J5.2@3096.19,2653.96 3123,2597.52 ; J5.2@3105.69,2657.55 3123,2597.52 ; J5.2@3115.53,2659.55 3123,2597.52 ; J5.2@3130.47,2659.55 3123,2597.52 ; J5.2@3140.31,2657.55 3123,2597.52 ; J5.2@3149.81,2653.96 3123,2597.52
  Bottom Layer w10: R100.1@2693.5,1750 2696.5,1747 v1(2753,1747) 2757,1751 R101.1@2813.5,1751 R101.1@2812.5,1750
P5.6: J5.3 U6.33 | length 1611.1
  Top Layer w10: U6.33@2838.15,1765.75 2906.75,1765.75 3076.72,1935.72 3076.72,2706.28 ; J5.3@3007.41,2737.37 3076.69,2706.31 ; J5.3@3012.14,2746.3 3076.69,2706.31 ; J5.3@3017.98,2754.46 3076.69,2706.31 ; J5.3@3023,2760 3076.72,2706.28 ; J5.3@3028.54,2765.02 3076.69,2706.31 ; J5.3@3036.7,2770.86 3076.69,2706.31 ; J5.3@3045.63,2775.59 3076.69,2706.31
P7.1: J4.1 U6.54 | length 2068.2
  Top Layer w10: J4.1@1376.63,2737.22 1446.03,2706.97 ; J4.1@1381.28,2746.19 1446.03,2706.97 ; J4.1@1387.03,2754.41 1446.03,2706.97 ; J4.1@1392,2760 1446.03,2706.97 ; J4.1@1392,2761 1490,2663 1490,2588 1922,2156 2341,2156 2484.81,2012.19 2484.81,1922.24 U6.54@2485.79,1921.26 ; J4.1@1397.5,2765.07 1446.03,2706.97 ; J4.1@1405.6,2770.98 1446.03,2706.97 ; J4.1@1414.49,2775.79 1446.03,2706.97
P7.2: J4.2 U6.55 | length 1968.7
  Top Layer w10: J4.2@1376.64,2637.22 1445.94,2607.06 ; J4.2@1381.28,2646.19 1445.94,2607.06 ; J4.2@1387.03,2654.41 1445.94,2607.06 ; J4.2@1392,2660 1445.94,2607.06 ; J4.2@1392,2661 1456,2597 1456,2576 1896,2136 2331.38,2136 2466.1,2001.28 U6.55@2466.1,1921.26 ; J4.2@1397.5,2665.07 1445.94,2607.06 ; J4.2@1405.6,2670.98 1445.94,2607.06 ; J4.2@1414.49,2675.79 1445.94,2607.06
P7.3: J4.3 U6.56 | length 2114.2
  Top Layer w10: J4.3@1276.64,2737.21 1345.9,2707.1 ; J4.3@1281.28,2746.19 1345.9,2707.1 ; J4.3@1287.03,2754.41 1345.9,2707.1 ; J4.3@1292,2760 1345.9,2707.1 ; J4.3@1292,2761 1346.72,2706.28 1346.72,2638.28 1869,2116 2325.92,2116 2446.42,1995.5 U6.56@2446.42,1921.26 ; J4.3@1297.5,2765.07 1345.9,2707.1 ; J4.3@1305.61,2770.97 1345.9,2707.1 ; J4.3@1314.5,2775.78 1345.9,2707.1
P7.4: J4.4 U6.57 | length 1481.3
  Top Layer w10: J4.4@1292,2661 1856,2097 2319.47,2097 2425.75,1990.71 2425.75,1922.24 U6.57@2426.73,1921.26
P7.5: J4.5 U6.58 | length 2171
  Top Layer w10: J4.5@1176.64,2737.21 1245.9,2707.1 ; J4.5@1181.28,2746.19 1245.9,2707.1 ; J4.5@1187.03,2754.41 1245.9,2707.1 ; J4.5@1192,2760 1245.9,2707.1 ; J4.5@1192,2761 1246.72,2706.28 1246.72,2633.28 1804,2076 2315.01,2076 2407.05,1983.96 U6.58@2407.05,1921.26 ; J4.5@1197.5,2765.07 1245.9,2707.1 ; J4.5@1205.61,2770.97 1245.9,2707.1 ; J4.5@1214.5,2775.78 1245.9,2707.1
P7.6: J4.6 U6.59 | length 1535.1
  Top Layer w10: J4.6@1192,2661 1799,2054 2311.55,2054 2386.38,1979.17 2386.38,1922.24 U6.59@2387.36,1921.26
P7.7: J4.7 U6.60 | length 2181.6
  Top Layer w10: J4.7@1076.99,2736.98 1142,2711 ; J4.7@1081.42,2746.09 1142,2711 ; J4.7@1087.06,2754.39 1142,2711 ; J4.7@1092,2760 1142,2711 ; J4.7@1092,2761 1142,2711 ; J4.7@1097.51,2765.06 1142,2711 ; J4.7@1105.7,2770.86 1142,2711 ; J4.7@1114.71,2775.47 1142,2711 ; U6.60@2367.68,1921.26 2366.7,1922.24 2366.7,1973.4 2308.1,2032 1795.54,2032 1232.54,2595 1192.96,2595 1142,2645.96 1142,2711
P8.0: J4.8 U6.61 | length 2119.9
  Top Layer w10: J4.8@1071.35,2641.87 1129.38,2596.62 ; J4.8@1078.1,2649.39 1129.38,2596.62 ; J4.8@1085.76,2655.88 1129.38,2596.62 ; J4.8@1092,2660 1129.38,2596.62 ; J4.8@1092,2661 1092,2634 1154,2572 1230.09,2572 1792.09,2010 2304.64,2010 2347.99,1966.65 U6.61@2347.99,1921.26 ; J4.8@1098.63,2663.47 1129.38,2596.62 ; J4.8@1108.01,2667.03 1129.38,2596.62 ; J4.8@1117.86,2669.29 1129.38,2596.62
P8.1: J4.9 U6.62 | length 2313.9
  Top Layer w10: J4.9@976.64,2737.21 1045.9,2707.1 ; J4.9@981.28,2746.19 1045.9,2707.1 ; J4.9@987.03,2754.41 1045.9,2707.1 ; J4.9@992,2760 1045.9,2707.1 ; J4.9@992,2761 1040,2713 1040,2580 1066,2554 1222.63,2554 1787.63,1989 2300.19,1989 2327.33,1961.86 2327.33,1922.24 U6.62@2328.31,1921.26 ; J4.9@997.5,2765.07 1045.9,2707.1 ; J4.9@1005.61,2770.97 1045.9,2707.1 ; J4.9@1014.5,2775.78 1045.9,2707.1
P8.2: J4.10 U6.63 | length 2152.9
  Top Layer w10: J4.10@965.19,2653.96 992,2597.52 ; J4.10@974.69,2657.55 992,2597.52 ; J4.10@984.53,2659.55 992,2597.52 ; J4.10@999.47,2659.55 992,2597.52 ; J4.10@1009.31,2657.55 992,2597.52 ; J4.10@1018.81,2653.96 992,2597.52 ; 1235,2516.18 1215.18,2536 ; U6.63@2308.62,1921.26 2307.64,1922.24 2307.64,1956.09 2294.73,1969 1782.18,1969 1215.18,2536 ; 992,2597.52 J4.10@992,2660 992,2583 1008.5,2566.5 1032,2543 1039,2536 1215.18,2536
P8.3: J4.11 U6.64 | length 2283.3
  Top Layer w10: J4.11@877.51,2736.65 937.28,2715.72 ; J4.11@881.62,2745.94 937.28,2715.72 ; J4.11@887.09,2754.35 937.28,2715.72 ; J4.11@892,2760 937.28,2715.72 ; J4.11@892,2761 937.28,2715.72 ; J4.11@897.54,2765.03 937.28,2715.72 ; J4.11@905.83,2770.69 937.28,2715.72 ; J4.11@915.02,2775.01 937.28,2715.72 ; 1227.5,2497.5 1207,2518 ; U6.64@2288.94,1921.26 1803.74,1921.26 1207,2518 ; 937.28,2715.72 937.28,2602.72 1015,2525 1022,2518 1207,2518
P8.4: J4.12 U6.65 | length 2139.8
  Top Layer w10: J4.12@865.2,2653.91 892,2598 ; J4.12@874.69,2657.54 892,2598 ; J4.12@884.53,2659.55 892,2598 ; J4.12@899.47,2659.55 892,2598 ; J4.12@909.31,2657.54 892,2598 ; J4.12@918.8,2653.91 892,2598 ; U6.65@2231.85,1864.17 1834.83,1864.17 1199,2500 990,2500 892,2598 ; 892,2598 J4.12@892,2660 892,2598
P8.5: J4.13 U6.66 | length 2343.1
  Top Layer w10: J4.13@777.31,2736.78 839,2714 ; J4.13@781.54,2745.99 839,2714 ; J4.13@787.08,2754.37 839,2714 ; J4.13@792,2760 839,2714 ; J4.13@792,2761 839,2714 ; J4.13@797.53,2765.04 839,2714 ; J4.13@805.78,2770.76 839,2714 ; J4.13@814.9,2775.19 839,2714 ; U6.66@2231.85,1844.49 1825.97,1844.49 1190.46,2480 965,2480 839,2606 839,2714
P8.6: J4.14 U6.67 | length 2158.5
  Top Layer w10: J4.14@765.62,2652.29 792,2611 ; J4.14@774.8,2656.88 792,2611 ; J4.14@784.54,2659.43 792,2611 ; J4.14@792,2661 J4.14@792,2660 ; J4.14@799.46,2659.43 792,2611 ; J4.14@809.2,2656.88 792,2611 ; J4.14@818.38,2652.29 792,2611 ; U6.67@2231.85,1824.8 1820.2,1824.8 1185,2460 943,2460 792,2611 ; 792,2611 J4.14@792,2660 ; 792,2611 J4.14@792,2660
P8.7: J4.15 U6.68 | length 2478.6
  Top Layer w10: J4.15@677.09,2736.91 741,2712 ; J4.15@681.46,2746.06 741,2712 ; J4.15@687.06,2754.38 741,2712 ; J4.15@692,2760 741,2712 ; J4.15@692,2761 741,2712 ; J4.15@697.52,2765.05 741,2712 ; J4.15@705.72,2770.83 741,2712 ; J4.15@714.77,2775.38 741,2712 ; U6.68@2231.85,1805.12 1808.15,1805.12 1173.27,2440 1003.6,2440 906,2440 796.47,2549.53 741,2605 741,2712
PM_UCA0RXD: J2.12 U6.16 | length 2045.1
  Top Layer w10: U6.16@2838.15,1431.1 3061.13,1431.1 3114.03,1484 3170,1484 3509,1823 J2.12@3509,2660 ; J2.12@3482.19,2653.96 3509,2597.52 ; J2.12@3491.69,2657.55 3509,2597.52 ; J2.12@3501.53,2659.55 3509,2597.52 ; J2.12@3516.47,2659.55 3509,2597.52 ; J2.12@3526.31,2657.55 3509,2597.52 ; J2.12@3535.81,2653.96 3509,2597.52
PM_UCA0TXD: J2.13 U6.17 | length 2123.6
  Top Layer w10: U6.17@2838.15,1450.79 3055.36,1450.79 3109.57,1505 3159,1505 3454.28,1800.28 3454.28,2714.72 ; J2.13@3394.19,2736.85 3454.28,2714.72 ; J2.13@3398.44,2746.07 3454.28,2714.72 ; J2.13@3404.03,2754.41 3454.28,2714.72 ; J2.13@3409,2760 3454.28,2714.72 ; J2.13@3414.59,2764.97 3454.28,2714.72 ; J2.13@3422.93,2770.56 3454.28,2714.72 ; J2.13@3432.15,2774.81 3454.28,2714.72
PM_UCA1CLK: J2.9 U6.19 | length 2480.3
  Top Layer w10: U6.19@2838.15,1490.16 3043.82,1490.16 3100.66,1547 3145,1547 3362.72,1764.72 3362.72,2792.72 3390,2820 3549,2820 J2.9@3609,2760 3555.31,2813.69 ; J2.9@3586.37,2744.41 3555.31,2813.69 ; J2.9@3595.3,2749.14 3555.31,2813.69 ; J2.9@3603.46,2754.98 3555.31,2813.69 ; J2.9@3614.02,2765.54 3555.31,2813.69 ; J2.9@3619.86,2773.7 3555.31,2813.69 ; J2.9@3624.59,2782.63 3555.31,2813.69
PM_UCA1SIMO: J2.15 U6.21 | length 2085.4
  Top Layer w10: U6.21@2838.15,1529.53 3032.28,1529.53 3094.75,1592 3119.78,1592 3246,1718.22 3246,2697 J2.15@3309,2760 3255.31,2706.31 ; J2.15@3286.37,2775.59 3255.31,2706.31 ; J2.15@3295.3,2770.86 3255.31,2706.31 ; J2.15@3303.46,2765.02 3255.31,2706.31 ; J2.15@3314.02,2754.46 3255.31,2706.31 ; J2.15@3319.86,2746.3 3255.31,2706.31 ; J2.15@3324.59,2737.37 3255.31,2706.31
PM_UCA1SOMI: J2.16 U6.20 | length 1922.6
  Top Layer w10: U6.20@2838.15,1509.84 3038.05,1509.84 3098.2,1570 3137.46,1570 3309,1741.54 J2.16@3309,2660 3309,2597.52 ; J2.16@3282.19,2653.96 3309,2597.52 ; J2.16@3291.69,2657.55 3309,2597.52 ; J2.16@3301.53,2659.55 3309,2597.52 ; J2.16@3316.47,2659.55 3309,2597.52 ; J2.16@3326.31,2657.55 3309,2597.52 ; J2.16@3335.81,2653.96 3309,2597.52
PM_UCA2CLK: J5.8 R24.1 U4.4 U6.38 | length 2819.7
  Top Layer w10: J5.8@2796.19,2653.96 2823,2597.52 ; J5.8@2805.69,2657.55 2823,2597.52 ; J5.8@2815.53,2659.55 2823,2597.52 ; J5.8@2830.47,2659.55 2823,2597.52 ; U6.38@2838.15,1864.17 2838.15,1942.15 v1(2878,1982) 2878,2005 2823,2060 J5.8@2823,2660 2823,2597.52 ; J5.8@2840.31,2657.55 2823,2597.52 ; J5.8@2849.81,2653.96 2823,2597.52 ; R24.1@4103.5,1755 4152,1755 v1(4157,1750) U4.4@4242.87,1750
  Bottom Layer w10: v1(2878,1982) 2915,2019 3278,2019 3502,1795 4112,1795 v1(4157,1750)
PM_UCA2SIMO: J5.7 R28.1 U4.5 U6.37 | length 2910.7
  Top Layer w10: J5.7@2808.19,2736.85 2868.28,2714.72 ; J5.7@2812.44,2746.07 2868.28,2714.72 ; J5.7@2818.03,2754.41 2868.28,2714.72 ; J5.7@2823,2760 2868.28,2714.72 ; J5.7@2828.59,2764.97 2868.28,2714.72 ; J5.7@2836.93,2770.56 2868.28,2714.72 ; U6.37@2838.15,1844.49 2872,1844.49 2933,1905.49 v1(2933,1971) 2933,2007 2868.28,2071.72 2868.28,2714.72 ; J5.7@2846.15,2774.81 2868.28,2714.72 ; R28.1@4103.5,1690 v1(4162,1690) 4172,1700 U4.5@4247.87,1700
  Bottom Layer w10: v1(2933,1971) 2948,1986 3174,1986 3400,1760 4092,1760 v1(4162,1690)
PM_UCA2SOMI: J5.6 U6.36 | length 1275.4
  Top Layer w10: U6.36@2838.15,1824.8 2877.77,1824.8 2964,1911.03 2964,2619 ; J5.6@2908.73,2636.52 2964,2619 ; J5.6@2912.64,2645.92 2964,2619 ; J5.6@2918.06,2654.38 2964,2619 ; J5.6@2923,2660 2964,2619 ; J5.6@2928.62,2664.94 2964,2619 ; J5.6@2937.08,2670.36 2964,2619 ; J5.6@2946.48,2674.27 2964,2619
PM_UCA3RXD: J5.9 U6.39 | length 1294.8
  Top Layer w10: J5.9@2707.81,2737.1 2772,2711 ; J5.9@2712.3,2746.18 2772,2711 ; J5.9@2718,2754.43 2772,2711 ; J5.9@2723,2760 2772,2711 ; J5.9@2728.57,2765 2772,2711 ; J5.9@2736.82,2770.7 2772,2711 ; J5.9@2745.9,2775.19 2772,2711 ; U6.39@2781.06,1921.26 2780.36,1921.96 2780.36,1970.36 2800,1990 2800,2602 2772,2630 2772,2711
PM_UCA3TXD: J5.10 U6.40 | length 1209.1
  Top Layer w10: J5.10@2696.19,2653.96 2723,2597.52 ; J5.10@2705.69,2657.55 2723,2597.52 ; J5.10@2715.53,2659.55 2723,2597.52 ; J5.10@2730.47,2659.55 2723,2597.52 ; J5.10@2740.31,2657.55 2723,2597.52 ; J5.10@2749.81,2653.96 2723,2597.52 ; U6.40@2761.38,1921.26 2761.38,1984.38 2782,2005 2782,2536 2723,2595 J5.10@2723,2660 2723,2597.52
PM_UCB0SCL: J2.8 R104.1 U6.13 | length 2403.9
  Top Layer w10: U6.13@2838.15,1372.05 3116.05,1372.05 v1(3162,1418) 3183.28,1418 3708,1942.72 J2.8@3708,2660 ; J2.8@3682.1,2654.39 3708,2597.51 ; J2.8@3691.65,2657.83 3708,2597.51 ; J2.8@3701.53,2659.67 3708,2597.51 ; J2.8@3709,2660 3708,2597.51 ; J2.8@3716.46,2659.43 3708,2597.51 ; J2.8@3726.27,2657.28 3708,2597.51 ; J2.8@3735.71,2653.53 3708,2597.51
  Bottom Layer w10: R104.1@3080,1508.5 3111.5,1508.5 3162,1458 v1(3162,1418)
PM_UCB0SDA: J2.10 R105.1 U6.14 | length 2330.9
  Top Layer w10: U6.14@2838.15,1391.73 3088.73,1391.73 3145,1448 3187.82,1448 3607,1867.18 J2.10@3607,2660 ; J2.10@3582.01,2654.83 3607,2597.46 ; J2.10@3591.62,2658.11 3607,2597.46 ; J2.10@3601.52,2659.79 3607,2597.46 ; J2.10@3609,2660 3607,2597.46 ; J2.10@3616.45,2659.31 3607,2597.46 ; J2.10@3626.22,2657.01 3607,2597.46 ; J2.10@3635.6,2653.11 3607,2597.46
  Bottom Layer w10: R105.1@3015,1508.5 v1(3110,1413.5)
PM_UCB1SCL: J5.12 R99.1 U6.42 | length 1259
  Top Layer w10: J5.12@2597.38,2650.06 2623,2622 ; J5.12@2605.99,2655.98 2623,2622 ; J5.12@2615.56,2659.26 2623,2622 ; J5.12@2630.44,2659.26 2623,2622 ; J5.12@2640.01,2655.98 2623,2622 ; J5.12@2648.62,2650.06 2623,2622 ; v1(2720,1840) 2722.01,1842.01 U6.42@2722.01,1921.26 ; 2722.99,1886.43 2722.99,2001.99 2745,2024 2745,2500 2623,2622 ; 2623,2622 J5.12@2623,2660 2623,2622
  Bottom Layer w10: v1(2720,1840) 2730,1850 R99.1@2730,1913.5
PM_UCB1SDA: J5.13 R98.1 U6.43 | length 1514.6
  Top Layer w10: J5.13@2508.01,2736.97 2570,2713 ; J5.13@2512.37,2746.12 2570,2713 ; J5.13@2518.02,2754.42 2570,2713 ; J5.13@2523,2760 2570,2713 ; J5.13@2528.58,2764.98 2570,2713 ; J5.13@2536.88,2770.63 2570,2713 ; J5.13@2546.03,2774.99 2570,2713 ; v1(2665,1835) 2702.32,1872.32 U6.43@2702.32,1921.26 2702.32,2006.78 2727,2031.46 2727,2465 2570,2622 2570,2713
  Bottom Layer w10: R98.1@2660,1913.5 2660,1840 v1(2665,1835)
RELAY1: R6.2 U1.1 | length 74
  Top Layer w10: R6.2@2204,2296.5 2204,2323.8 2216.2,2336 U1.1@2216.2,2365.43
RELAY2: R5.2 U1.2 | length 141.5
  Top Layer w10: U1.2@2216.2,2391.02 2253.98,2391.02 2271.76,2373.24 R5.2@2271.76,2294.69
RELAY3: R7.2 U1.3 | length 216.6
  Top Layer w10: U1.3@2216.2,2416.61 2289.39,2416.61 2343.76,2362.24 R7.2@2343.76,2295.69
RELAY4: R8.2 U1.4 | length 284
  Top Layer w10: U1.4@2216.2,2442.2 2314.8,2442.2 2408.76,2348.24 R8.2@2408.76,2295.69
RELAY5: R11.2 U1.5 | length 360.6
  Top Layer w10: U1.5@2216.2,2467.8 2352.2,2467.8 2474.02,2345.98 R11.2@2474.02,2293.68
RELAY6: R9.2 U1.6 | length 428.6
  Top Layer w10: U1.6@2216.2,2493.39 2378.61,2493.39 2539.02,2332.98 R9.2@2539.02,2293.68
RELAY_1: R6.1 U6.53 | length 488.7
  Top Layer w10: R6.1@2204,2233.5 2262.5,2175 2350.54,2175 2505.47,2020.07 U6.53@2505.47,1921.26
RELAY_2: R5.1 U6.52 | length 443.3
  Top Layer w10: R5.1@2271.76,2231.7 2309.45,2194 2357,2194 2525.16,2025.84 U6.52@2525.16,1921.26
RELAY_3: R7.1 U6.51 | length 394.7
  Top Layer w10: R7.1@2343.76,2232.7 2544.84,2031.61 U6.51@2544.84,1921.26
RELAY_4: R8.1 U6.50 | length 376
  Top Layer w10: R8.1@2408.76,2232.7 2408.76,2196.32 2564.53,2040.55 U6.50@2564.53,1921.26
RELAY_5: R11.1 U6.49 | length 355.1
  Top Layer w10: R11.1@2474.02,2230.69 2474.02,2156.51 2583,2047.53 2583,1988.96 2584.21,1987.75 U6.49@2584.21,1921.26
RELAY_6: R9.1 U6.48 | length 336.9
  Top Layer w10: R9.1@2539.02,2230.69 2539.02,2116.97 2601.7,2054.28 2601,2053.58 2601,1996.42 2603.9,1993.52 U6.48@2603.9,1921.26
RELAY_SPLY: C1.1 C46.1 J1.2 U1.9 | length 1022.4
  Top Layer w10: C1.1@1919.5,2565 1939.93,2544.57 U1.9@1991.8,2544.57 2020.57,2544.57 2034,2558 v1(2034,2591) ; v1@2044,2597 J1.2@2177,2730 2120.75,2673.75 ; J1.2@2152.13,2746.85 2120.75,2673.75 ; J1.2@2161.16,2742.27 2120.75,2673.75 ; J1.2@2169.47,2736.64 2120.75,2673.75 ; J1.2@2183.64,2722.47 2120.75,2673.75 ; J1.2@2189.27,2714.16 2120.75,2673.75 ; J1.2@2193.85,2705.13 2120.75,2673.75
  Bottom Layer w10: C46.1@2033.09,2486 2033.09,2583.91 2026,2591 v1(2034,2591)
RESET: C19.2 J10.11 R44.1 S1.1 S1.2 U6.102 | length 13034.1
  Top Layer w10: R44.1@1726.5,1295 1804.5,1217 1884.94,1217 1996.94,1105 ; S1.2@1908.27,1030 S1.2@1893.27,1030 ; U6.102@2231.85,1135.83 2205.83,1135.83 2175,1105 1996.94,1105 ; J10.11@1316.87,1226.65 1378.77,1196.23 ; J10.11@1316.87,1226.65 1378.77,1196.23 ; J10.11@1316.87,1226.65 1378.77,1196.23 ; J10.11@1316.87,1226.65 1378.77,1196.23 ; J10.11@1316.87,1226.65 1378.77,1196.23 ; J10.11@1316.87,1226.65 1378.77,1196.23 ; J10.11@1316.87,1226.65 1378.77,1196.23 ; J10.11@1316.87,1226.65 1378.77,1196.23 ; J10.11@1316.87,1226.65 1378.77,1196.23 ; J10.11@1316.87,1226.65 1378.77,1196.23 ; J10.11@1316.87,1226.65 1378.77,1196.23 ; J10.11@1316.87,1226.65 1378.77,1196.23 ; J10.11@1316.87,1226.65 1378.77,1196.23 ; J10.11@1316.87,1226.65 1378.77,1196.23 ; J10.11@1316.87,1226.65 1378.77,1196.23 ; J10.11@1316.87,1226.65 1378.77,1196.23 ; J10.11@1316.87,1226.65 1378.77,1196.23 ; J10.11@1316.87,1226.65 1378.77,1196.23 ; J10.11@1316.87,1226.65 1378.77,1196.23 ; J10.11@1316.87,1226.65 1378.77,1196.23 ; J10.11@1316.87,1226.65 1378.77,1196.23 ; J10.11@1316.87,1226.65 1378.77,1196.23 ; J10.11@1316.87,1226.65 1378.77,1196.23 ; J10.11@1316.87,1226.65 1378.77,1196.23 ; J10.11@1316.87,1226.65 1378.77,1196.23 ; J10.11@1316.87,1226.65 1378.77,1196.23 ; J10.11@1316.87,1226.65 1378.77,1196.23 ; J10.11@1316.87,1226.65 1378.77,1196.23 ; J10.11@1316.87,1226.65 1378.77,1196.23 ; J10.11@1316.87,1226.65 1378.77,1196.23 ; J10.11@1316.87,1226.65 1378.77,1196.23 ; J10.11@1316.87,1226.65 1378.77,1196.23 ; J10.11@1316.87,1226.65 1378.77,1196.23 ; J10.11@1316.87,1226.65 1378.77,1196.23 ; J10.11@1316.87,1226.65 1378.77,1196.23 ; J10.11@1321.96,1235.35 1378.77,1196.23 ; J10.11@1321.96,1235.35 1378.77,1196.23 ; J10.11@1321.96,1235.35 1378.77,1196.23 ; J10.11@1321.96,1235.35 1378.77,1196.23 ; J10.11@1321.96,1235.35 1378.77,1196.23 ; J10.11@1321.96,1235.35 1378.77,1196.23 ; J10.11@1321.96,1235.35 1378.77,1196.23 ; J10.11@1321.96,1235.35 1378.77,1196.23 ; J10.11@1321.96,1235.35 1378.77,1196.23 ; J10.11@1321.96,1235.35 1378.77,1196.23 ; J10.11@1321.96,1235.35 1378.77,1196.23 ; J10.11@1321.96,1235.35 1378.77,1196.23 ; J10.11@1321.96,1235.35 1378.77,1196.23 ; J10.11@1321.96,1235.35 1378.77,1196.23 ; J10.11@1321.96,1235.35 1378.77,1196.23 ; J10.11@1321.96,1235.35 1378.77,1196.23 ; J10.11@1321.96,1235.35 1378.77,1196.23 ; J10.11@1321.96,1235.35 1378.77,1196.23 ; J10.11@1321.96,1235.35 1378.77,1196.23 ; J10.11@1321.96,1235.35 1378.77,1196.23 ; J10.11@1321.96,1235.35 1378.77,1196.23 ; J10.11@1321.96,1235.35 1378.77,1196.23 ; J10.11@1321.96,1235.35 1378.77,1196.23 ; J10.11@1321.96,1235.35 1378.77,1196.23 ; J10.11@1321.96,1235.35 1378.77,1196.23 ; J10.11@1321.96,1235.35 1378.77,1196.23 ; J10.11@1321.96,1235.35 1378.77,1196.23 ; J10.11@1321.96,1235.35 1378.77,1196.23 ; J10.11@1321.96,1235.35 1378.77,1196.23 ; J10.11@1321.96,1235.35 1378.77,1196.23 ; J10.11@1321.96,1235.35 1378.77,1196.23 ; J10.11@1321.96,1235.35 1378.77,1196.23 ; J10.11@1321.96,1235.35 1378.77,1196.23 ; J10.11@1321.96,1235.35 1378.77,1196.23 ; J10.11@1321.96,1235.35 1378.77,1196.23 ; J10.11@1330,1245 1378.77,1196.23 ; J10.11@1330,1245 1378.77,1196.23 ; J10.11@1330,1245 1378.77,1196.23 ; J10.11@1330,1245 1378.77,1196.23 ; J10.11@1330,1245 1378.77,1196.23 ; J10.11@1330,1245 1378.77,1196.23 ; J10.11@1330,1245 1378.77,1196.23 ; J10.11@1330,1245 1378.77,1196.23 ; J10.11@1330,1245 1378.77,1196.23 ; J10.11@1330,1245 1378.77,1196.23 ; J10.11@1330,1245 1378.77,1196.23 ; J10.11@1330,1245 1378.77,1196.23 ; J10.11@1330,1245 1378.77,1196.23 ; J10.11@1330,1245 1378.77,1196.23 ; J10.11@1330,1245 1378.77,1196.23 ; J10.11@1330,1245 1378.77,1196.23 ; J10.11@1330,1245 1378.77,1196.23 ; J10.11@1330,1245 1378.77,1196.23 ; J10.11@1330,1245 1378.77,1196.23 ; J10.11@1330,1245 1378.77,1196.23 ; J10.11@1330,1245 1378.77,1196.23 ; J10.11@1330,1245 1378.77,1196.23 ; J10.11@1330,1245 1378.77,1196.23 ; J10.11@1330,1245 1378.77,1196.23 ; J10.11@1330,1245 1378.77,1196.23 ; J10.11@1330,1245 1378.77,1196.23 ; J10.11@1330,1245 1378.77,1196.23 ; J10.11@1330,1245 1378.77,1196.23 ; J10.11@1330,1245 1385,1190 1385,1114 1394,1105 1440.5,1058.5 1595,1058.5 C19.2@1605,1058.5 1606.5,1060 1646.73,1060 S1.1@1676.73,1030 S1.2@1893.27,1030 ; J10.11@1339.65,1253.04 1378.77,1196.23 ; J10.11@1339.65,1253.04 1378.77,1196.23 ; J10.11@1339.65,1253.04 1378.77,1196.23 ; J10.11@1339.65,1253.04 1378.77,1196.23 ; J10.11@1339.65,1253.04 1378.77,1196.23 ; J10.11@1339.65,1253.04 1378.77,1196.23 ; J10.11@1339.65,1253.04 1378.77,1196.23 ; J10.11@1339.65,1253.04 1378.77,1196.23 ; J10.11@1339.65,1253.04 1378.77,1196.23 ; J10.11@1339.65,1253.04 1378.77,1196.23 ; J10.11@1339.65,1253.04 1378.77,1196.23 ; J10.11@1339.65,1253.04 1378.77,1196.23 ; J10.11@1339.65,1253.04 1378.77,1196.23 ; J10.11@1339.65,1253.04 1378.77,1196.23 ; J10.11@1339.65,1253.04 1378.77,1196.23 ; J10.11@1339.65,1253.04 1378.77,1196.23 ; J10.11@1339.65,1253.04 1378.77,1196.23 ; J10.11@1339.65,1253.04 1378.77,1196.23 ; J10.11@1339.65,1253.04 1378.77,1196.23 ; J10.11@1339.65,1253.04 1378.77,1196.23 ; J10.11@1339.65,1253.04 1378.77,1196.23 ; J10.11@1339.65,1253.04 1378.77,1196.23 ; J10.11@1339.65,1253.04 1378.77,1196.23 ; J10.11@1339.65,1253.04 1378.77,1196.23 ; J10.11@1339.65,1253.04 1378.77,1196.23 ; J10.11@1339.65,1253.04 1378.77,1196.23 ; J10.11@1339.65,1253.04 1378.77,1196.23 ; J10.11@1339.65,1253.04 1378.77,1196.23 ; J10.11@1339.65,1253.04 1378.77,1196.23 ; J10.11@1339.65,1253.04 1378.77,1196.23 ; J10.11@1339.65,1253.04 1378.77,1196.23 ; J10.11@1339.65,1253.04 1378.77,1196.23 ; J10.11@1339.65,1253.04 1378.77,1196.23 ; J10.11@1339.65,1253.04 1378.77,1196.23 ; J10.11@1339.65,1253.04 1378.77,1196.23 ; J10.11@1348.35,1258.13 1378.77,1196.23 ; J10.11@1348.35,1258.13 1378.77,1196.23 ; J10.11@1348.35,1258.13 1378.77,1196.23 ; J10.11@1348.35,1258.13 1378.77,1196.23 ; J10.11@1348.35,1258.13 1378.77,1196.23 ; J10.11@1348.35,1258.13 1378.77,1196.23 ; J10.11@1348.35,1258.13 1378.77,1196.23 ; J10.11@1348.35,1258.13 1378.77,1196.23 ; J10.11@1348.35,1258.13 1378.77,1196.23 ; J10.11@1348.35,1258.13 1378.77,1196.23 ; J10.11@1348.35,1258.13 1378.77,1196.23 ; J10.11@1348.35,1258.13 1378.77,1196.23 ; J10.11@1348.35,1258.13 1378.77,1196.23 ; J10.11@1348.35,1258.13 1378.77,1196.23 ; J10.11@1348.35,1258.13 1378.77,1196.23 ; J10.11@1348.35,1258.13 1378.77,1196.23 ; J10.11@1348.35,1258.13 1378.77,1196.23 ; J10.11@1348.35,1258.13 1378.77,1196.23 ; J10.11@1348.35,1258.13 1378.77,1196.23 ; J10.11@1348.35,1258.13 1378.77,1196.23 ; J10.11@1348.35,1258.13 1378.77,1196.23 ; J10.11@1348.35,1258.13 1378.77,1196.23 ; J10.11@1348.35,1258.13 1378.77,1196.23 ; J10.11@1348.35,1258.13 1378.77,1196.23 ; J10.11@1348.35,1258.13 1378.77,1196.23 ; J10.11@1348.35,1258.13 1378.77,1196.23 ; J10.11@1348.35,1258.13 1378.77,1196.23 ; J10.11@1348.35,1258.13 1378.77,1196.23 ; J10.11@1348.35,1258.13 1378.77,1196.23 ; J10.11@1348.35,1258.13 1378.77,1196.23 ; J10.11@1348.35,1258.13 1378.77,1196.23 ; J10.11@1348.35,1258.13 1378.77,1196.23 ; J10.11@1348.35,1258.13 1378.77,1196.23 ; J10.11@1348.35,1258.13 1378.77,1196.23 ; J10.11@1348.35,1258.13 1378.77,1196.23 ; S1.2@1893.27,1030 1938.27,1075 1970,1075 1996.94,1101.94 1996.94,1105
SCLK_ISO: R25.2 R46.1 U5.7 | length 462.8
  Top Layer w10: R25.2@4813.5,1747 R46.1@4885.5,1747 4890.01,1747 4892.01,1745 4885.5,1745 4917,1713.5 5007.51,1713.5 5036.7,1742.68 U5.7@5237.29,1742.68
SDCLK: J5.1 R101.2 R103.1 U6.31 | length 1876.5
  Top Layer w10: U6.31@2838.15,1726.38 2903.62,1726.38 2907,1723 v1(2941,1723) 2941,1738.72 3191,1988.72 3191,2692 J5.1@3123,2760 ; J5.1@3107.41,2737.37 3176.69,2706.31 ; J5.1@3112.14,2746.3 3176.69,2706.31 ; J5.1@3117.98,2754.46 3176.69,2706.31 ; J5.1@3128.54,2765.02 3176.69,2706.31 ; J5.1@3136.7,2770.86 3176.69,2706.31 ; J5.1@3145.63,2775.59 3176.69,2706.31
  Bottom Layer w10: R103.1@2874.5,1680 2876.5,1682 R101.2@2876.5,1751 2913,1751 v1(2941,1723)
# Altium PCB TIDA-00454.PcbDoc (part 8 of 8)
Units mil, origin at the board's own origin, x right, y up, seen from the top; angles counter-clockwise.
Board outline 6159 x 2859 mil, 2 copper layers (Top Layer, Bottom Layer), stack 62 mil thick; 328 components, 224 nets, 884 pads, 184 vias.

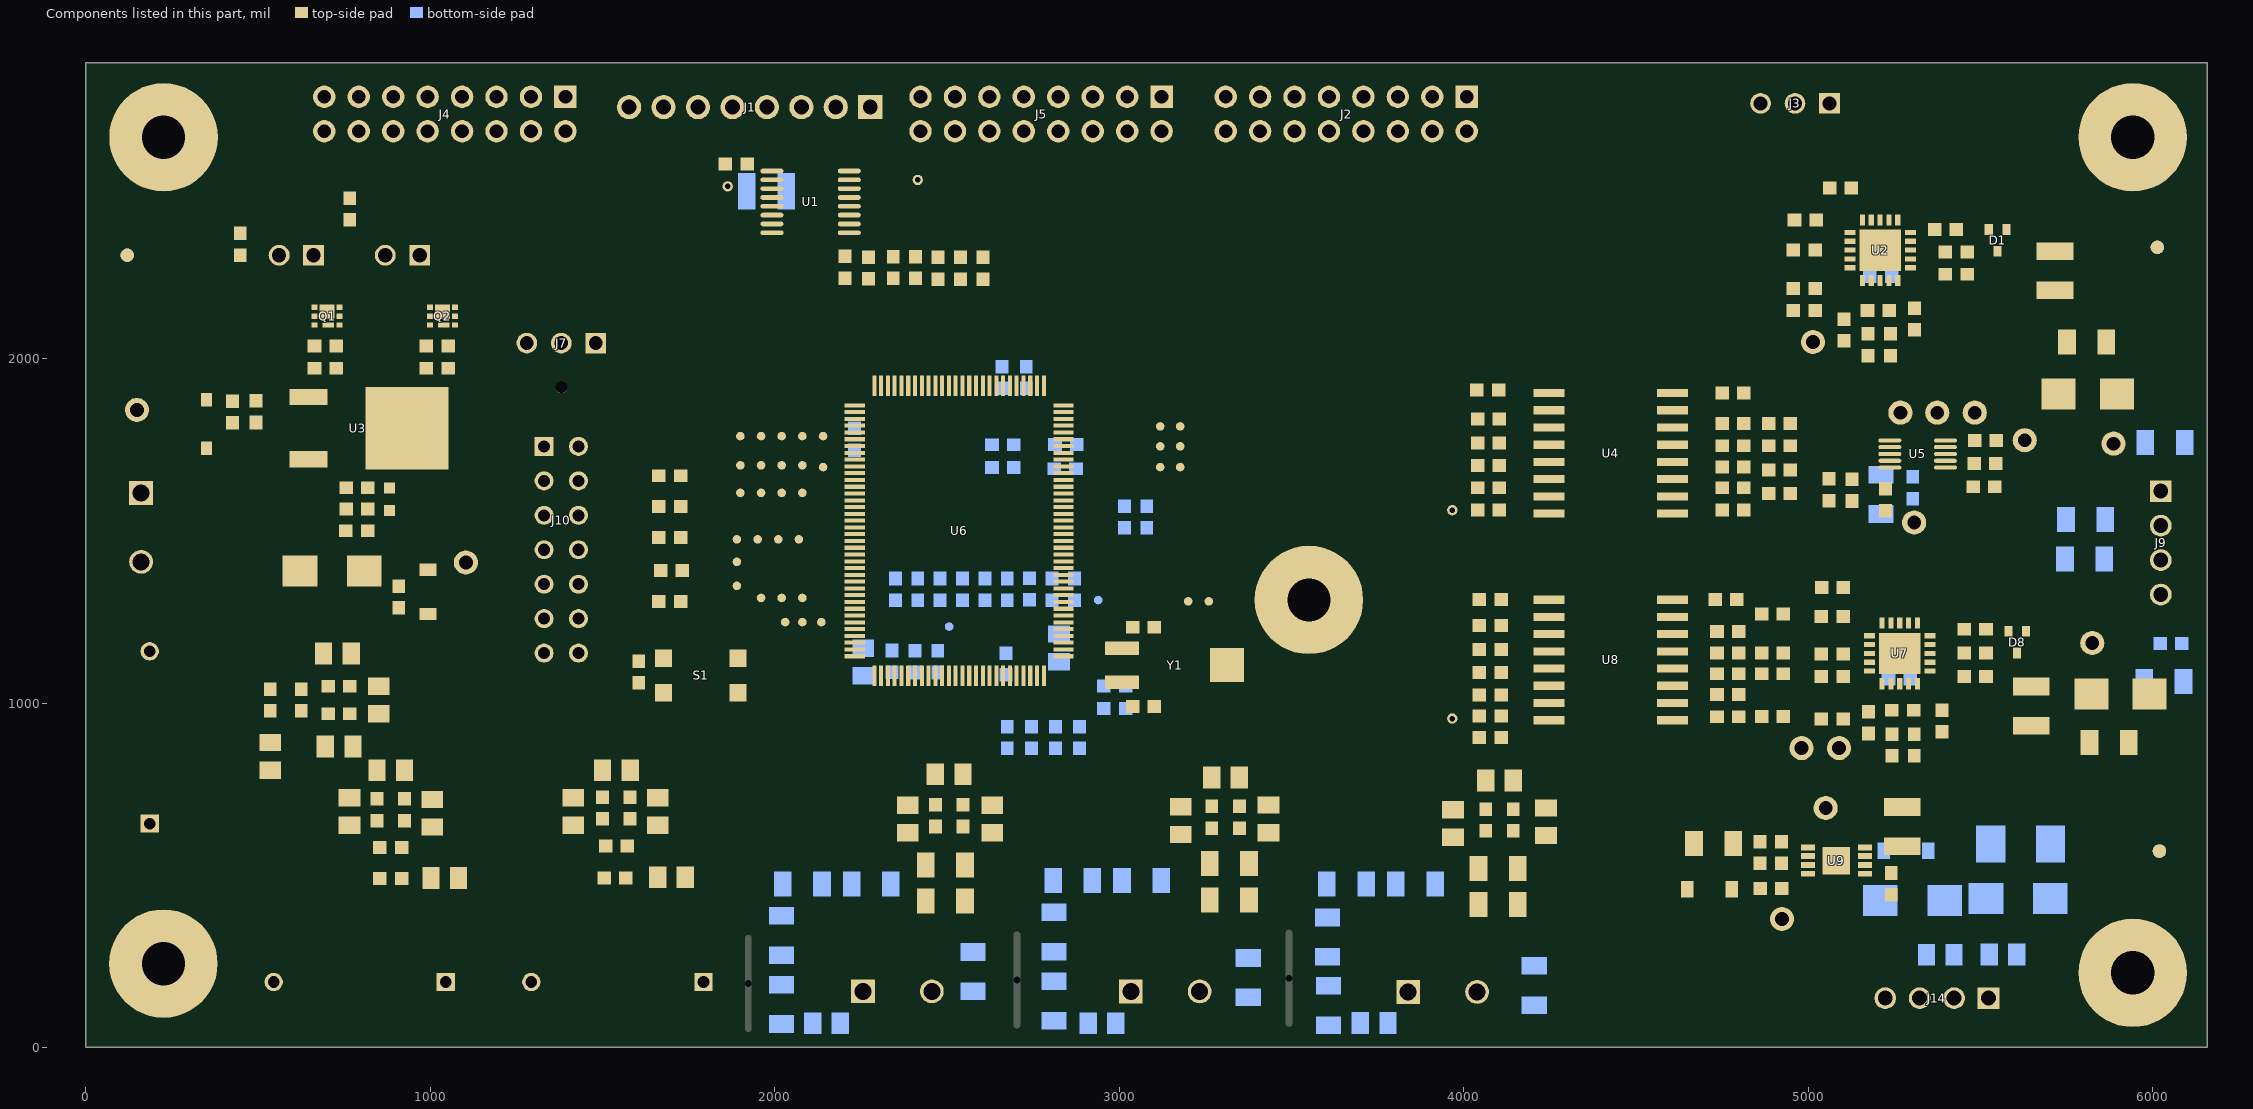
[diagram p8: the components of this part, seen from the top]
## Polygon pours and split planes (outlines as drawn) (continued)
GND_ISO on Top Layer "Top Layer-No Net" (solid, pour order 34): 5021,381 4939,299 4667,299 4588,378 4588,613 4604,629 4699.33,629 4714,615.46 4714,416.87 4745.62,399 4866,399 4904,437 4904,478 4933,507 4963,507 4968,512 5007,512 5021,498
VCC_ISO on Top Layer "Top Layer-No Net" (solid, pour order 28): 4769,815 4868,815 4882,801 4882,654 4901,635 4999,635 5019,615 5019,571 4834,571 4825,562 4825,425 4820,420 4765,420 4757,428 4757,803
-15V on Top Layer "Top Layer-No Net" (solid, pour order 41): 5207,1084 5207,1201 5209,1203 5324,1203 5326,1201 5326,1101 5327,1100 5463,1100 5475,1088 5475,1026 5460,1011 5426,1011 5335,1085 5210,1085 5209,1084
-15V on Top Layer "Top Layer-No Net" (solid, pour order 42): 5150,2255 5150,2372 5152,2374 5267,2374 5269,2372 5269,2272 5270,2271 5406,2271 5418,2259 5418,2223 5405,2210 5325,2210 5280,2255 5153,2256 5152,2255
DGND on Bottom Layer "Top Layer-No Net" (solid, remove dead copper, pour order 31): 970,1189 1065,1094 2168,1094 2207,1133 2428,1133 2513,1218 2664,1218 3012.14,869.86 4215,874 4268,927 4290,2770 4240,2820 665,2820 620,2775 620,2565 465,2410 115,2410 60,2350 65,1255 350,1255 420,1190
GND_ISO on Bottom Layer "Bottom Layer-No Net 1" (solid, remove dead copper, pour order 30): 5166,97 5246,97 5254,97 5271,114 5277,120 5277,167 5277,178 5303,204 5305,206 5344,206 5352,206 5367,221 5371,225 5371,304 5370,304 5281,393 5284,396 5284,577 5284,585 5269,600 5268,599 5189,599 5176,599 5156,579 5148,571 5148,478 5148,114 5167,95
AGND on Bottom Layer "Top Layer-No Net" (solid, remove dead copper, pour order 33): 203,1153 963,1153 1045,1071 2175,1071 2212,1108 2467,1108 2525,1166 2629,1166 2693,1108 2966,835 4212,835 4273,774 4270,120 4210,60 3395,60 2510,65 657.42,65 657.42,365 535,455 245,455 185,535 185,1125 202,1152 203,1152
-15V on Bottom Layer "Bottom Layer-No Net 1" (solid, remove dead copper, pour order 27): 5385,86 5453,86 5469,102 5469,295 5442,322 5442,603 5420,625 5345.5,625 5323,602.5 5325,375 5380,320 5380,190 5370,175 5370,95
+15V on Bottom Layer "Bottom Layer-No Net 1" (solid, remove dead copper, pour order 22): 5489,86 5558,86 5587.98,85 5615,105 5615,185 5554,231 5554,345 5572,363 5572,643 5557,658 5486,658 5462,634 5462,349 5486,325 5486,91 5485,90
GND_ISO on Bottom Layer "Top Layer-No Net" (solid, remove dead copper, pour order 26): 5435,65 5435,705 5745,990 5744.51,2796 5700,2830 4565,2830 4554.51,2811 4555,100 4590,65

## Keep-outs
Bottom Layer:
  circle w10: c225.15,245 r214.85
Multi-Layer:
  circle w10: c3550.83,1299.21 r196.85
  circle w10: c5942.48,216.54 r214.85
  circle w10: c5942.48,2642.48 r214.85
  circle w10: c225.15,2640 r214.85

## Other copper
Top Layer:
  text ".Layer_Name" at 742,-858.49 h60
Bottom Layer:
  pour cut-out: 1881.54,1.69 1885,5.15 1885,510 1920,545 2355,545 2405,495 2405,35.52 2369.48,0 1890,0
  pour cut-out: 2149,15 2144.58,15 2135.58,24 2135.58,499.58 2170,534 4220,534 4292,462 4292,66 4241,15 4240.6,15.4 2135.58,15.4
  pour cut-out: 0.2,1239.58 371.6,1239.58 371.6,562.42 2.98,562.42 -3.6,569 0.2,572.8
  pour cut-out: 1206.74,2.4 1206.74,377.6 1878.3,377.6 1883.9,372 1883.9,1.69 1883.19,2.4
  pour cut-out: 452.42,376.6 1129.58,376.6 1129.58,0.69 453.13,0.69 452.42,1.4
  pour cut-out: 615.74,2277.87 615.74,2375.74 616,2376 574,2376 574,2278 576,2276 577.87,2277.87
  pour cut-out: 2460.44,1858.97 2463,1861.53 2463,1933 2419,1933 2415,1929 2416,1928 2416,1870 2449.41,1870
  text ".Layer_Name" at 742,-858.49 h60

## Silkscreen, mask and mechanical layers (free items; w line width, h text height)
Top Overlay:
  circle w6: c5836,599 r39.45
  circle w6: c4768,1382 r39.45
  circle w6: c4688,2421 r39.45
  circle w6: c4919,1894 r39.45
  circle w6: c2033,663 r39.45
  circle w6: c2018,1385 r39.45
  circle w10: c2969,1195 r2.24
  circle w8: c3180,2125 r63
  circle w10: c1673,960 r2
  circle w6: c4185,1300 r5
  circle w6: c4185,1900 r5
  circle w6: c5405,1665 r5
  lines w6: 792,932 800,924 816,924 825,915 ; 795,1085 805,1095 830,1095 ; 804,1284 831,1284 ; 804.63,601.99 804.99,601.99 824,621 ; 805,520 805,522 825,542 ; 817,1272 817,1295 ; 949,621 949,620 957,612 957,597.99 ; 2021,1931 2022,1931 2062,1891 2062,1834 ; 2046,1850 2062,1834 ; 2078,1849 2063,1834 2062,1834 ; 2421,753 2423,753 2435,741 ; 2578,740 2583.01,740 2590.01,747 ; 3214.62,747.5 3217.5,747.5 3230,735 ; 3375.89,728.49 3394.91,747.5 3397.63,747.5 ; 3997.63,920.99 3997.63,932.63 4010,945 ; 4010,738 4012,738 4028,722 ; 4180,722 4193,735 4194,735 ; 4988,1312 4988,1287 5002,1273 ; 5500,2285 5504.99,2285 5514,2275.99 ; 1648,1850 1648,2309 1667,2328 1979,2328 2006,2301 2006,1885 1942,1821 1677,1821 1648,1850 ; 1831,1305 1831,1514 1852,1535 2115,1535 2155,1495 2155,1302 2118,1265 1871,1265 1831,1305 ; 1840,1596 1873,1563 2144,1563 2181,1600 2181,1806 2167,1820 1865,1820 1840,1795 1840,1596 ; 1900,710 1900,895 2024,1019 2281,1019 2320,980 2320,634 2319,634 2290,605 2005,605 1900,710 ; 4418,2115 4418,2461 4433,2476 4717,2476 4756,2437 4756,2100 4730,2074 4459,2074 4418,2115 ; 4679,1531 4705,1505 4965,1505 4997,1537 4997,1905 4931,1971 4715,1971 4679,1935 4679,1531 ; 4688,924 4688,1435 4820,1435 4971,1284 4971,1002 4985,988 5114,988 5145,1019 5417,1019 5427,1009 5427,832 5394,799 5205,799 5135,869 5135,899 5122,912 4700,912 4688,924 ; 5520,411 5520,798 5785,798 5820,763 5820,716 5846,690 6105,690 6150,645 6150,386 6141,377 5554,377 5520,411
  lines w9: 3138.5,2167.5 3222.5,2083.5
  text "B" at 4674,2403 h40
  text "TIDA-00454" at 2950,2325 h50
  text "REV: E1" at 2965,2235 h50
  text "PB" at 3141,2101 h50
  text "B" at 4905,1876 h40
  text "A" at 2004,1367 h40
  text "C" at 4754,1364 h40
  text "A" at 2019,645 h40
  text "C" at 5822,581 h40
  text ".Layer_Name" at 742,-858.49 h60
Bottom Overlay:
  lines w6: 5130,350 5160,350 ; 5145,335 5145,365 ; 5510,340 5535,340 ; 5520,325 5520,355
  text ".Layer_Name" at 742,-858.49 h60
Top Paste:
  text ".Layer_Name" at 742,-858.49 h60
Bottom Paste:
  text ".Layer_Name" at 742,-858.49 h60
Top Solder:
  text ".Layer_Name" at 742,-858.49 h60
  text ".Layer_Name" at 742,-858.49 h60
Bottom Solder:
  text ".Layer_Name" at 742,-858.49 h60
Drill Guide:
  text ".Layer_Name" at 742,-858.49 h60
M1 Board Outline:
  the board outline again, w10
M2 Board Dimensions:
  rectangle: 289.5,-410.5 664.5,-285.5
  rectangle: 164.5,-285.5 289.5,-160.5
  lines w7: 164.5,-285.5 1164.5,-285.5 ; 289.5,-410.5 289.5,-160.5 ; 414.5,-410.5 414.5,-160.5 ; 664.5,-410.5 664.5,-160.5 ; 914.5,-410.5 914.5,-160.5 ; 164.5,-410.5 164.5,-160.5 1164.5,-160.5 1164.5,-410.5 164.5,-410.5
  lines w10: 164.5,-475.5 164.5,-455.5 ; 224.5,-485.5 164.5,-465.5 ; 224.5,-445.5 164.5,-465.5 ; 388.58,-465.5 164.5,-465.5 ; 940.42,-465.5 1164.5,-465.5 ; 1104.5,-485.5 1164.5,-465.5 ; 1104.5,-445.5 1164.5,-465.5 ; 1164.5,-475.5 1164.5,-455.5
  text "1000 (mil)" at 398.58,-501.49 h60
M3 3D STEP Top:
  text ".Layer_Name" at 742,-858.49 h60
M4 3D STEP Bottom:
  text ".Layer_Name" at 742,-858.49 h60
M5 Assembly Top:
  circle w10: c1647.93,955 r7.07
  circle w6: c545,1900 r5
  lines w6: 1845,1700 1855,1690 1865,1690 ; 1981,1578 1997,1562 2105,1562
  lines w10: -127,-930.17 6473,-930.17 ; -127,-726.83 6475,-726.83 ; -127,-523.5 -127,-1133.5 3878,-1133.5 6475,-1133.5 6475,-523.5 -126.5,-523.5 -126.5,-1133.5 1449,-1133.5 ; 2338,-1133.5 2338,-523.5 ; 3913,-726.83 3913,-523.5 ; 4445,-726.83 4445,-523.5 ; 5067,-1140 5067,-937.17
  text "COMPONENTS MARKED 'DNP' SHOULD NOT BE POPULATED." at 1318.5,-318.5 h60
  text "ASSEMBLY VARIANT:" at 1318,-434 h60
  text ".VariantName" at 2354,-434 h60
  text ".prj_number" at 2875,-655 h60
  text "REV:" at 3960,-655 h60
  text "PCB VIEWED FROM TOP SIDE" at -63.5,-655.67 h60
  text "BOARD #:" at 2413,-655.67 h60
  text "SVN REV:" at 4641,-655.67 h60
  text ".VersionControl_RevNumber" at 5147,-655.67 h60
  text "E1" at 4203,-657 h60
  text "Top Assembly" at 740,-857 h60
  text "PLOT NAME =" at -63.5,-1064.34 h60
  text ".plot_File_Name" at 742,-1064.34 h60
  text "GENERATED    :" at 2415,-1064.34 h60
  text ".Print_Date" at 3284.5,-1064.34 h60
  text ".Print_Time" at 4013.5,-1064.34 h60
  text "TEXAS INSTRUMENTS" at 5278,-1064.34 h60
M6 Assembly Bottom:
  lines w10: -127.5,-727.33 6474.5,-727.33 ; -125.5,-930.67 6474.5,-930.67 ; 1280.5,-1140.5 1280.5,-937.67 ; 1902.5,-727.33 1902.5,-524 ; 2339,-726.83 2339,-523.5 ; 4009.5,-1134 4009.5,-524 ; 4898.5,-1134 6474,-1134 6474,-524 -127.5,-524 -127.5,-1134 2469.5,-1134 6474.5,-1134 6474.5,-524
  text "COMPONENTS MARKED 'DNP' SHOULD NOT BE POPULATED." at 6267,-318 h60
  text ".VariantName" at 5223,-434 h60
  text "ASSEMBLY VARIANT:" at 6262,-434 h60
  text "REV:" at 2276,-652 h60
  text ".VersionControl_RevNumber" at 1200.5,-656.17 h60
  text "SVN REV:" at 1706.5,-656.17 h60
  text "TIDA-00454" at 3389,-656.17 h60
  text "BOARD #:" at 3934.5,-656.17 h60
  text "PCB VIEWED FROM BOTTOM SIDE" at 6411,-656.17 h60
  text "E1" at 2052,-659 h60
  text "Bottom Assembly" at 2462,-858 h60
  text "TEXAS INSTRUMENTS" at 1069.5,-1064.84 h60
  text ".Print_Time" at 2334,-1064.84 h60
  text ".Print_Date" at 3063,-1064.84 h60
  text "GENERATED    :" at 3932.5,-1064.84 h60
  text ".plot_File_Name" at 5605.5,-1064.84 h60
  text "PLOT NAME =" at 6411,-1064.84 h60
M9 Title Sheet:
  drawing of 57 lines, arcs and shapes, not listed
  text "1" at 904.84,8036.5 h70
  text "2" at 3400.5,8036.5 h70
  text "3" at 5889.84,8036.5 h70
  text "4" at 8396.51,8036.5 h70
  text "5" at 10895.5,8036.5 h70
  text "6" at 13400.5,8036.5 h70
  text "A" at -251.5,6893.5 h70
  text "A" at 14548.5,6893.5 h70
  text "B" at -251.5,4513.5 h70
  text "B" at 14548.5,4513.5 h70
  text "C" at -251.5,2138.5 h70
  text "C" at 14548.5,2138.5 h70
  text "PROJECT TITLE:" at 11508.5,277.5 h45
  text "TIDA-00454" at 11558.5,144.17 h70
  text "DESIGNED FOR:" at 11508.5,-23.5 h45
  text ".PRJ_Customer" at 11558.5,-163.5 h70
  text "D" at -251.5,-231.5 h70
  text "D" at 14548.5,-231.5 h70
  text "FILE NAME:" at 11508.5,-323.5 h45
  text "TIDA-00454" at 11863,-429 h70
  text "Texas Instruments (TI) and/or its licensors do not warrant the accuracy or completeness of this specification" at 6539,-605.34 h45
  text "ENGINEER:" at 11508.5,-613.5 h45
  text "LAYOUT BY:" at 13013.5,-613.5 h45
  text "or any information contained therein. TI and/or its licensors do not warrant that this design will meet" at 6494.01,-718 h45
  text ".PRJ_Engineer" at 11558.5,-768.49 h70
  text ".PCB_Layout" at 13064,-768.49 h40
  text "the specifications, will be suitable for your application or fit for any particular purpose, or will operate in" at 6494.01,-830.67 h45
  text "ALTIUM DESIGNER VERSION:" at 13013.5,-923.5 h45
  text "an implementation. TI and/or its licensors do not warrant that the design is production worthy. You should" at 6494.01,-943.33 h45
  text "completely validate and test your design implementation to confirm the system functionality for your application." at 6539,-1056 h45
  text ".print_Scale" at 11558.5,-1056.83 h70
  text ".Application_BuildNumber" at 13064,-1056.83 h70
  text "1" at 904.84,-1263.5 h70
  text "2" at 3400.5,-1263.5 h70
  text "3" at 5889.84,-1263.5 h70
  text "4" at 8396.51,-1263.5 h70
  text "5" at 10895.5,-1263.5 h70
  text "6" at 13400.5,-1263.5 h70
M10 Fab Notes:
  drawing of 212 lines, arcs and shapes, not listed
  text "DESIGN INFORMATION" at 12546.02,6810 h60
  text "(REFER ALSO ARRAY/PANEL PROFILING INFORMATION)" at 12184.46,6648.29 h60
  text "BOARD SIZE" at 11498.46,6644 h60
  text "6159" at 12030,6520 h60
  text "X" at 12466.46,6516.18 h60
  text "2859 MILS" at 12697.78,6516.18 h60
  text "Number of Layers :" at 11896.46,6416 h60
  text "2" at 12991.27,6406 h60
  text "MIN. TRACK WIDTH:" at 11896.46,6277 h60
  text "10" at 12992.7,6277 h60
  text "MIL" at 13147.46,6277 h60
  text "MIL" at 13170,6152 h60
  text "MIN. CLEARANCE:" at 11896.46,6145 h60
  text "7.874" at 12865,6145 h60
  text "MIN. VIA PAD SIZE:" at 11896.46,6013 h60
  text "24" at 12962.71,6013 h60
  text "MIL" at 13147.46,6013 h60
  text "0.152mm (6MIL)" at 12591.46,5871.29 h60
  text "MINIMUM ANNULAR RING" at 11567.23,5867 h60
  text "EXTERNAL" at 13299.46,5867 h60
  text "PER" at 11767.23,5749 h60
  text "IPC-D-275 CLASS 2 LEVEL C" at 11987.23,5749 h60
  text "MIL, HOLES" at 13475.46,5636.71 h60
  text "+/-" at 13083,5636 h60
  text "+/-" at 13937,5636 h60
  text "REGISTRATION TOLERANCES:" at 11567.23,5631 h60
  text "METAL" at 12767,5631 h60
  text "5" at 13343.2,5631 h60
  text "3" at 14176.2,5631 h60
  text "MIL" at 14292.46,5631 h60
  text "VIA'S ARE TENTED" at 11799.46,5514 h60
  text "MATERIAL:" at 11497.46,5324.54 h60
  text "FR-4 High Tg" at 12483.9,5184.21 h60
  text "X" at 13216.53,5180.64 h60
  text "FR-408" at 11918.46,5175.64 h60
  text "OTHER" at 13406.46,5175.64 h60
  text "FR-4" at 13748.46,5170.64 h60
  text "63 MIL (1.6mm) +/-10%" at 12238.56,5012.92 h60
  text "THICKNESS:" at 11572.23,5008.64 h60
  text "X" at 12110.4,5008.64 h60
  text "OTHER" at 13523.46,5008.64 h60
  text "TOLERANCE:" at 11572.23,4850.64 h60
  text "X" at 12411.53,4850.64 h60
  text "ANSI IPC-6012 TYPE 3 CLASS 2" at 12598.48,4850.64 h60
  text "OTHER +/-" at 12598.46,4694.64 h60
  text "BOW & TWIST:" at 11572.23,4537.64 h60
  text "X" at 12411.53,4537.64 h60
  text "ANSI IPC-6012 TYPE 3 CLASS 2" at 12598.48,4537.64 h60
  text "OTHER +/-" at 12598.46,4379.13 h60
  text "COPPER THICKNESS (FINISHED):" at 11497.46,4243.64 h60
  text "1.4MIL (1oz)" at 12377.46,4090.92 h60
  text "2MIL (1.4oz)" at 13144.46,4090.92 h60
  text "2.8MIL (2oz)" at 13871.46,4090.92 h60
  text "OUTER:" at 11854.46,4086.64 h60
  text "X" at 12249,4086 h60
  text "1.4MIL (1oz)" at 12377.46,3933.92 h60
  text "2.8MIL (2oz)" at 13144.46,3933.92 h60
  text "N/A" at 13871,3934.29 h60
  text "INNER SIGNAL:" at 11565.38,3929.64 h60
  text "DRILLING:" at 11497.46,3790.64 h60
  text "REFERENCE:" at 11572.23,3673.64 h60
  text "X" at 12220.46,3673.64 h60
  text "AS SHOWN" at 12407.46,3673.64 h60
  text "X" at 13121.46,3673.64 h60
  text "NC_DRILL FILES" at 13258.46,3673.64 h60
  text "PTH MIN COPPER THICKNESS:" at 11572.23,3515.64 h60
  text "X" at 12922.46,3515.64 h60
  text "1MIL" at 13059.46,3515.64 h60
  text "OTHER" at 13556.46,3515.64 h60
  text "BOARD FINISH:" at 11497.46,3356.64 h60
  text "SILKSCREEN:" at 11652.68,3238.64 h60
  text "X" at 12601.46,3238.64 h60
  text "TOP" at 12727.46,3238.64 h60
  text "X" at 13111.46,3238.64 h60
  text "BOTTOM" at 13238.46,3238.64 h60
  text "SILKSCREEN COLOR:" at 11652.68,3071.64 h60
  text "X" at 12600.42,3071.64 h60
  text "WHITE" at 12727.46,3071.64 h60
  text "OTHER" at 13238.46,3071.64 h60
  text "SOLDER RESIST COLOR:" at 11652.68,2901.64 h60
  text "X" at 12220.42,2742.44 h60
  text "GREEN" at 12347.46,2742.44 h60
  text "BLUE" at 12938.46,2742.44 h60
  text "OTHER" at 13476.46,2742.44 h60
  text "IMMERSION GOLD (ENIG)" at 12558.46,2553.92 h60
  text "ENEPIG" at 13896,2550.64 h60
  text "SURFACE FINISH:" at 11497.46,2549.64 h60
  text "X" at 12371.51,2549.64 h60
  text "IMM. TIN/SILVER OR EQUIV" at 11827,2392.64 h60
  text "OTHER" at 13258.46,2392.64 h60
  text "ARRAY/PANEL:" at 11497.46,2213.64 h60
  text "CUT AND TRIM PER MECH LAYER 1" at 12558.46,2209.35 h60
  text "N.C. ROUTE" at 12558.46,2057.64 h60
  text "X" at 13237.46,2057.64 h60
  text "V. SCORE" at 13424.46,2057.64 h60
  text "CERTIFICATION:" at 11497.46,1920.64 h60
  text "MATERIALS AND WORKMANSHIP FOR ALL PCBS" at 12222.46,1920.64 h60
  text "TO MEET OR EXCEED THE REQUIREMENTS OF:" at 12222.46,1822.64 h60
  text "X" at 11848.96,1686.13 h60
  text "ANSI IPC-A-600F CLASS ->" at 11987.96,1686.13 h60
  text "X" at 13627.02,1686.13 h60
  text "2" at 13745.96,1686.14 h60
  text "1" at 13430.96,1684.64 h60
  text "3" at 14099.96,1684.64 h60
  text "X" at 11851.02,1526.64 h60
  text "UL 94V-0" at 11987.96,1526.64 h60
  text "X" at 12663.02,1526.64 h60
  text "RoHS" at 12799.96,1526.64 h60
  text "OTHER" at 13444.36,1526.64 h60
  text "PER ORDER" at 13841.42,1526.64 h60
  text "ADDITIONAL REQUIREMENTS:" at 11497.46,1385.64 h60
  text "MICROSECTION:" at 11572.23,1270.64 h60
  text "YES" at 12477.96,1270.64 h60
  text "IMPEDENCE CONTROL: NO" at 12745,1265 h60
  text "REQUIRED" at 13339.46,1114.49 h60
  text "BARE BOARD ELEC. TEST:" at 11572.23,1111.64 h60
  text "NONE" at 12877.96,1111.64 h60
  text "X" at 13212.46,1111.64 h60
  text "PER ORDER" at 13931.46,1111.64 h60
  text "MANUFACTURER'S UL:" at 11572.23,954.64 h60
  text "RAIL" at 12737.96,950.35 h60
  text "METAL" at 13229.77,950.35 h60
  text "X" at 13605,950 h60
  text "SILK" at 13741.46,950.35 h60
M11 Gerber Information:
  lines w10: -127,-930.17 6473,-930.17 ; -127,-726.83 6475,-726.83 ; -127,-523.5 -127,-1133.5 3878,-1133.5 6475,-1133.5 6475,-523.5 ; -126.5,-530 6475,-530 ; -126.5,-523.5 -126.5,-1133.5 1449,-1133.5 ; 2338,-1133.5 2338,-523.5 ; 3910,-728.33 3910,-525 ; 4445,-726.83 4445,-523.5 ; 5067,-1140 5067,-937.17
  text "REV:" at 3960,-654 h60
  text "TIDA-00454" at 2875,-655 h60
  text "ALL ARTWORK VIEWED FROM TOP SIDE" at -63.5,-655.67 h60
  text "BOARD #:" at 2413,-655.67 h60
  text "SVN REV:" at 4641,-655.67 h60
  text ".VersionControl_RevNumber" at 5147,-655.67 h60
  text "E1" at 4205,-659 h60
  text "LAYER NAME =" at -63.5,-858.49 h60
  text "PLOT NAME =" at -63.5,-1064.34 h60
  text ".plot_File_Name" at 742,-1064.34 h60
  text "GENERATED    :" at 2415,-1064.34 h60
  text ".Print_Date" at 3284.5,-1064.34 h60
  text ".Print_Time" at 4013.5,-1064.34 h60
  text "TEXAS INSTRUMENTS" at 5278,-1064.34 h60
M12 Stackup:
  lines w6: 11525,7460 14075,7460 ; 11525,7564.4 14075,7564.4 ; 11465,6975 ccw(c11499,6975) 11499,6941 14101,6941 ccw(c14101,6975) 14135,6975 14135,7681 ccw(c14101,7681) 14101,7715 11499,7715 ccw(c11499,7681) 11465,7681 11465,6975
  text "Layer Stack Up Detail for: TIDA-00454 PcbDoc" at 11525,7597.1 h57
  text "Layer" at 11525,7525.4 h30
  text "Gerber" at 12420.81,7525.4 h30
  text "Copper" at 12984.33,7525.4 h30
  text "Dielectric" at 13587.04,7525.4 h30
  text "Name" at 11525,7477.4 h30
  text "Document" at 12420.81,7477.4 h30
  text "Thickness" at 12984.33,7477.4 h30
  text "Material" at 13587.04,7477.4 h30
  text "Top Solder Mask" at 11525,7384.44 h34
  text "(.GTS)" at 12420.81,7384.44 h34
  text "Solder Resist" at 13587.04,7384.44 h34
  text "Top Layer" at 11525,7287.69 h34
  text "(.GTL)" at 12420.81,7287.69 h34
  text "1.4mil" at 12984.33,7287.69 h34
  text "FR-4" at 13587.04,7239.31 h34
  text "Bottom Layer" at 11525,7190.94 h34
  text "(.GBL)" at 12420.81,7190.94 h34
  text "1.4mil" at 12984.33,7190.94 h34
  text "Bottom Solder Mask" at 11525,7094.19 h34
  text "(.GBS)" at 12420.81,7094.19 h34
  text "Solder Resist" at 13587.04,7094.19 h34
M13 Component Bodies Top:
  text ".Layer_Name" at 742,-858.49 h60
  text ".Layer_Name" at 742,-858.49 h60
M14 Component Bodies Bottom:
  text ".Layer_Name" at 742,-858.49 h60
M15 Courtyards Top:
  text ".Layer_Name" at 742,-858.49 h60
M16 Courtyards Bottom:
  text ".Layer_Name" at 742,-858.49 h60
Drill Drawing:
  text ".legend" at 565,3555 h60
  text "DRILL TOLERANCES:" at 56,3372 h60
  text "FOR PTH +/-3MILS" at 1126,3368 h60
  text "FOR NPTH +/-2MILS" at 1124,3234 h60
  text "FOR 12 MIL VIA : +0/-12 MIL" at 1131,3107 h60
  text "FOR 16 MIL VIA : +0/-16 MIL" at 1133,2996 h60
  text ".Layer_Name" at 742,-858.49 h60

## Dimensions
0,0 to 0,2859 on M2 Board Dimensions
0,2859 to 6159,2859 on M2 Board Dimensions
